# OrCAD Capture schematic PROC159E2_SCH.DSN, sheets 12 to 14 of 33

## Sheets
12 28. LED DRIVER AND IO EXPANDER: size C; title: LED DRIVER AND IO EXPANDER
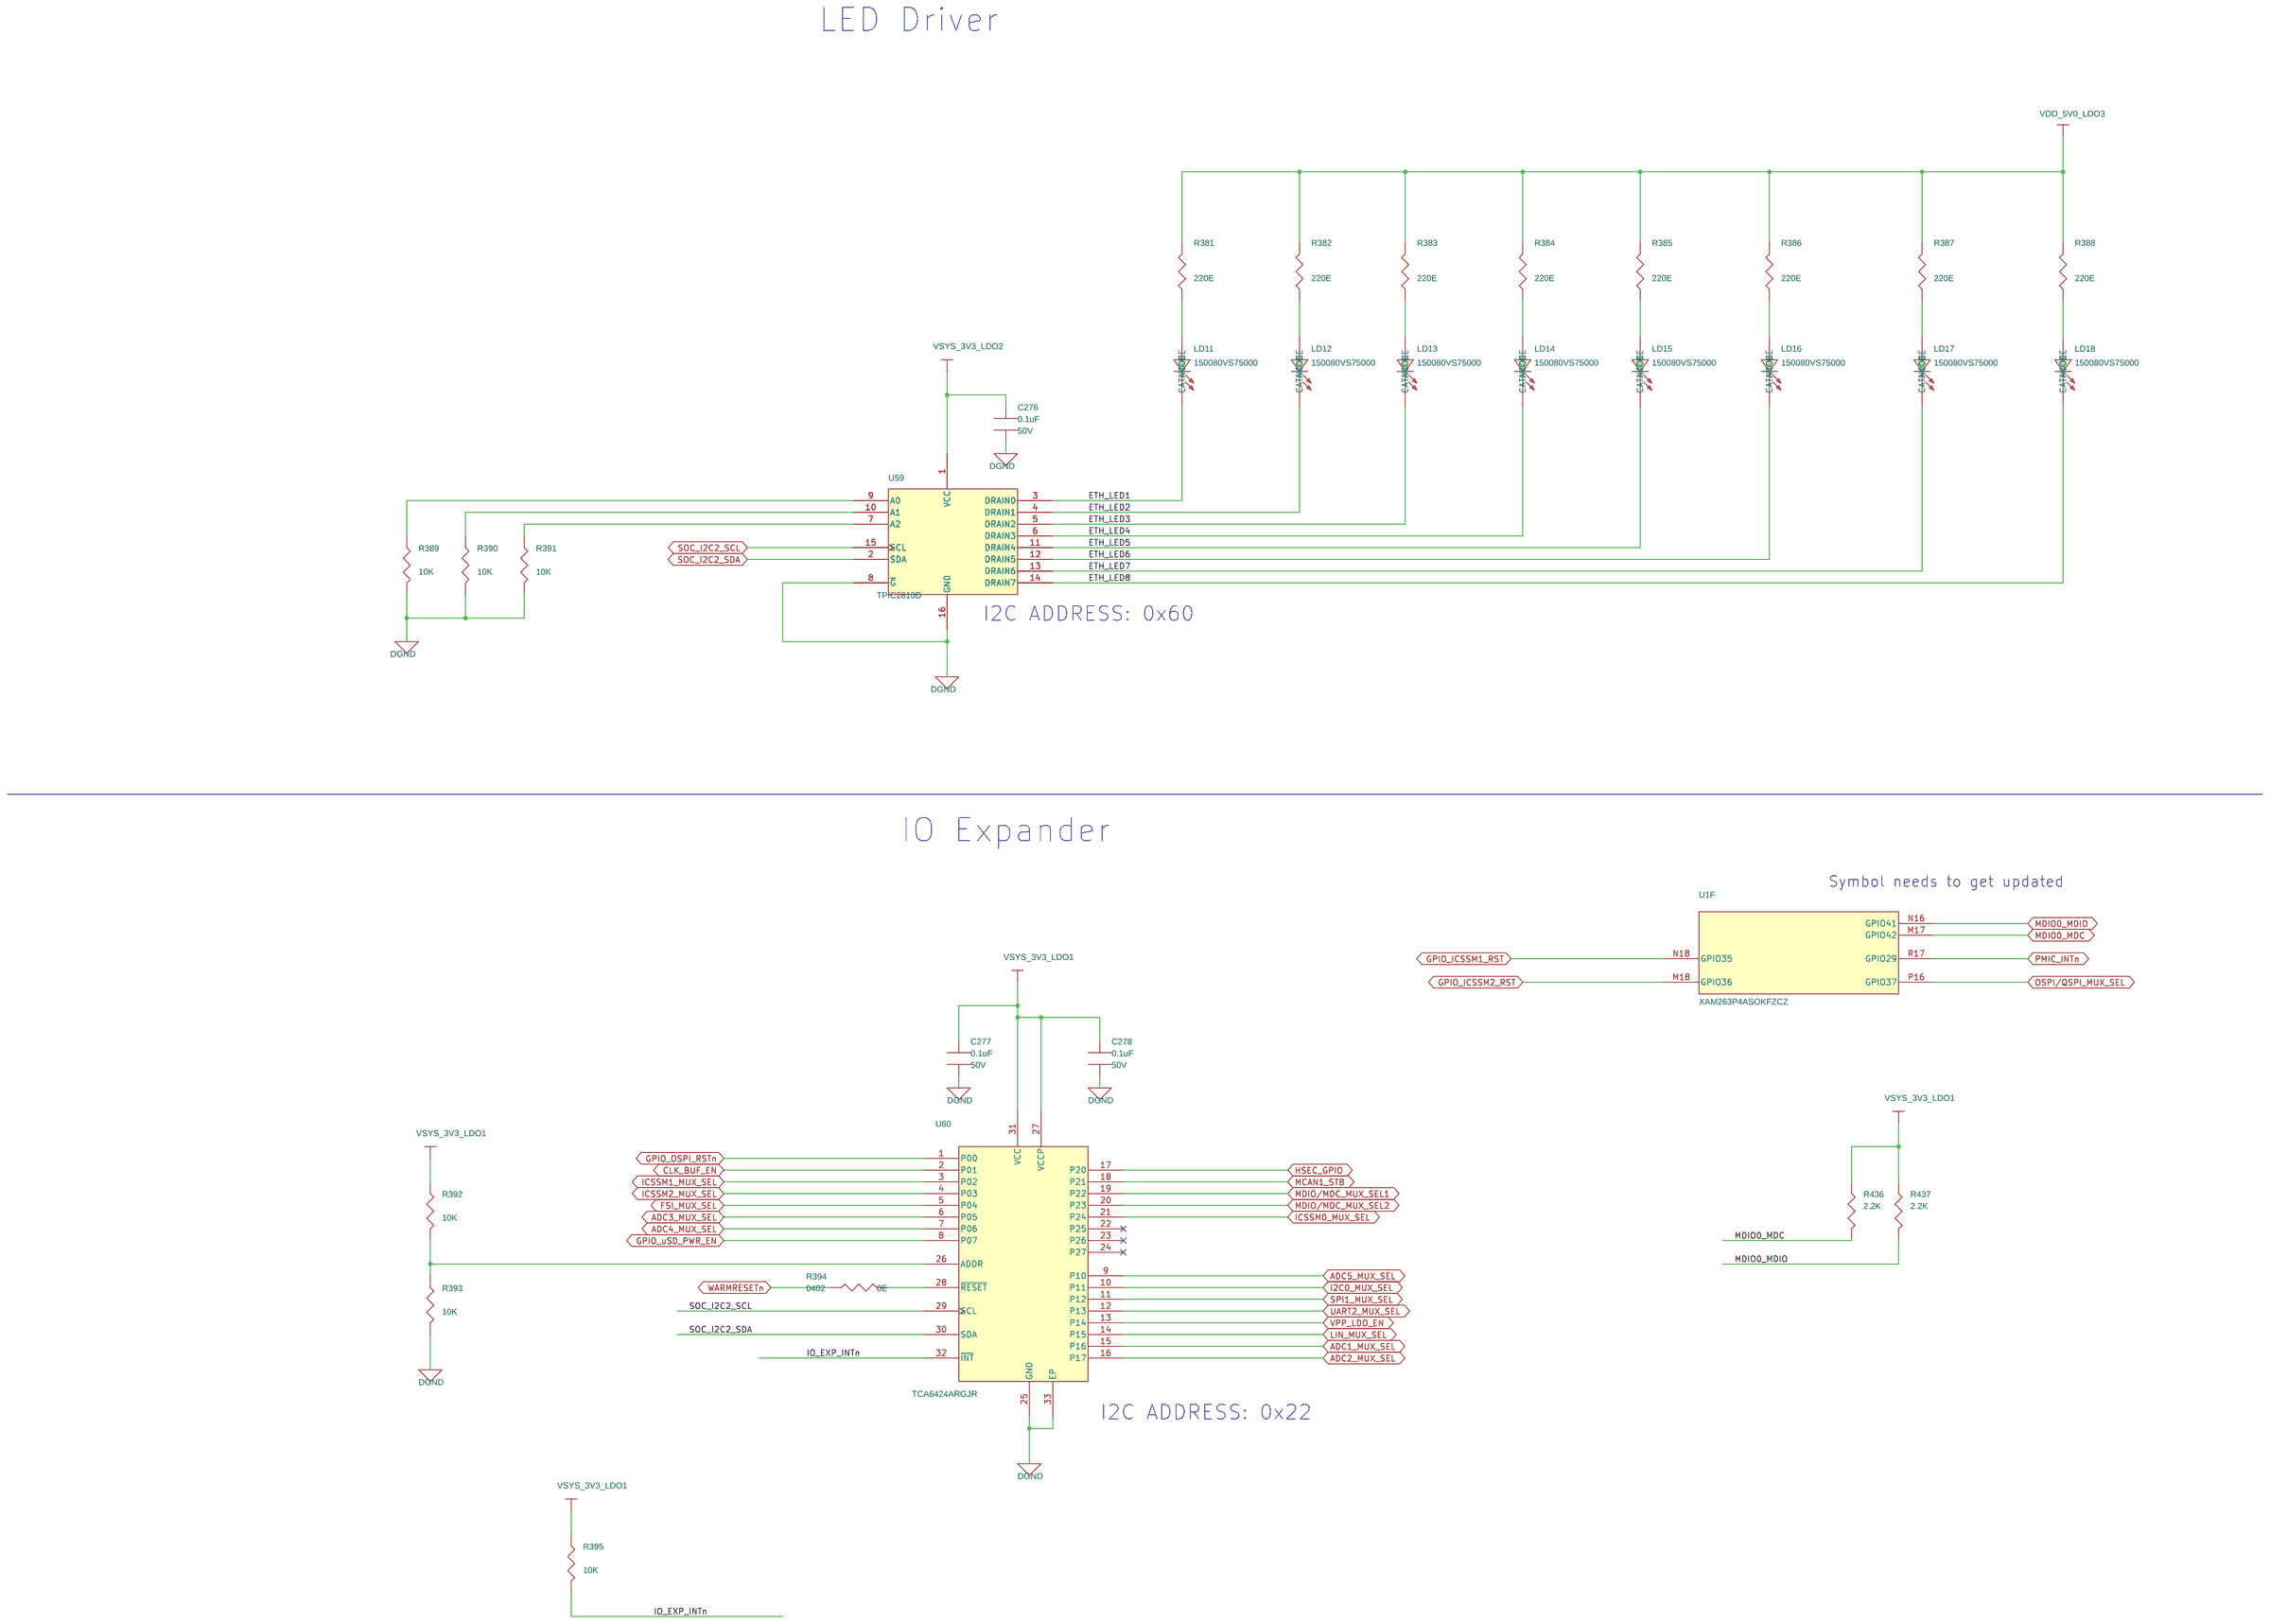
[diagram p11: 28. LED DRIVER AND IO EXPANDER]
13 18. MCAN AND FSI MUX: size C; title: MCAN AND FSI MUX
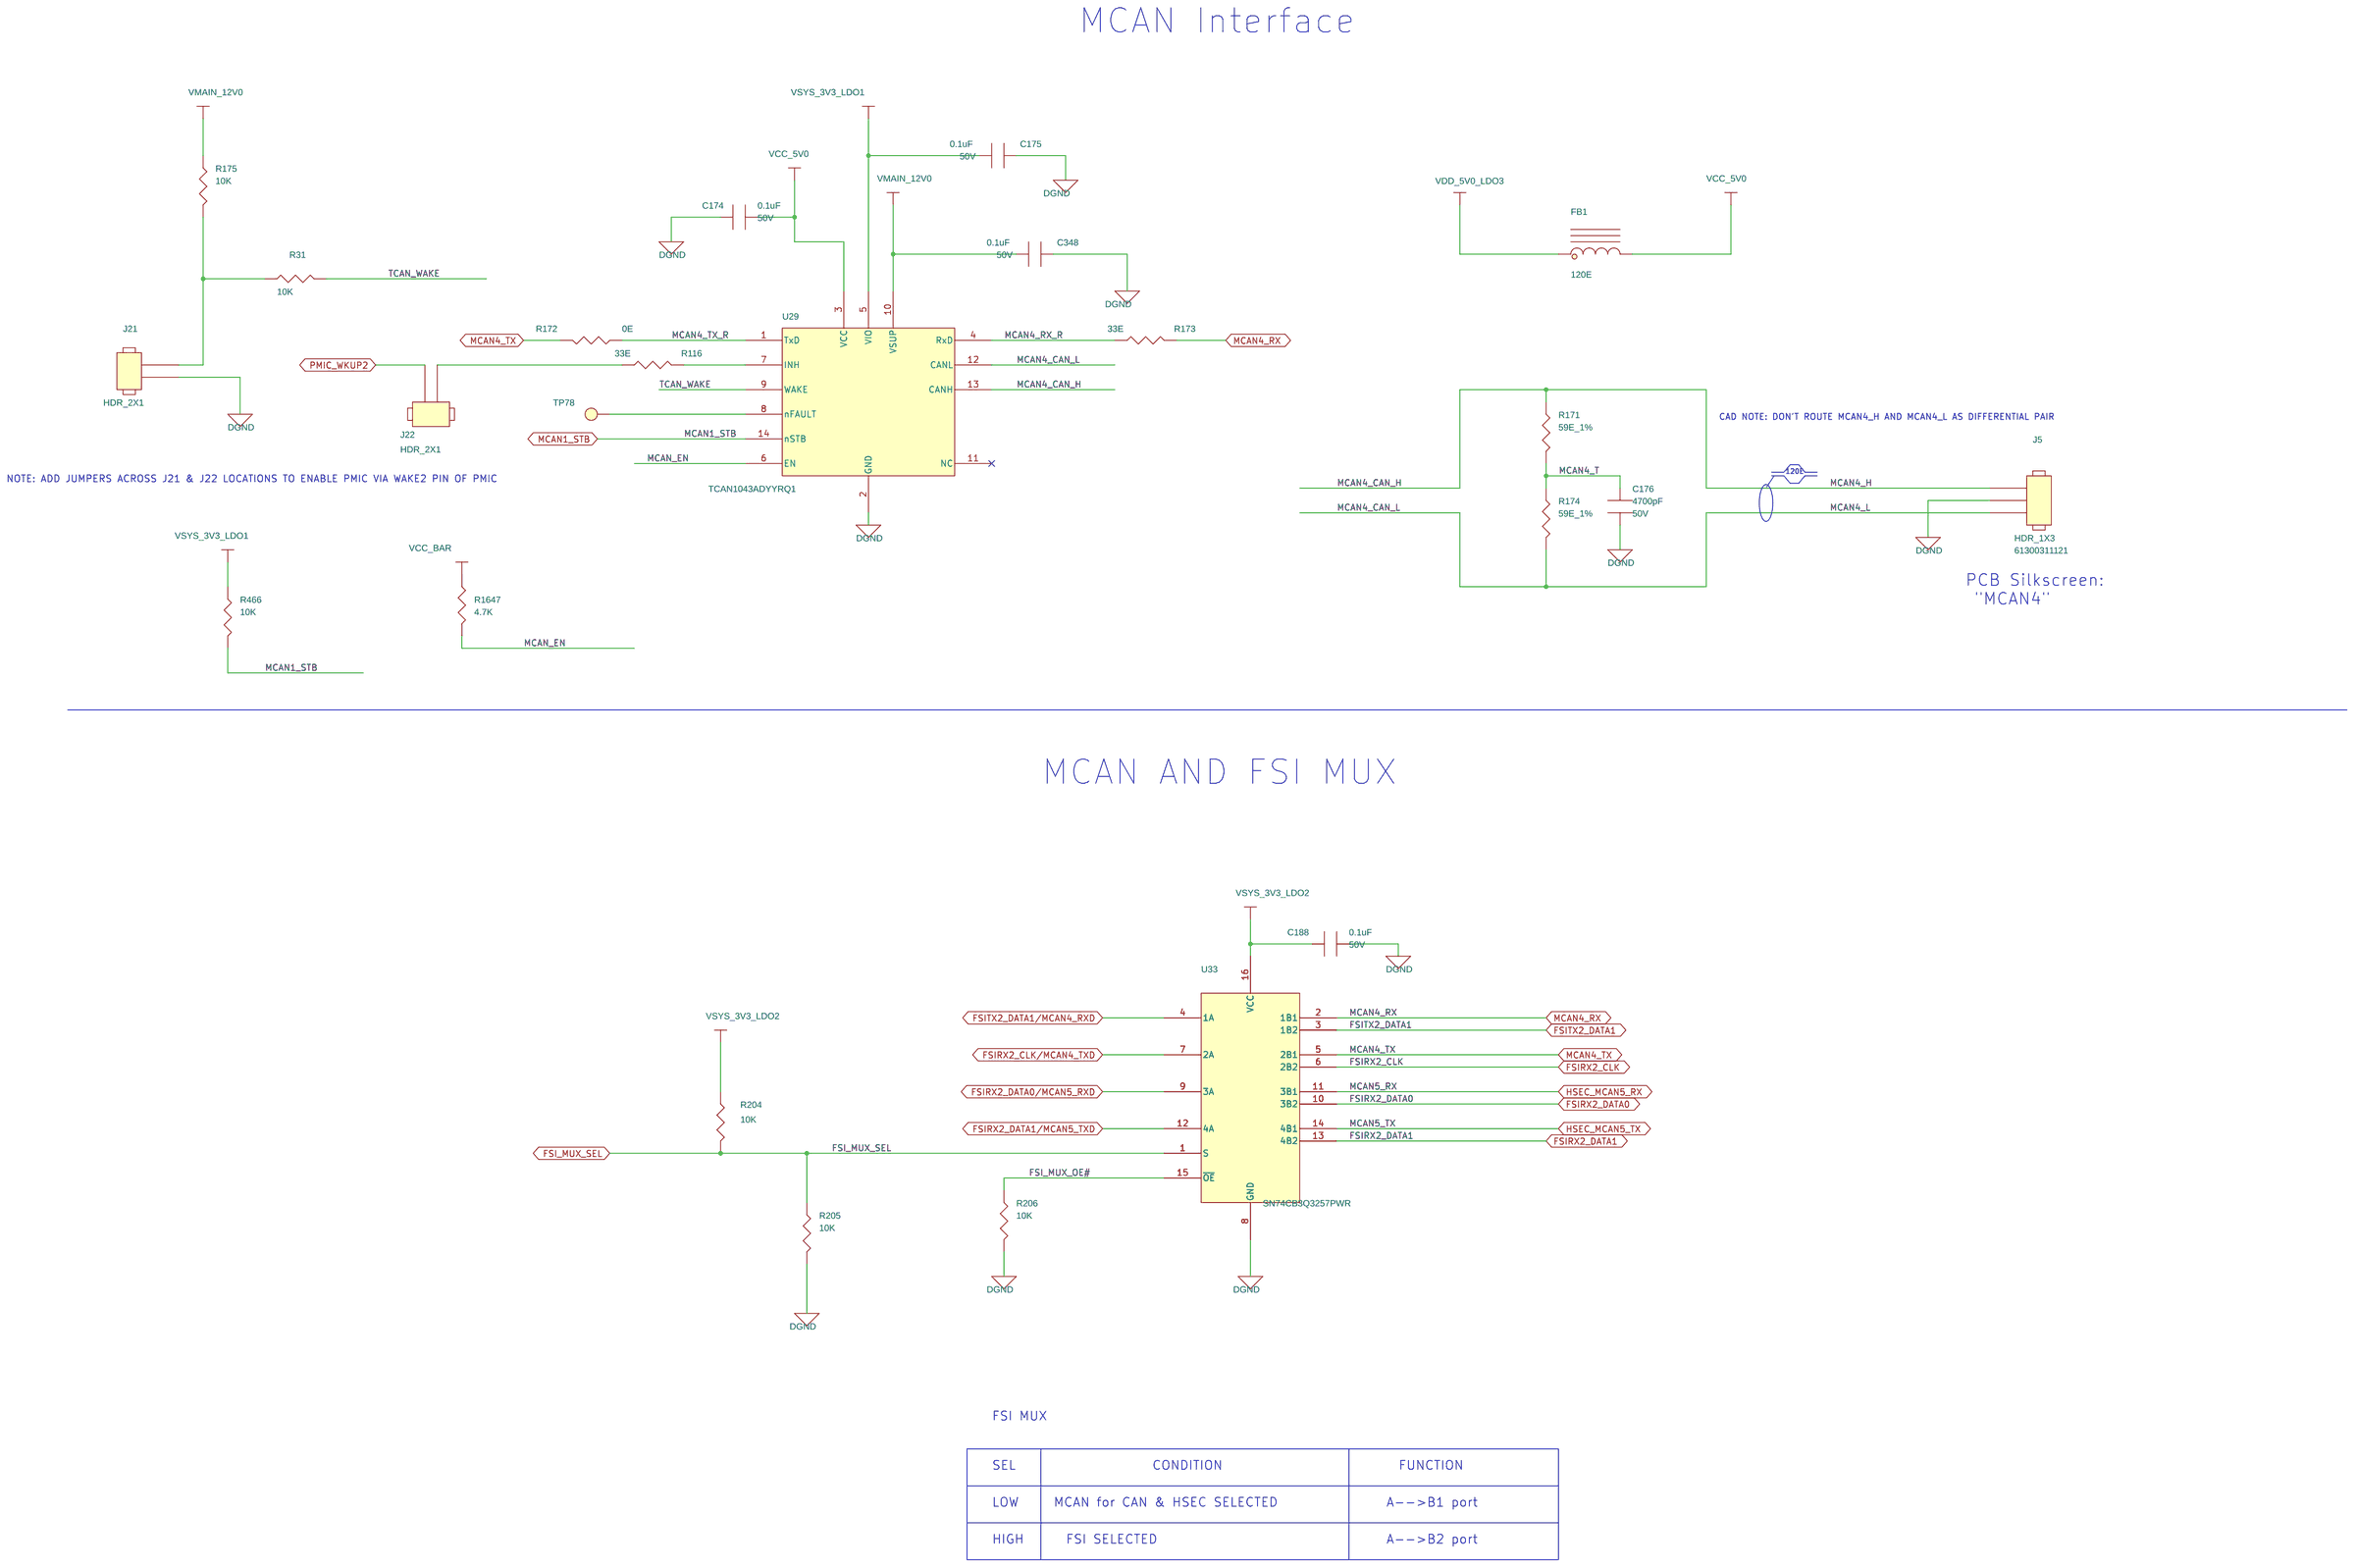
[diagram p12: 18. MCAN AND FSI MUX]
14 12. ETHERNET POWERS: size C; title: ETHERNET POWERS

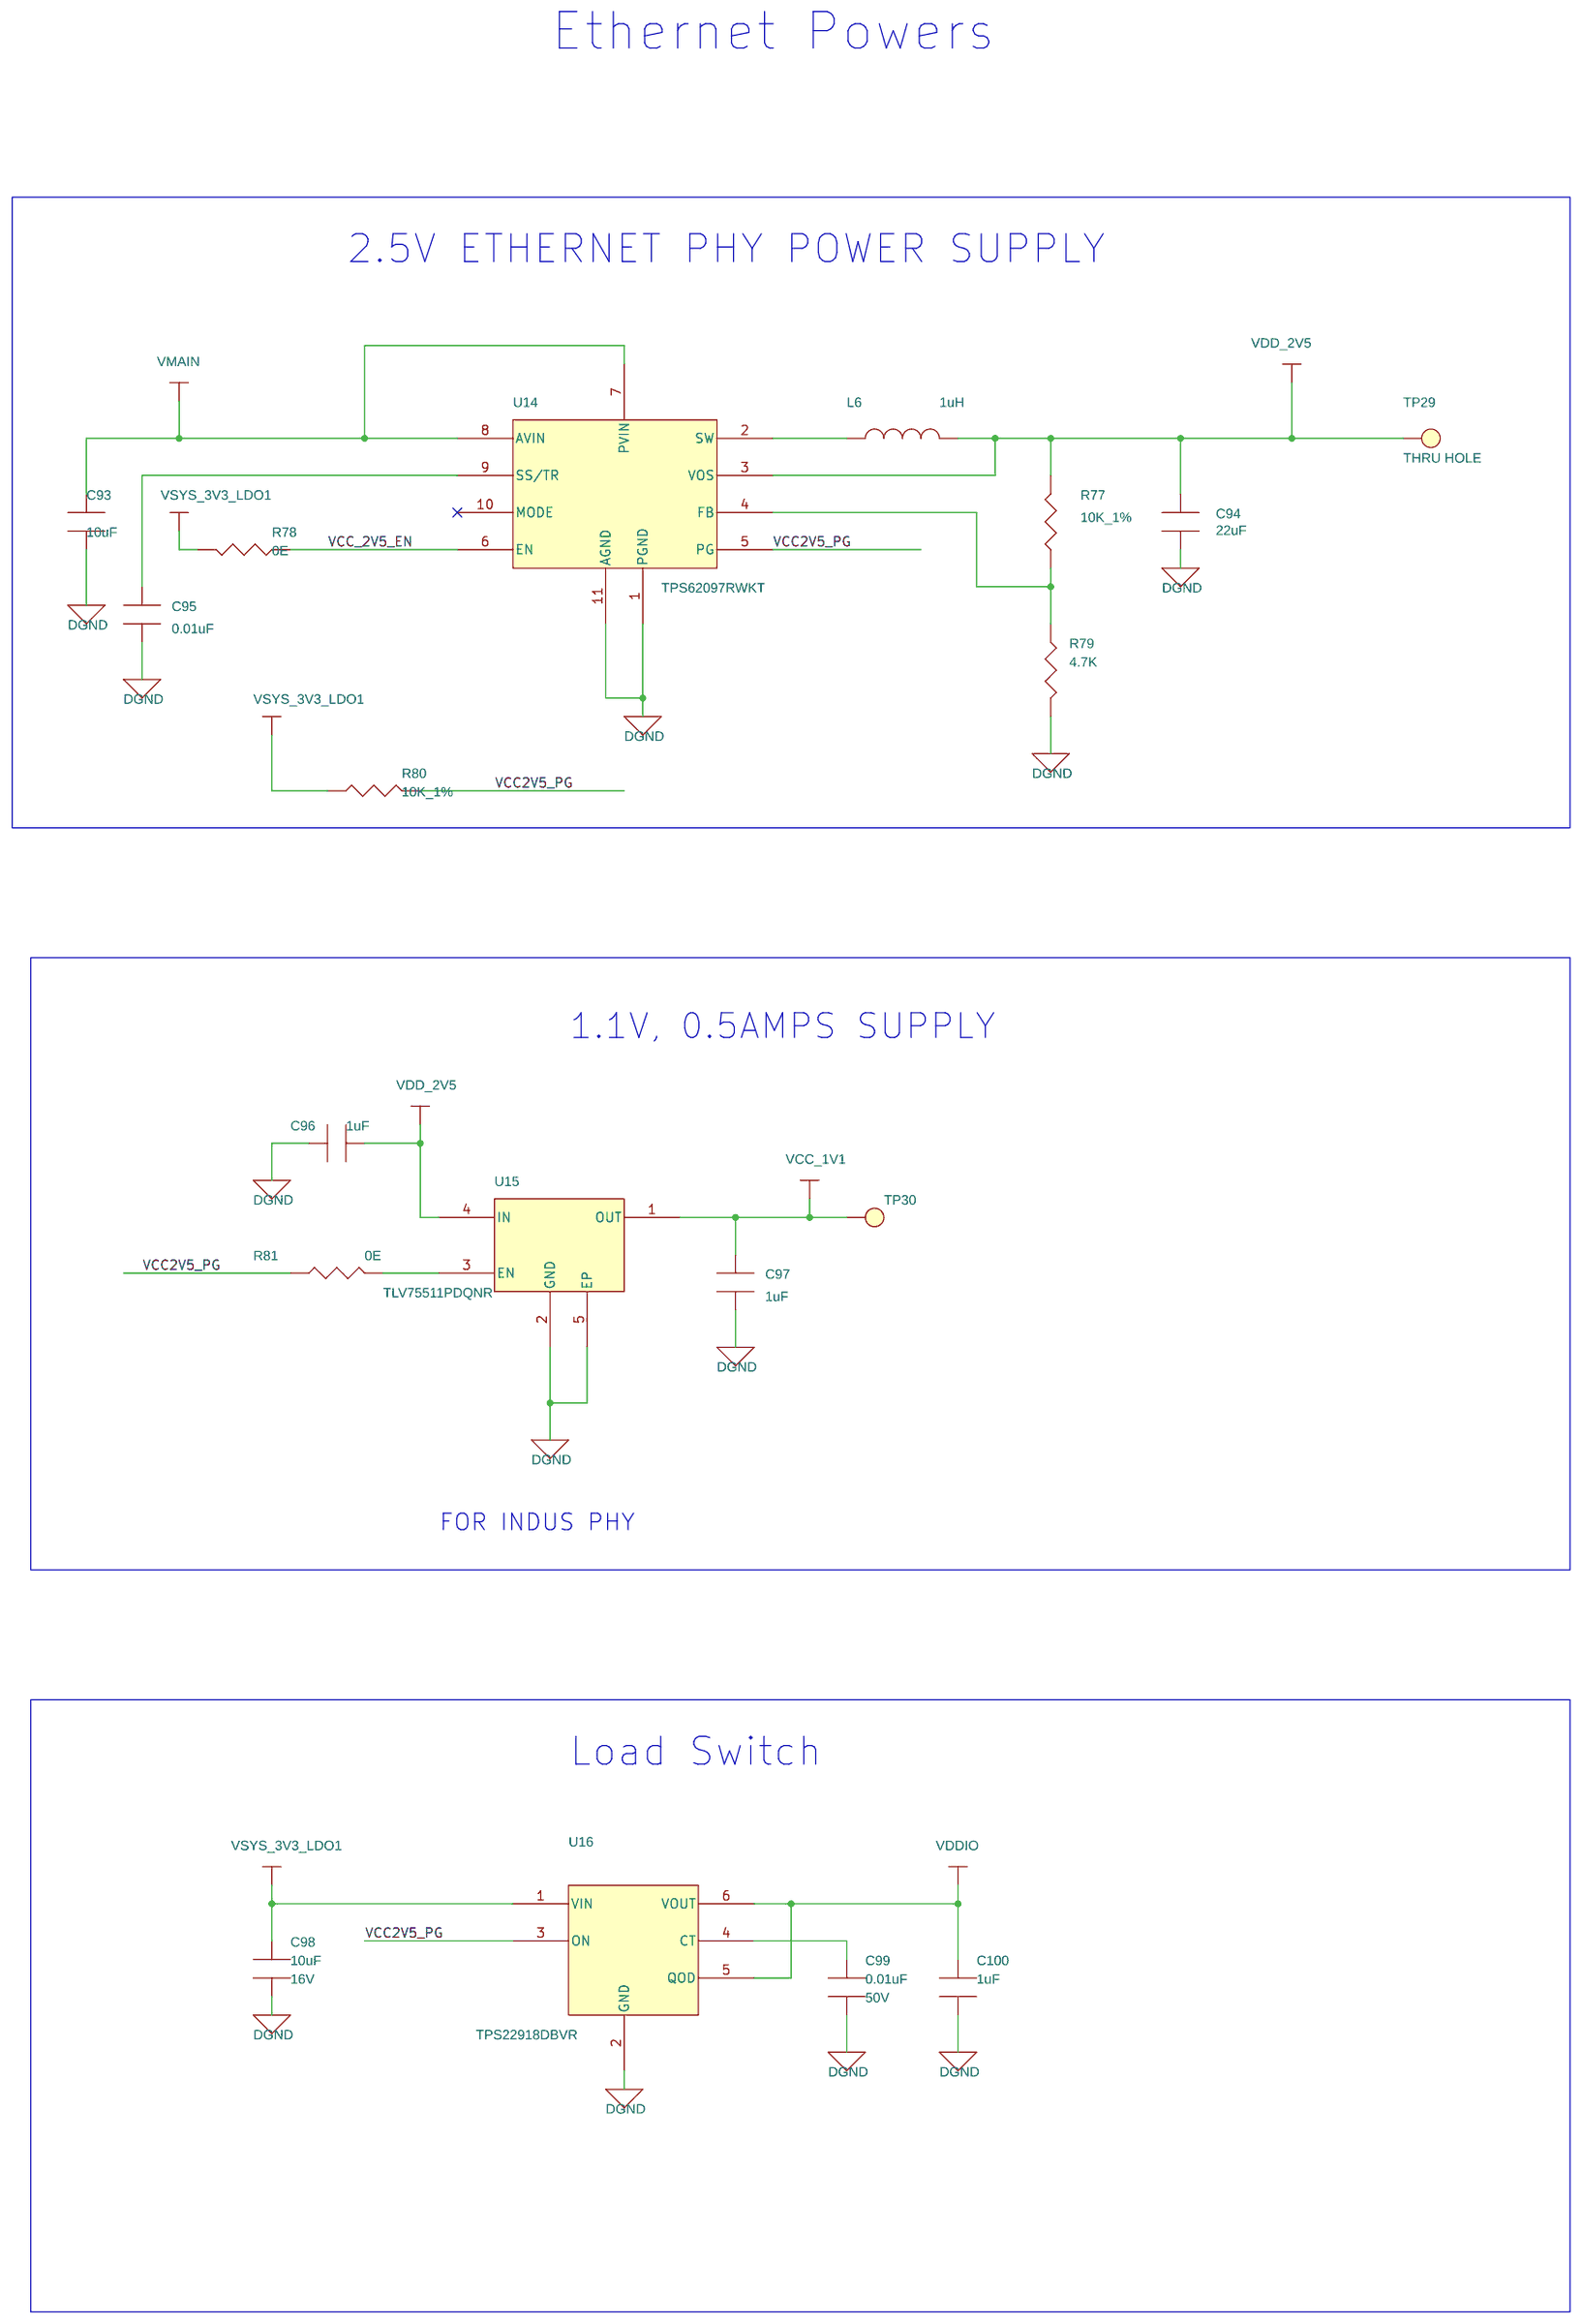
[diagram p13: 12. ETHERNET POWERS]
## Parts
sheet 12. ETHERNET POWERS
C93  10uF  [CAP0603_1]
C94  22uF  [CAP0603_1]
C95  0.01uF  [CAP0402_0-75]
C96  1uF  [CAP0201_0-5]
C97  1uF  [CAP0201_0-5]
C98  10uF  [CAP0603_1]
C99  0.01uF  [CAP0402_0-75]
C100  1uF  [CAP0402_0-75]
L6  1uH  [IND_IHLP2020B_230X215_SMD]
R77  10K_1%  [RES0402_0-5]
R78  0E  [RES0402_0-5]
R79  4.7K  [RES0402_0-5]
R80  10K_1%  [RES0402_0-5]
R81  0E  [RES0201_0-5]
TP29  THRU HOLE  [TP_40X65]
TP30  TP20_SMD  [TP20_SMD]
U14  TPS62097RWKT  [VQFNHR11_TPS62097_80X80_1]
U15  TLV75511PDQNR  [X2SON4_TLV71318P_40X40_0-4]
U16  TPS22918DBVR  [SOT23-6]
sheet 18. MCAN AND FSI MUX
C174  0.1uF  [CAP0402_0-75]
C175  0.1uF  [CAP0402_0-75]
C176  4700pF  [CAP0402_0-75]
C188  0.1uF  [CAP0402_0-75]
C348  0.1uF  [CAP0402_0-75]
FB1  120E  [EMIFIL_BLM18S_0603_0-7]
J5  HDR_1X3  [HDR_1X3_100_S_T]
J21  HDR_2X1  [HDR_2X1_100_S_T_10-8]
J22  HDR_2X1  [HDR_2X1_100_S_T_10-8]
R31  10K  [RES0402_0-5]
R116  33E  [RES0402_0-5]
R171  59E_1%  [RES0402_0-5]
R172  0E  [RES0402_0-5]
R173  33E  [RES0402_0-5]
R174  59E_1%  [RES0402_0-5]
R175  10K  [RES0402_0-5]
R204  10K  [RES0402_0-5]
R205  10K  [RES0402_0-5]
R206  10K  [RES0402_0-5]
R466  10K  [RES0402_0-5]
R1647  4.7K  [RES0402_0-5]
TP78  TP20_SMD  [TP20_SMD]
U29  TCAN1043ADYYRQ1  [SOT23-14_1-1]
U33  SN74CB3Q3257PWR  [TSSOP16_25-59_205X180]
sheet 28. LED DRIVER AND IO EXPANDER
C276  0.1uF  [CAP0402_0-75]
C277  0.1uF  [CAP0402_0-75]
C278  0.1uF  [CAP0402_0-75]
LD11  150080VS75000  [LED_150080VS75000_80X50_SMD_0-8]
LD12  150080VS75000  [LED_150080VS75000_80X50_SMD_0-8]
LD13  150080VS75000  [LED_150080VS75000_80X50_SMD_0-8]
LD14  150080VS75000  [LED_150080VS75000_80X50_SMD_0-8]
LD15  150080VS75000  [LED_150080VS75000_80X50_SMD_0-8]
LD16  150080VS75000  [LED_150080VS75000_80X50_SMD_0-8]
LD17  150080VS75000  [LED_150080VS75000_80X50_SMD_0-8]
LD18  150080VS75000  [LED_150080VS75000_80X50_SMD_0-8]
R381  220E  [RES0402_0-5]
R382  220E  [RES0402_0-5]
R383  220E  [RES0402_0-5]
R384  220E  [RES0402_0-5]
R385  220E  [RES0402_0-5]
R386  220E  [RES0402_0-5]
R387  220E  [RES0402_0-5]
R388  220E  [RES0402_0-5]
R389  10K  [RES0402_0-5]
R390  10K  [RES0402_0-5]
R391  10K  [RES0402_0-5]
R392  10K  [RES0402_0-5]
R393  10K  [RES0402_0-5]
R394  0E  [RES0402_0-5]
R395  10K  [RES0402_0-5]
R436  2.2K  [RES0402_0-5]
R437  2.2K  [RES0402_0-5]
U1  XAM263P4ASOKFZCZ  [BGA324_31-49_590X590_1-4]  (sections A,B,C,D,E,F,G,H,I,J,K,L,M)
U59  TPIC2810D  [SOIC16_1-8]
U60  TCA6424ARGJR  [QFN32_19-68_200X200]

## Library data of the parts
C93 C98 = CAP: CAP CERAMIC 10uF 16V 20% X6S 0603; Chkd/date: VASANTHA/170117; Crtd /date: VASANTHA/170117; Custom_Duty: 15%; Customs_HS_Code: 85322990; Distributor_name: DIGIKEY; Distributor_part_number: 490-7198-1-ND; Footprint Path: Y:\MIS_DATABASE\Library\ALTIUM_TOOL\PCB_FOOTPRINTS\Altium_Footprint_Lib.PcbLib; Height: 0.90MM; Library Path: Y:\MIS_DATABASE\Library\ALTIUM_TOOL\SCHEMATICS_PARTS\MS_DISCRETE_Library.schlib; Mfr_name: MURATA; Mfr_part_number: GRM188C81C106MA73D; Mistral Part No: 120017010004-R; Package: 0603; Part_type: CAPACITORS\CERAMIC; Project: TRMM_SMART-M_PS; RoHS: RoHS; Temperature: -55°C+105°C; Tolerance: 20%; Voltage: 16V; Wattage: NA; Weight: 6.3mg; Datasheet: Y:\MIS_DATABASE\DATASHEETS\CAPACITORS\MURATA-GXX-SER_NOV17.PDF
C94 = CAP: CAP CERAMIC 22uF 6.3V 20% X5R 0603; Chkd/date: JEBRAN/090915; Crtd /date: JEBRAN/090915; Custom_Duty: 15%; Customs_HS_Code: 85322990; Distributor_name: DIGIKEY; Distributor_part_number: 490-7611-2-ND; Footprint Path: Y:\MIS_DATABASE\Library\ALTIUM_TOOL\PCB_FOOTPRINTS\Altium_Footprint_Lib.PcbLib; Height: 1.00MM; Library Path: Y:\MIS_DATABASE\Library\ALTIUM_TOOL\SCHEMATICS_PARTS\MS_DISCRETE_Library.schlib; Mfr_name: MURATA; Mfr_part_number: GRM188R60J226MEA0; Mistral Part No: 120015090007-R; Package: 0603; Part_type: CAPACITORS\CERAMIC; Project: OCTBTS_3000; RoHS: RoHS; Temperature: -55°C+85°C; Tolerance: 20%; Voltage: 6.3V; Wattage: NA; Weight: 6.3mg; Datasheet: Y:\MIS_DATABASE\DATASHEETS\CAPACITORS\MURATA-GXX-SER_NOV17.PDF
C95 = CAP: CAP CERAMIC 0.01uF 50V 10% X7R 0402; Chkd/date: MANIRAJA/280319; Crtd /date: MANIRAJA/280319; Custom_Duty: 15%; Customs_HS_Code: 85322990; Distributor_name: DIGIKEY; Distributor_part_number: 490-4516-1-ND; Footprint Path: Y:\MIS_DATABASE\Library\ALTIUM_TOOL\PCB_FOOTPRINTS\Altium_Footprint_Lib.PcbLib; Height: 0.55MM; Library Path: Y:\MIS_DATABASE\Library\ALTIUM_TOOL\SCHEMATICS_PARTS\MS_DISCRETE_Library.schlib; Mfr_name: MURATA; Mfr_part_number: GRM155R71H103KA88D; Mistral Part No: 120009030025-R; Package: 0402; Part_type: CAPACITORS\CERAMIC; Project: G4_SVGA; RoHS: RoHS; Temperature: -55°C+125°C; Tolerance: 10%; Voltage: 50V; Wattage: NA; Weight: 0.65mg; Datasheet: Y:\MIS_DATABASE\DATASHEETS\CAPACITORS\GRM155R71H103KA88D.PDF
C96 C97 = CAP: CAP CERAMIC 1uF 16V 20% X5R 0201; Chkd/date: MANIRAJA/300520; Crtd /date: ALVY/260520; Custom_Duty: 15%; Customs_HS_Code: 85322990; Distributor_name: DIGIKEY; Distributor_part_number: 490-18654-1-ND; Footprint Path: Y:\MIS_DATABASE\Library\ALTIUM_TOOL\PCB_FOOTPRINTS\Altium_Footprint_Lib.PcbLib; Height: 0.39MM; Library Path: Y:\MIS_DATABASE\Library\ALTIUM_TOOL\SCHEMATICS_PARTS\MS_DISCRETE_Library.schlib; Mfr_name: MURATA; Mfr_part_number: GRM033R61C105ME15D; Mistral Part No: 120018090038-R; Package: 0201; Part_type: CAPACITORS\CERAMIC; Project: QCS610_NANOSOM; RoHS: RoHS; Temperature: -55°C+85°C; Tolerance: 20%; Voltage: 16V; Wattage: NA; Weight: 0.33mg; Datasheet: Y:\MIS_DATABASE\DATASHEETS\CAPACITORS\GRM033R61C105ME15.PDF
C99 = CAP: CAP CERAMIC 0.01uF 50V 10% X7R 0402; Assembly_Instruction: DNI; Chkd/date: MANIRAJA/280319; Crtd /date: MANIRAJA/280319; Custom_Duty: 15%; Customs_HS_Code: 85322990; Distributor_name: DIGIKEY; Distributor_part_number: 490-4516-1-ND; Footprint Path: Y:\MIS_DATABASE\Library\ALTIUM_TOOL\PCB_FOOTPRINTS\Altium_Footprint_Lib.PcbLib; Height: 0.55MM; Library Path: Y:\MIS_DATABASE\Library\ALTIUM_TOOL\SCHEMATICS_PARTS\MS_DISCRETE_Library.schlib; Mfr_name: MURATA; Mfr_part_number: GRM155R71H103KA88D; Mistral Part No: 120009030025-R; Package: 0402; Part_type: CAPACITORS\CERAMIC; Project: G4_SVGA; RoHS: RoHS; Temperature: -55°C+125°C; Tolerance: 10%; Voltage: 50V; Wattage: NA; Weight: 0.65mg; Datasheet: Y:\MIS_DATABASE\DATASHEETS\CAPACITORS\GRM155R71H103KA88D.PDF
C100 = CAP: CAP CERAMIC 1uF 25V 10% X6S 0402; Chkd/date: MANIRAJA/140518; Crtd /date: ALVY/140518; Custom_Duty: 15%; Customs_HS_Code: 85322990; Distributor_name: DIGIKEY; Distributor_part_number: 490-10014-1-ND; Footprint Path: Y:\MIS_DATABASE\Library\ALTIUM_TOOL\PCB_FOOTPRINTS\Altium_Footprint_Lib.PcbLib; Height: 0.60MM; Library Path: Y:\MIS_DATABASE\Library\ALTIUM_TOOL\SCHEMATICS_PARTS\MS_DISCRETE_Library.schlib; Mfr_name: MURATA; Mfr_part_number: GRM155C81E105KE11D; Mistral Part No: 120018050004-R; Package: 0402; Part_type: CAPACITORS\CERAMIC; Project: TI_SVB_MAXWELL_DUT; RoHS: RoHS; Temperature: -55°C+105°C; Tolerance: 10%; Voltage: 25V; Wattage: NA; Weight: 6mg; Datasheet: Y:\MIS_DATABASE\DATASHEETS\CAPACITORS\GRM155C81E105KE11X.PDF
L6 = INDUCTOR: IND POWER 1uH 7A 20% SMD; Chkd/date: BAVISH/260911; Crtd /date: CHAITHANYA/260911; Custom_Duty: 24%; Customs_HS_Code: 85437099; Distributor_name: DIGIKEY; Distributor_part_number: 541-1087-1-ND; Height: 2.00MM; Mfr_name: VISHAY; Mfr_part_number: IHLP2020BZER1R0M01; Mistral Part No: 130011090053-R; Package: SMD; Project: GEMYC; RoHS: RoHS; Temperature: -55°C+125°C; Tolerance: 20%; Voltage: NA; Wattage: NA; Weight: NA; Datasheet: Y:\MIS_DATABASE\DATASHEETS\DISCRETES\INDUCTORS\IHLP2020BZ-01.PDF
R77 R80 = RESISTOR: RES 10K 1/16W 1% 0402; Chkd/date: VASANTHA/201216; Crtd /date: GEETHA/290506; Custom_Duty: 15%; Customs_HS_Code: 85332119; Distributor_name: DIGIKEY; Distributor_part_number: 311-10.0KLRTR-ND; Footprint Path: Y:\MIS_DATABASE\Library\ALTIUM_TOOL\PCB_FOOTPRINTS\Altium_Footprint_Lib.PcbLib; Height: 0.40MM; Library Path: Y:\MIS_DATABASE\Library\ALTIUM_TOOL\SCHEMATICS_PARTS\MS_DISCRETE_Library.schlib; Mfr_name: YAGEO AMERICA; Mfr_part_number: RC0402FR-0710KL; Mistral Part No: 110015090015-R; Package: 0402; Part_type: RESISTORS\FIXED; Project: VOCERA; RoHS: RoHS; Temperature: -55°C+155°C; Tolerance: 1%; Voltage: NA; Wattage: 1/16W; Weight: 0.65mg; Datasheet: Y:\MIS_DATABASE\DATASHEETS\RESISTORS\RCXXXXL-SER_MAR18.PDF
R78 R172 R394 = RESISTOR: RES 0E 1/10W JUMPER 0402; Chkd/date: VASANTHA/061216; Crtd /date: NAVEED/201014; Custom_Duty: 15%; Customs_HS_Code: 85332119; Distributor_name: DIGIKEY; Distributor_part_number: P0.0JCT-ND; Footprint Path: Y:\MIS_DATABASE\Library\ALTIUM_TOOL\PCB_FOOTPRINTS\Altium_Footprint_Lib.PcbLib; Height: 0.40MM; IBISSP_MODLES: VALUE REPEATING 2 TIME; Library Path: Y:\MIS_DATABASE\Library\ALTIUM_TOOL\SCHEMATICS_PARTS\MS_DISCRETE_Library.schlib; Mfr_name: PANASONIC-ECG; Mfr_part_number: ERJ-2GE0R00X; Mistral Part No: 110018030052-R; Package: 0402; Part_type: RESISTORS\FIXED; Project: AEGIS POM; RoHS: RoHS; Temperature: -55°C+155°C; Tolerance: NA; Voltage: NA; Wattage: 1/10W; Weight: 0.8mg; Datasheet: Y:\MIS_DATABASE\DATASHEETS\RESISTORS\PAN-ERJSER_NOV17.PDF
R79 R1647 = RESISTOR: RES 4.7K 1/16W 5% 0402; Chkd/date: VASANTHA/281216; Crtd /date: BAVISH/010611; Custom_Duty: 15%; Customs_HS_Code: 85332119; Distributor_name: DIGIKEY; Distributor_part_number: 541-4.7KJCT-ND; Footprint Path: Y:\MIS_DATABASE\Library\ALTIUM_TOOL\PCB_FOOTPRINTS\Altium_Footprint_Lib.PcbLib; Height: 0.40MM; Library Path: Y:\MIS_DATABASE\Library\ALTIUM_TOOL\SCHEMATICS_PARTS\MS_DISCRETE_Library.schlib; Mfr_name: VISHAY; Mfr_part_number: CRCW04024K70JNED; Mistral Part No: 110011060001-R; Package: 0402; Part_type: RESISTORS\FIXED; Project: AM4515_EVM_LCD; RoHS: RoHS; Temperature: -55°C+155°C; Tolerance: 5%; Voltage: NA; Wattage: 1/16W; Weight: 0.65mg; Datasheet: Y:\MIS_DATABASE\DATASHEETS\RESISTORS\CRCW0603.PDF
R81 = RESISTOR: RES 0E 1/20W 5% 0201; Chkd/date: NAVEED/301214; Crtd /date: MUDDU/120710; Custom_Duty: 15%; Customs_HS_Code: 85332119; Distributor_name: DIGIKEY; Distributor_part_number: 311-0.0NCT-ND; Footprint Path: Y:\MIS_DATABASE\Library\ALTIUM_TOOL\PCB_FOOTPRINTS\Altium_Footprint_Lib.PcbLib; Height: 0.26MM; Library Path: Y:\MIS_DATABASE\Library\ALTIUM_TOOL\SCHEMATICS_PARTS\MS_DISCRETE_Library.schlib; Mfr_name: YAGEO AMERICA; Mfr_part_number: RC0201JR-070RL; Mistral Part No: 110010070067-R; Package: 0201; Part_type: RESISTORS\FIXED; Project: PB_BUGBASE; RoHS: RoHS; Temperature: -55°C+125°C; Tolerance: 5%; Voltage: NA; Wattage: 1/20W; Weight: 0.17mg; Datasheet: Y:\MIS_DATABASE\DATASHEETS\RESISTORS\RCXXXXL-SER_MAR18.PDF
TP29 = TESTPOINT: TESTPOINT 1.0MM DRILL PTH; Chkd/date: MAZHAR/271211; Crtd /date: SHREESHAIL/041005; Distributor_name: NA; Distributor_part_number: NA; Height: NA; Mfr_name: LOCAL; Mistral Part No: 130009030938; Package: THRU-HOLE; Project: HSE; Datasheet: NA
TP30 TP78 = TESTPOINT: TESTPOINT CIR 20 SMD; Chkd/date: SHREESHAIL/171006; Crtd /date: MAZHAR/171006; Custom_Duty: NA; Customs_HS_Code: NA; Distributor_name: NA; Distributor_part_number: NA; Footprint Path: Y:\MIS_DATABASE\Library\ALTIUM_TOOL\PCB_FOOTPRINTS\Altium_Footprint_Lib.PcbLib; Height: NA; Library Path: Y:\MIS_DATABASE\Library\ALTIUM_TOOL\SCHEMATICS_PARTS\MS_DISCRETE_Library.schlib; MECHANICAL 3D STEP FILE: NA; Mfr_name: LOCAL; Mistral Part No: NA; Package: SMD; Project: BT MODULE_CSRBC04; RoHS: NA; Temperature: NA; Tolerance: NA; Voltage: NA; Wattage: NA; Weight: NA; Datasheet: NA
U14 = TPS62097RWKT_VQFNHR11: IC 2A SYNCHRONOUS STEP DOWN CONVERTER WITH IDCS CONTROL VQFN-HR11; Chkd/date: MANIRAJA/270917; Crtd /date: MANIRAJA/270917; Custom_Duty: 15%; Customs_HS_Code: 85423100; Distributor_name: DIGIKEY; Distributor_part_number: 296-43330-1-ND; Height: 1.00MM; Mfr_name: TEXAS INSTRUMENTS; Mistral Part No: 142017090025-R; Package: VQFN-HR11; Part_type: ICS\POWER\CONVERTER; Project: TI_MAXIE_CPB; RoHS: RoHS; Temperature: -40°C+125°C; Tolerance: NA; Voltage: NA; Wattage: NA; Weight: NA; Datasheet: Y:\MIS_DATABASE\DATASHEETS\ICS\POWER\TPS62097.PDF
U15 = TLV71318PDQNR_X2SON4: IC 500mA 1.1V LOW IQ LDO REGULATOR X2SON-4; Chkd/date: MANIRAJA/011021; Crtd /date: ALVY/011021; Custom_Duty: 15%; Customs_HS_Code: 85423100; Distributor_name: DIGIKEY; Distributor_part_number: 296-51784-1-ND; Footprint Path: Y:\MIS_DATABASE\Library\ALTIUM_TOOL\PCB_FOOTPRINTS\Altium_Footprint_Lib.PcbLib; Height: 0.40MM; Library Path: Y:\MIS_DATABASE\Library\ALTIUM_TOOL\SCHEMATICS_PARTS\MS_MISCPOWER_Library.schlib; Mfr_name: TEXAS INSTRUMENTS; Mistral Part No: 142021100002-R; Package: X2SON-4; Part_type: ICS\POWER\VOLTAGE REGULATOR; Project: TI_AM62x SKEVM_BRD; RoHS: RoHS; Temperature: -40°C+125°C; Tolerance: NA; Voltage: NA; Wattage: NA; Weight: 1.1mg; Datasheet: Y:\MIS_DATABASE\DATASHEETS\ICS\POWER\TLV755P.PDF
U16 = TPS22918DBVR_SOT23-6: IC ON RESISTANCE LOAD SWITCH SOT23-6; Chkd/date: VASANTHA/130516; Crtd /date: VASANTHA/130516; Custom_Duty: 15%; Customs_HS_Code: 85423100; Distributor_name: DIGIKEY; Distributor_part_number: TPS22918DBVR-ND; Height: 1.45MM; Mfr_name: TEXAS INSTRUMENTS; Mistral Part No: 142016050007-R; Part_type: ICS\POWER; Project: TMDXCSK8127; RoHS: RoHS; Temperature: -40°C to 105°C; Tolerance: NA; Voltage: NA; Wattage: NA; Weight: NA; Datasheet: Y:\MIS_DATABASE\DATASHEETS\ICS\POWER\TPS22918DBV.PDF
C174 C175 C348 = CAP: CAP CERAMIC 0.1uF 50V 10% X7R 0402; Automotive Alternate_mfr_name: TDK; Automotive Alternate_mfr_part_number: CGA2B1X7R1C104K050BC; Chkd/date: MANIRAJA/261020; Crtd /date: ALVY/211020; Custom_Duty: 15%; Customs_HS_Code: 85322990; Direct Alternate_mfr_name: MURATA; Direct Alternate_mfr_part_number: GCM155R71C104JA55D; Distributor_name: DIGIKEY; Distributor_part_number: 490-10700-1-ND; Footprint Path: Y:\MIS_DATABASE\Library\ALTIUM_TOOL\PCB_FOOTPRINTS\Altium_Footprint_Lib.PcbLib; Height: 0.55MM; Library Path: Y:\MIS_DATABASE\Library\ALTIUM_TOOL\SCHEMATICS_PARTS\MS_DISCRETE_Library.schlib; Mfr_name: MURATA; Mfr_part_number: GRM155R71H104KE14D; Mistral Part No: 120011100014-R; Package: 0402; Part_type: CAPACITORS\CERAMIC; Project: J7_CP; RoHS: RoHS; Temperature: -55°C+125°C; Tolerance: 10%; Voltage: 50V; Wattage: NA; Weight: 3.1mg; Datasheet: Y:\MIS_DATABASE\DATASHEETS\CAPACITORS\GRM155R71H104KE14.PDF
C176 = CAP: CAP CERAMIC 4700pF 50V 10% X7R 0402; Automotive Alternate_mfr_name: TDK; Automotive Alternate_mfr_part_number: CGA2B2X7R1H472K050BA; Chkd/date: MANIRAJA/040419; Crtd /date: MANIRAJA/040419; Custom_Duty: 15%; Customs_HS_Code: 85322990; Direct Alternate_mfr_name: SAMSUNG; Direct Alternate_mfr_part_number: CL05B472KB5NNNC; Distributor_name: DIGIKEY; Distributor_part_number: 490-1308-1-ND; Footprint Path: Y:\MIS_DATABASE\Library\ALTIUM_TOOL\PCB_FOOTPRINTS\Altium_Footprint_Lib.PcbLib; Height: 0.55MM; Library Path: Y:\MIS_DATABASE\Library\ALTIUM_TOOL\SCHEMATICS_PARTS\MS_DISCRETE_Library.schlib; Mfr_name: MURATA; Mfr_part_number: GRM155R71H472KA01D; Mistral Part No: 120009030440-R; Package: 0402; Part_type: CAPACITORS\CERAMIC; Project: RED EYE; RoHS: RoHS; Temperature: -55°C+125°C; Tolerance: 10%; Voltage: 50V; Wattage: NA; Weight: 0.65mg; Datasheet: Y:\MIS_DATABASE\DATASHEETS\CAPACITORS\GRM155R71H472KA01.PDF
C188 C277 C278 = CAP: CAP CERAMIC 0.1uF 50V 10% X7R 0402; Automotive Alternate_mfr_name: TDK; Automotive Alternate_mfr_part_number: CGA2B3X7R1H104K050BB; Chkd/date: MANIRAJA/261020; Crtd /date: ALVY/211020; Custom_Duty: 15%; Customs_HS_Code: 85322990; Direct Alternate_mfr_name: TDK; Direct Alternate_mfr_part_number: C1005X7R1H104K050BE; Distributor_name: DIGIKEY; Distributor_part_number: 490-10700-1-ND; Footprint Path: Y:\MIS_DATABASE\Library\ALTIUM_TOOL\PCB_FOOTPRINTS\Altium_Footprint_Lib.PcbLib; Height: 0.55MM; Library Path: Y:\MIS_DATABASE\Library\ALTIUM_TOOL\SCHEMATICS_PARTS\MS_DISCRETE_Library.schlib; Mfr_name: MURATA; Mfr_part_number: GRM155R71H104KE14D; Mistral Part No: 120011100014-R; Package: 0402; Part_type: CAPACITORS\CERAMIC; Project: J7_CP; RoHS: RoHS; Temperature: -55°C+125°C; Tolerance: 10%; Voltage: 50V; Wattage: NA; Weight: 3.1mg; Datasheet: Y:\MIS_DATABASE\DATASHEETS\CAPACITORS\GRM155R71H104KE14.PDF
FB1 = INDUCTOR_FERRITE: PASSIVE FILTER CHIP 120E 3A 0603; Chkd/date: MANIRAJA/241017; Crtd /date: BAVISH/080811; Custom_Duty: 24%; Customs_HS_Code: 85437099; Distributor_name: DIGIKEY; Distributor_part_number: 490-3996-1-ND; Height: 0.65MM; Mfr_name: MURATA; Mfr_part_number: BLM18SG121TN1D; Mistral Part No: 130011080020-R; Package: 0603; Part_type: FILTER; Project: ACRO_DM3730; RoHS: RoHS; Temperature: -55°C+125°C; Tolerance: NA; Voltage: NA; Wattage: NA; Weight: NA; Datasheet: Y:\MIS_DATABASE\DATASHEETS\DISCRETES\INDUCTORS\BLM18S.PDF
J5 = HEADER_3X1: CON HDR 1X3 2.54MM PITCH ST TH; Chkd/date: VASANTHA/211015; Crtd /date: VASANTHA/211015; Custom_Duty: 24%; Customs_HS_Code: 85369090; Distributor_name: DIGIKEY; Distributor_part_number: 732-5316-ND; Height: 8.54MM; Mfr_name: WURTH ELECTRONICS INC; Mfr_part_number: 61300311121; Mistral Part No: 150015100037-R; Package: THRU-HOLE; Part_type: CONNECTOR\HEADERS; Project: CYPHY_ROADKILL; RoHS: RoHS; Temperature: NA; Tolerance: NA; Voltage: NA; Wattage: NA; Weight: NA; Datasheet: Y:\MIS_DATABASE\DATASHEETS\CONNECTORS\6130XXX.PDF
J21 J22 = HEADER_2X1: CON HDR 2X1 2.54MM PITCH ST TH; Chkd/date: VASANTHA/060117; Crtd /date: MAZHAR/280405; Custom_Duty: 24%; Customs_HS_Code: 85369090; Distributor_name: DIGIKEY; Distributor_part_number: WM4000-ND; Footprint Path: Y:\MIS_DATABASE\Library\ALTIUM_TOOL\PCB_FOOTPRINTS\Altium_Footprint_Lib.PcbLib; Height: 10.79MM; Library Path: Y:\MIS_DATABASE\Library\ALTIUM_TOOL\SCHEMATICS_PARTS\MS_CONNECTOR_Library.schlib; Mfr_name: MOLEX; Mfr_part_number: 22-03-2021; Mistral Part No: 150009030246-R; Package: THRU-HOLE; Part_type: CONNECTOR\HEADERS; Project: FPGA EXTENDER CARD; RoHS: RoHS; Temperature: -0°C+75°C; Tolerance: NA; Voltage: NA; Wattage: NA; Weight: 139gm; Datasheet: Y:\MIS_DATABASE\DATASHEETS\CONNECTORS\HEADER_X4030.PDF
R31 R175 R205 R206 R466 = RESISTOR: RES 10K 1/16W 5% 0402; Assembly_Instruction: DNI; Chkd/date: VASANTHA/061216; Crtd /date: MAZHAR/230805; Custom_Duty: 15%; Customs_HS_Code: 85332119; Distributor_name: DIGIKEY; Distributor_part_number: 311-10KJRCT-ND; Footprint Path: Y:\MIS_DATABASE\Library\ALTIUM_TOOL\PCB_FOOTPRINTS\Altium_Footprint_Lib.PcbLib; Height: 0.40MM; Library Path: Y:\MIS_DATABASE\Library\ALTIUM_TOOL\SCHEMATICS_PARTS\MS_DISCRETE_Library.schlib; Mfr_name: YAGEO AMERICA; Mfr_part_number: RC0402JR-0710KL; Mistral Part No: 110011060021-R; Package: 0402; Part_type: RESISTORS\FIXED; Project: HSE; RoHS: RoHS; Temperature: -55°C+155°C; Tolerance: 5%; Voltage: NA; Wattage: 1/16W; Weight: 0.65mg; Datasheet: Y:\MIS_DATABASE\DATASHEETS\RESISTORS\RCXXXXL-SER_MAR18.PDF
R116 R173 = RESISTOR: RES 33E 1/10W 5% 0402; Chkd/date: VASANTHA/201216; Crtd /date: GEETHA/190406; Custom_Duty: 15%; Customs_HS_Code: 85332119; Distributor_name: DIGIKEY; Distributor_part_number: P33JCT-ND; Footprint Path: Y:\MIS_DATABASE\Library\ALTIUM_TOOL\PCB_FOOTPRINTS\Altium_Footprint_Lib.PcbLib; Height: 0.40MM; Library Path: Y:\MIS_DATABASE\Library\ALTIUM_TOOL\SCHEMATICS_PARTS\MS_DISCRETE_Library.schlib; Mfr_name: PANASONIC-ECG; Mfr_part_number: ERJ-2GEJ330X; Mistral Part No: 110009030699-R; Package: 0402; Part_type: RESISTORS\FIXED; Project: RED EYE; RoHS: RoHS; Temperature: -55°C+155°C; Tolerance: 5%; Voltage: NA; Wattage: 1/10W; Weight: 0.8mg; Datasheet: Y:\MIS_DATABASE\DATASHEETS\RESISTORS\PAN-ERJSER_NOV17.PDF
R171 R174 = RESISTOR: RES 59E 1/10W 1% 0402; Chkd/date: MAZHAR/151208; Crtd /date: USMAN/031208; Custom_Duty: 15%; Customs_HS_Code: 85332119; Distributor_name: DIGIKEY; Distributor_part_number: P59.0LCT-ND; Footprint Path: Y:\MIS_DATABASE\Library\ALTIUM_TOOL\PCB_FOOTPRINTS\Altium_Footprint_Lib.PcbLib; Height: 0.40MM; Library Path: Y:\MIS_DATABASE\Library\ALTIUM_TOOL\SCHEMATICS_PARTS\MS_DISCRETE_Library.schlib; Mfr_name: PANASONIC-ECG; Mfr_part_number: ERJ-2RKF59R0X; Mistral Part No: 110009031010-R; Package: 0402; Part_type: RESISTORS\FIXED; Project: KHAN_HSST; RoHS: RoHS; Temperature: -55°C+155°C; Tolerance: 1%; Voltage: NA; Wattage: 1/10W; Weight: 0.8mg; Datasheet: Y:\MIS_DATABASE\DATASHEETS\RESISTORS\PAN-ERJSER_NOV17.PDF
R204 R389-R393 R395 = RESISTOR: RES 10K 1/16W 5% 0402; Chkd/date: VASANTHA/061216; Crtd /date: MAZHAR/230805; Custom_Duty: 15%; Customs_HS_Code: 85332119; Distributor_name: DIGIKEY; Distributor_part_number: 311-10KJRCT-ND; Footprint Path: Y:\MIS_DATABASE\Library\ALTIUM_TOOL\PCB_FOOTPRINTS\Altium_Footprint_Lib.PcbLib; Height: 0.40MM; Library Path: Y:\MIS_DATABASE\Library\ALTIUM_TOOL\SCHEMATICS_PARTS\MS_DISCRETE_Library.schlib; Mfr_name: YAGEO AMERICA; Mfr_part_number: RC0402JR-0710KL; Mistral Part No: 110011060021-R; Package: 0402; Part_type: RESISTORS\FIXED; Project: HSE; RoHS: RoHS; Temperature: -55°C+155°C; Tolerance: 5%; Voltage: NA; Wattage: 1/16W; Weight: 0.65mg; Datasheet: Y:\MIS_DATABASE\DATASHEETS\RESISTORS\RCXXXXL-SER_MAR18.PDF
U29 = TCAN1043DQ1_SOIC14: IC AUTOMOTIVE LOW-POWER FAULT PROTECTED CAN FD TRANSCEIVER WITH SLEEP MODE TSOT23-14; Chkd/date: ALVY/140422; Crtd /date: ALVY/140422; Custom_Duty: 15%; Customs_HS_Code: 85423100; Distributor_name: NA; Distributor_part_number: NA; Footprint Path: Y:\MIS_DATABASE\Library\ALTIUM_TOOL\PCB_FOOTPRINTS\Altium_Footprint_Lib.PcbLib; Height: 1.10MM; Library Path: Y:\MIS_DATABASE\Library\ALTIUM_TOOL\SCHEMATICS_PARTS\MS_TELECOM_Library.schlib; Mfr_name: TEXAS INSTRUMENTS; Mistral Part No: 143022040001-R; Package: TSOT23-14; Part_type: ICS\TELECOM\TRANSCEIVER; Project: TI_AM62A SVB_BRD; RoHS: NA; Temperature: -40°C+150°C; Tolerance: NA; Voltage: NA; Wattage: NA; Weight: NA; Datasheet: Y:\MIS_DATABASE\DATASHEETS\ICS\TELECOM\TCAN1043-Q1.PDF
U33 = SN74CB3Q3257PWR_TSSOP16: IC 4BIT 1-OF-2 FET MULTIPLEXER/DEMULTIPLEXER TSSOP16; Chkd/date: SUHAS/251010; Crtd /date: USMAN/060109; Custom_Duty: 15%; Customs_HS_Code: 85423100; Distributor_name: DIGIKEY; Distributor_part_number: 296-19138-1-ND; Height: 1.20MM; Mfr_name: TEXAS INSTRUMENTS; Mistral Part No: 141009030117-R; Package: TSSOP16; Part_type: ICS\DIGITAL\COMBINATIONAL; Project: OMAP_EVM; RoHS: Sb/ Br FREE; Temperature: -40°C+85°C; Datasheet: Y:\MIS_DATABASE\DATASHEETS\ICS\DIGITAL\COMBINATIONAL\SN74CB3Q3257.PDF
C276 = CAP: CAP CERAMIC 0.1uF 50V 10% X7R 0402; Chkd/date: MANIRAJA/261020; Crtd /date: ALVY/211020; Custom_Duty: 15%; Customs_HS_Code: 85322990; Distributor_name: DIGIKEY; Distributor_part_number: 490-10700-1-ND; Footprint Path: Y:\MIS_DATABASE\Library\ALTIUM_TOOL\PCB_FOOTPRINTS\Altium_Footprint_Lib.PcbLib; Height: 0.55MM; Library Path: Y:\MIS_DATABASE\Library\ALTIUM_TOOL\SCHEMATICS_PARTS\MS_DISCRETE_Library.schlib; Mfr_name: MURATA; Mfr_part_number: GRM155R71H104KE14D; Mistral Part No: 120011100014-R; Package: 0402; Part_type: CAPACITORS\CERAMIC; Project: J7_CP; RoHS: RoHS; Temperature: -55°C+125°C; Tolerance: 10%; Voltage: 50V; Wattage: NA; Weight: 3.1mg; Datasheet: Y:\MIS_DATABASE\DATASHEETS\CAPACITORS\GRM155R71H104KE14.PDF
LD11-LD18 = DIODE_LED: DIODE LED BRIGHT GREEN SMD; Chkd/date: MANIRAJA/180820; Crtd /date: ALVY/180820; Custom_Duty: 24%; Customs_HS_Code: 85439000; Distributor_name: DIGIKEY; Distributor_part_number: 732-4986-1-ND; Footprint Path: Y:\MIS_DATABASE\Library\ALTIUM_TOOL\PCB_FOOTPRINTS\Altium_Footprint_Lib.PcbLib; Height: 0.80MM; Library Path: Y:\MIS_DATABASE\Library\ALTIUM_TOOL\SCHEMATICS_PARTS\MS_OPTO_Library.schlib; Mfr_name: WURTH ELECTRONICS; Mistral Part No: 130020080012-R; Package: SMD; Part_type: OPTO\LED; Project: AM64x_EVM_BRD; RoHS: RoHS; Temperature: -40°C+85°C; Tolerance: NA; Voltage: NA; Wattage: NA; Weight: 10mg; Datasheet: Y:\MIS_DATABASE\DATASHEETS\DISCRETES\LEDS\150080VS75000.PDF
R381-R388 = RESISTOR: RES 220E 1/10W 5% 0402; Chkd/date: VASANTHA/291216; Crtd /date: GEETHA/260406; Custom_Duty: 15%; Customs_HS_Code: 85332119; Distributor_name: DIGIKEY; Distributor_part_number: P220JCT-ND; Footprint Path: Y:\MIS_DATABASE\Library\ALTIUM_TOOL\PCB_FOOTPRINTS\Altium_Footprint_Lib.PcbLib; Height: 0.40MM; Library Path: Y:\MIS_DATABASE\Library\ALTIUM_TOOL\SCHEMATICS_PARTS\MS_DISCRETE_Library.schlib; Mfr_name: PANASONIC-ECG; Mfr_part_number: ERJ-2GEJ221X; Mistral Part No: 110009030506-R; Package: 0402; Part_type: RESISTORS\FIXED; Project: RED EYE; RoHS: RoHS; Temperature: -55°C+155°C; Tolerance: 5%; Voltage: NA; Wattage: 1/10W; Weight: 0.8mg; Datasheet: Y:\MIS_DATABASE\DATASHEETS\RESISTORS\PAN-ERJSER_NOV17.PDF
R436 R437 = RESISTOR: RES 2.2K 1/10W 5% 0402; Chkd/date: SHREESHAIL/210406; Crtd /date: GEETHA/200406; Custom_Duty: 15%; Customs_HS_Code: 85332119; Distributor_name: DIGIKEY; Distributor_part_number: P2.2KJCT-ND; Footprint Path: Y:\MIS_DATABASE\Library\ALTIUM_TOOL\PCB_FOOTPRINTS\Altium_Footprint_Lib.PcbLib; Height: 0.40MM; Library Path: Y:\MIS_DATABASE\Library\ALTIUM_TOOL\SCHEMATICS_PARTS\MS_DISCRETE_Library.schlib; Mfr_name: PANASONIC-ECG; Mfr_part_number: ERJ-2GEJ222X; Mistral Part No: 110009030429-R; Package: 0402; Part_type: RESISTORS\FIXED; Project: RED EYE; RoHS: RoHS; Temperature: -55°C+155°C; Tolerance: 5%; Voltage: NA; Wattage: 1/10W; Weight: 0.8mg; Datasheet: Y:\MIS_DATABASE\DATASHEETS\RESISTORS\PAN-ERJSER_NOV17.PDF
U1 = XAM263P4ASOKFZCZ_BGA324: IC AM263P SoC BGA324; Chkd/date: PRAVEEN/050423; Crtd /date: PRAVEEN/050423; Custom_Duty: 15%; Customs_HS_Code: 85423100; Distributor_name: NA; Distributor_part_number: NA; Footprint Path: Y:\MIS_DATABASE\Library\ALTIUM_TOOL\PCB_FOOTPRINTS\Altium_Footprint_Lib.PcbLib; Height: 1.40MM; MECHANICAL 3D STEP FILE: NA; Mfr_name: NA; Mistral Part No: 141323040001; Package: BGA324; Part_type: ICS\DIGITAL\FPGA; Project: AM263P_CC; RoHS: RoHS; Temperature: NA; Tolerance: NA; Voltage: NA; Wattage: NA; Weight: NA; Datasheet: Y:\MIS_DATABASE\DATASHEETS\ICS\INTERFACE\ZCZ0324A.PDF
U59 = TPIC2810D_SOIC16: IC 8-BIT LED DRIVER WITH I2C INTERFACE SOIC16; Chkd/date: MANIRAJA/230817; Crtd /date: MANIRAJA/220817; Custom_Duty: 15%; Customs_HS_Code: 85423100; Distributor_name: DIGIKEY; Distributor_part_number: 296-13746-5-ND; Height: 1.75MM; Mfr_name: TEXAS INSTRUMENTS; Mistral Part No: 141017080026-R; Package: SOIC16; Part_type: ICS\INTERFACE; Project: TI_MAXIE_CPB; RoHS: RoHS; Temperature: -40°C+125°C; Tolerance: NA; Voltage: NA; Wattage: NA; Weight: NA; Datasheet: Y:\MIS_DATABASE\DATASHEETS\ICS\INTERFACE\TPIC2810D.PDF
U60 = TCA6424ARGJR_QFN32: IC I2C I/O EXPANDER 24B UQFN32; Chkd/date: NAVEED/100715; Crtd /date: NAVEED/100914; Custom_Duty: 15%; Customs_HS_Code: 85423100; Distributor_name: DIGIKEY; Distributor_part_number: 296-27844-1-ND; Height: 0.60MM; Mfr_name: TEXAS INSTRUMENTS; Mistral Part No: 141014090009-R; Package: UQFN32; Part_type: ICS\DIGITAL\BUSTRANSCEIVER; Project: ZK_BIOMETRIC; RoHS: RoHS; Temperature: -40°C+85°C; Weight: NA; Datasheet: Y:\MIS_DATABASE\DATASHEETS\ICS\DIGITAL\BUSTRANSCEIVER\TCA6424AR.PDF

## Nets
DGND: C93.2 C94.2 C95.2 C96.2 C97.2 C98.2 C99.2 C100.2 C174.1 C175.1 C176.2 C188.2 C276.2 C277.2 C278.2 C348.1 J5.2 J21.2 R79.2 R205.2 R206.2 R389.1 R390.1 R391.1 R393.1 U14.1(PGND) U14.11(AGND) U15.2(GND) U15.5(EP) U16.2(GND) U29.2(GND) U33.8(GND) U59.8(~{G}) U59.16(GND) U60.25(GND) U60.33(EP) ; also on sheet 1 2 3 4 6 7 8 9 10 11 15 16 17 24 25 26 27 28 29 30 32 33
VCC2V5_PG: R80.2 R81.1 U14.5(PG) U16.3(ON)
VCC_1V1: C97.1 TP30.1(TP) U15.1(OUT) ; also on sheet 15
VCC_2V5_EN: R78.1 U14.6(EN)
VCC_5V0: C174.2 FB1.2 U29.3(VCC) ; also on sheet 6
VDD_2V5: C94.1 C96.1 L6.2 R77.2 TP29.1(TP) U14.3(VOS) U15.4(IN) ; also on sheet 7 15
VDD_5V0_LDO3: FB1.1 R381.2 R382.2 R383.2 R384.2 R385.2 R386.2 R387.2 R388.2 ; also on sheet 9 30
VDDIO: C100.1 U16.5(QOD) U16.6(VOUT) ; also on sheet 7 15
ADC1_MUX_SEL: U60.15(P16) ; also on sheet 6
ADC2_MUX_SEL: U60.16(P17) ; also on sheet 6
ADC3_MUX_SEL: U60.6(P05) ; also on sheet 2
ADC4_MUX_SEL: U60.7(P06) ; also on sheet 2
ADC5_MUX_SEL: U60.9(P10) ; also on sheet 2
CLK_BUF_EN: U60.2(P01) ; also on sheet 9
ETH_LED1: LD11.1(CATHODE) U59.3(DRAIN0)
ETH_LED2: LD12.1(CATHODE) U59.4(DRAIN1)
ETH_LED3: LD13.1(CATHODE) U59.5(DRAIN2)
ETH_LED4: LD14.1(CATHODE) U59.6(DRAIN3)
ETH_LED5: LD15.1(CATHODE) U59.11(DRAIN4)
ETH_LED6: LD16.1(CATHODE) U59.12(DRAIN5)
ETH_LED7: LD17.1(CATHODE) U59.13(DRAIN6)
ETH_LED8: LD18.1(CATHODE) U59.14(DRAIN7)
FSI_MUX_OE#: R206.1 U33.15(~{OE})
FSI_MUX_SEL: R204.2 R205.1 U33.1(S) U60.5(P04)
FSIRX2_CLK: U33.6(2B2) ; also on sheet 27
FSIRX2_CLK/MCAN4_TXD: U33.7(2A) ; also on sheet 27
FSIRX2_DATA0: U33.10(3B2) ; also on sheet 27
FSIRX2_DATA0/MCAN5_RXD: U33.9(3A) ; also on sheet 27
FSIRX2_DATA1: U33.13(4B2) ; also on sheet 27
FSIRX2_DATA1/MCAN5_TXD: U33.12(4A) ; also on sheet 27
FSITX2_DATA1: U33.3(1B2) ; also on sheet 27
FSITX2_DATA1/MCAN4_RXD: U33.4(1A) ; also on sheet 27
GPIO_ICSSM1_RST: U1.N18(GPIO35) ; also on sheet 15
GPIO_ICSSM2_RST: U1.M18(GPIO36) ; also on sheet 7
GPIO_OSPI_RSTn: U60.1(P00) ; also on sheet 24
GPIO_uSD_PWR_EN: U60.8(P07) ; also on sheet 25
HSEC_GPIO: U60.17(P20) ; also on sheet 6
HSEC_MCAN5_RX: U33.11(3B1) ; also on sheet 6
HSEC_MCAN5_TX: U33.14(4B1) ; also on sheet 6
I2C0_MUX_SEL: U60.10(P11) ; also on sheet 26
ICSSM0_MUX_SEL: U60.21(P24) ; also on sheet 32
ICSSM1_MUX_SEL: U60.3(P02) ; also on sheet 32
ICSSM2_MUX_SEL: U60.4(P03) ; also on sheet 33
IO_EXP_INTn: R395.1 U60.32(~{INT})
LIN_MUX_SEL: U60.14(P15) ; also on sheet 9
MCAN1_STB: R466.2 U29.14(nSTB) U60.18(P21)
MCAN4_CAN_H: J5.1 R171.1 U29.13(CANH)
MCAN4_CAN_L: J5.3 R174.2 U29.12(CANL)
MCAN4_RX: R173.1 U33.2(1B1)
MCAN4_RX_R: R173.2 U29.4(RxD)
MCAN4_T: C176.1 R171.2 R174.1
MCAN4_TX: R172.2 U33.5(2B1)
MCAN4_TX_R: R172.1 U29.1(TxD)
MCAN_EN: R1647.2 U29.6(EN)
MDIO0_MDC: R436.2 U1.M17(GPIO42) ; also on sheet 7 15
MDIO0_MDIO: R437.2 U1.N16(GPIO41) ; also on sheet 7 15
MDIO/MDC_MUX_SEL1: U60.19(P22) ; also on sheet 15
MDIO/MDC_MUX_SEL2: U60.20(P23) ; also on sheet 7
OSPI/QSPI_MUX_SEL: U1.P16(GPIO37) ; also on sheet 24
PMIC_INTn: U1.R17(GPIO29) ; also on sheet 30
PMIC_WKUP2: J22.1 ; also on sheet 6 30
SOC_I2C2_SCL: U59.15(SCL) U60.29(SCL) ; also on sheet 1 26 28
SOC_I2C2_SDA: U59.2(SDA) U60.30(SDA) ; also on sheet 1 26 28
SPI1_MUX_SEL: U60.11(P12) ; also on sheet 30
TCAN_WAKE: R31.2 U29.9(WAKE)
UART2_MUX_SEL: U60.12(P13) ; also on sheet 26
VMAIN: C93.1 U14.7(PVIN) U14.8(AVIN) ; also on sheet 1 4 10 26 27 29
VMAIN_12V0: C348.2 R175.1 U29.10(VSUP) ; also on sheet 4 30
VPP_LDO_EN: U60.13(P14) ; also on sheet 29
VSYS_3V3_LDO1: C98.1 C175.2 C277.1 C278.1 R78.2 R80.1 R392.2 R395.2 R436.1 R437.1 R466.1 R1647.1 U16.1(VIN) U29.5(VIO) U60.27(VCCP) U60.31(VCC) ; also on sheet 1 6 7 9 10 11 15 16 17 24 26 27 28 29 30 32 33
VSYS_3V3_LDO2: C188.1 C276.1 R204.1 U33.16(VCC) U59.1(VCC) ; also on sheet 1 9 25 26 30
WARMRESETn: R394.1 ; also on sheet 25 27
N32801024: LD11.2(ANODE) R381.1
N32801040: LD12.2(ANODE) R382.1
N32801094: LD13.2(ANODE) R383.1
N32801104: LD14.2(ANODE) R384.1
N32801160: LD15.2(ANODE) R385.1
N32801170: LD16.2(ANODE) R386.1
N32801226: LD17.2(ANODE) R387.1
N32801236: LD18.2(ANODE) R388.1
N32801519: R389.2 U59.9(A0)
N32801526: R390.2 U59.10(A1)
N32801533: R391.2 U59.7(A2)
N32817219: R392.1 R393.2 U60.26(ADDR)
N32817226: R394.2 U60.28(~{RESET})
N32995593: R77.1 R79.1 U14.4(FB)
N32995608: L6.1 U14.2(SW)
N32995634: C95.1 U14.9(SS/TR)
N34781978: R81.2 U15.3(EN)
N34798910: C99.1 U16.4(CT)
N35271296: TP78.1(TP) U29.8(nFAULT)
N35376496: J21.1 R31.1 R175.2
N35387120: R116.1 U29.7(INH)
N35712813: J22.2 R116.2

Not connected (* = marked no-connect by the designer): U14 10(MODE)*; U29 11(NC)*; U60 22(P25)* 23(P26)* 24(P27)*

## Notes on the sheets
sheet 12
- LED Driver
- I2C ADDRESS: 0x60
- IO Expander
- Symbol needs to get updated
- I2C ADDRESS: 0x22
sheet 13
- MCAN Interface
- CAD NOTE: DON'T ROUTE MCAN4_H AND MCAN4_L AS DIFFERENTIAL PAIR
- NOTE: ADD JUMPERS ACROSS J21 & J22 LOCATIONS TO ENABLE PMIC VIA WAKE2 PIN OF PMIC
- 120E
- PCB Silkscreen:
   "MCAN4"
- MCAN AND FSI MUX
- FSI MUX
- SEL
- CONDITION
- FUNCTION
- LOW
- MCAN for CAN & HSEC SELECTED
- A-->B1 port
- HIGH
- FSI SELECTED
- A-->B2 port
sheet 14
- Ethernet Powers
- 2.5V ETHERNET PHY POWER SUPPLY
- 1.1V, 0.5AMPS SUPPLY
- FOR INDUS PHY
- Load Switch
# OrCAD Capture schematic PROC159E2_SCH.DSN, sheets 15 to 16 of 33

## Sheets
15 19. SOC-ICSS DP8386(Indust): size C; title: SOC-ICSS DP8386(Indus)
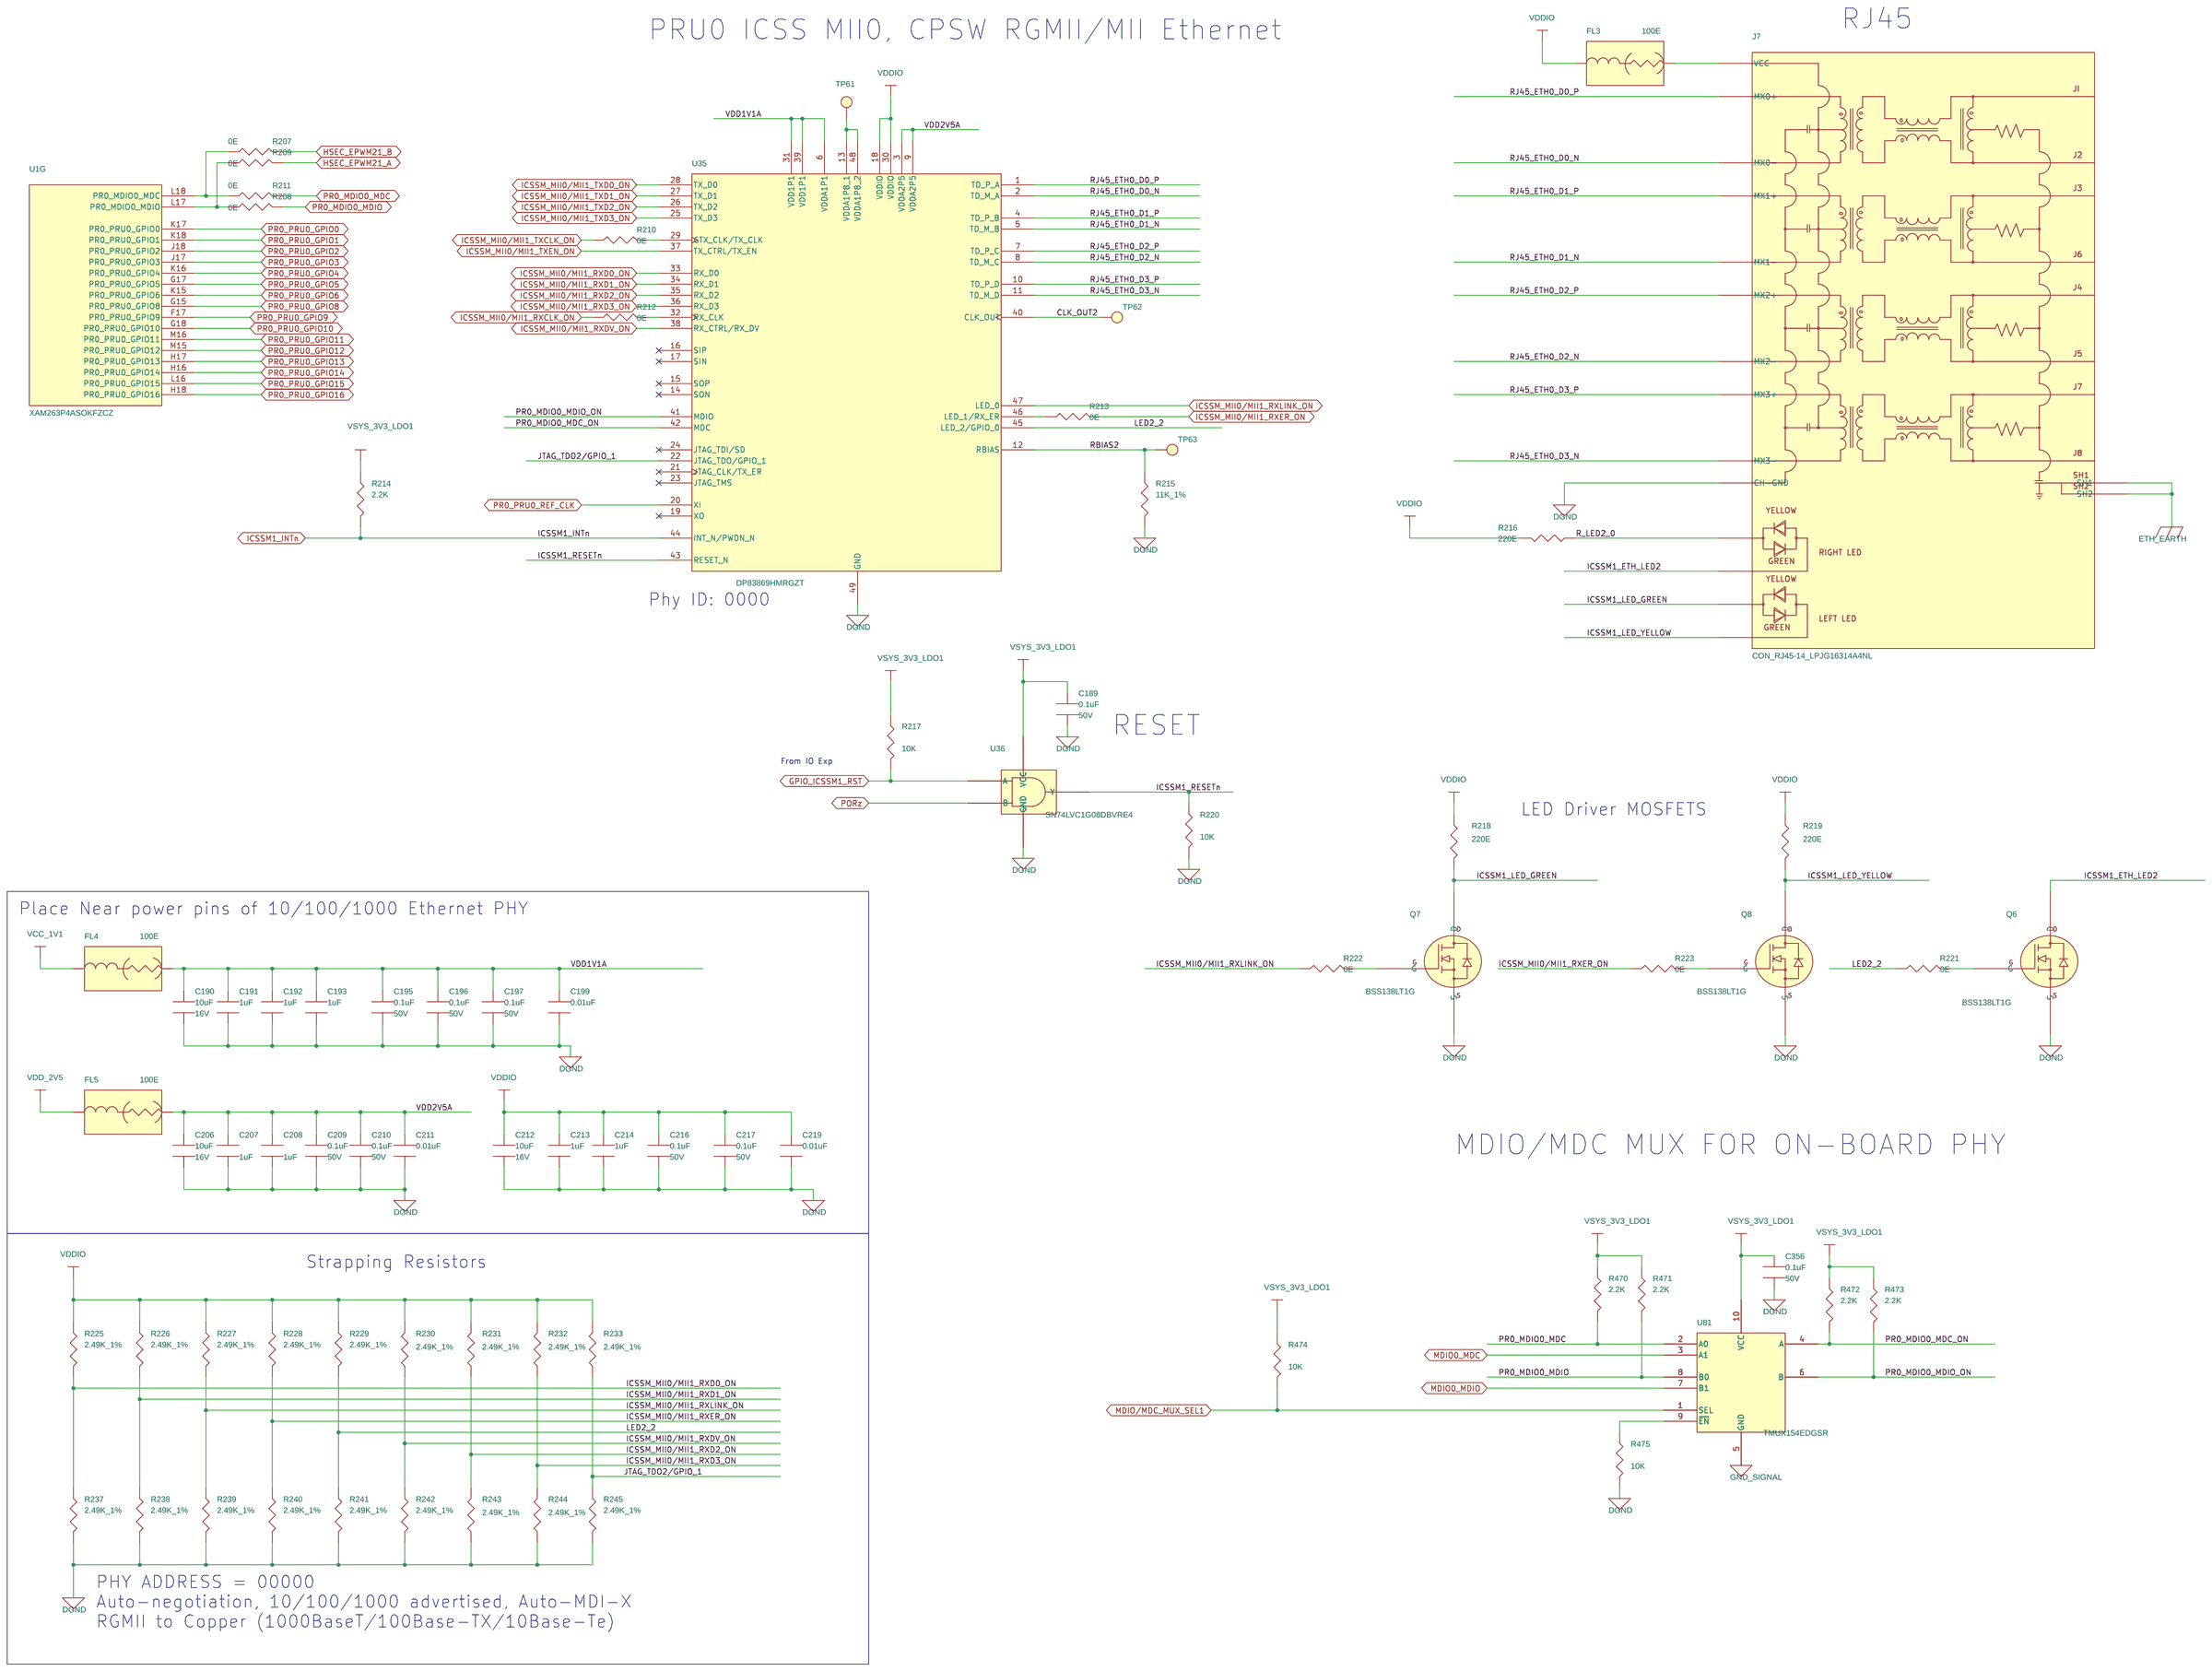
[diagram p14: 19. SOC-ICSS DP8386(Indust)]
16 29. SOC-ADC & DAC INTERFACE: size C; title: SOC-ADC INTERFACE

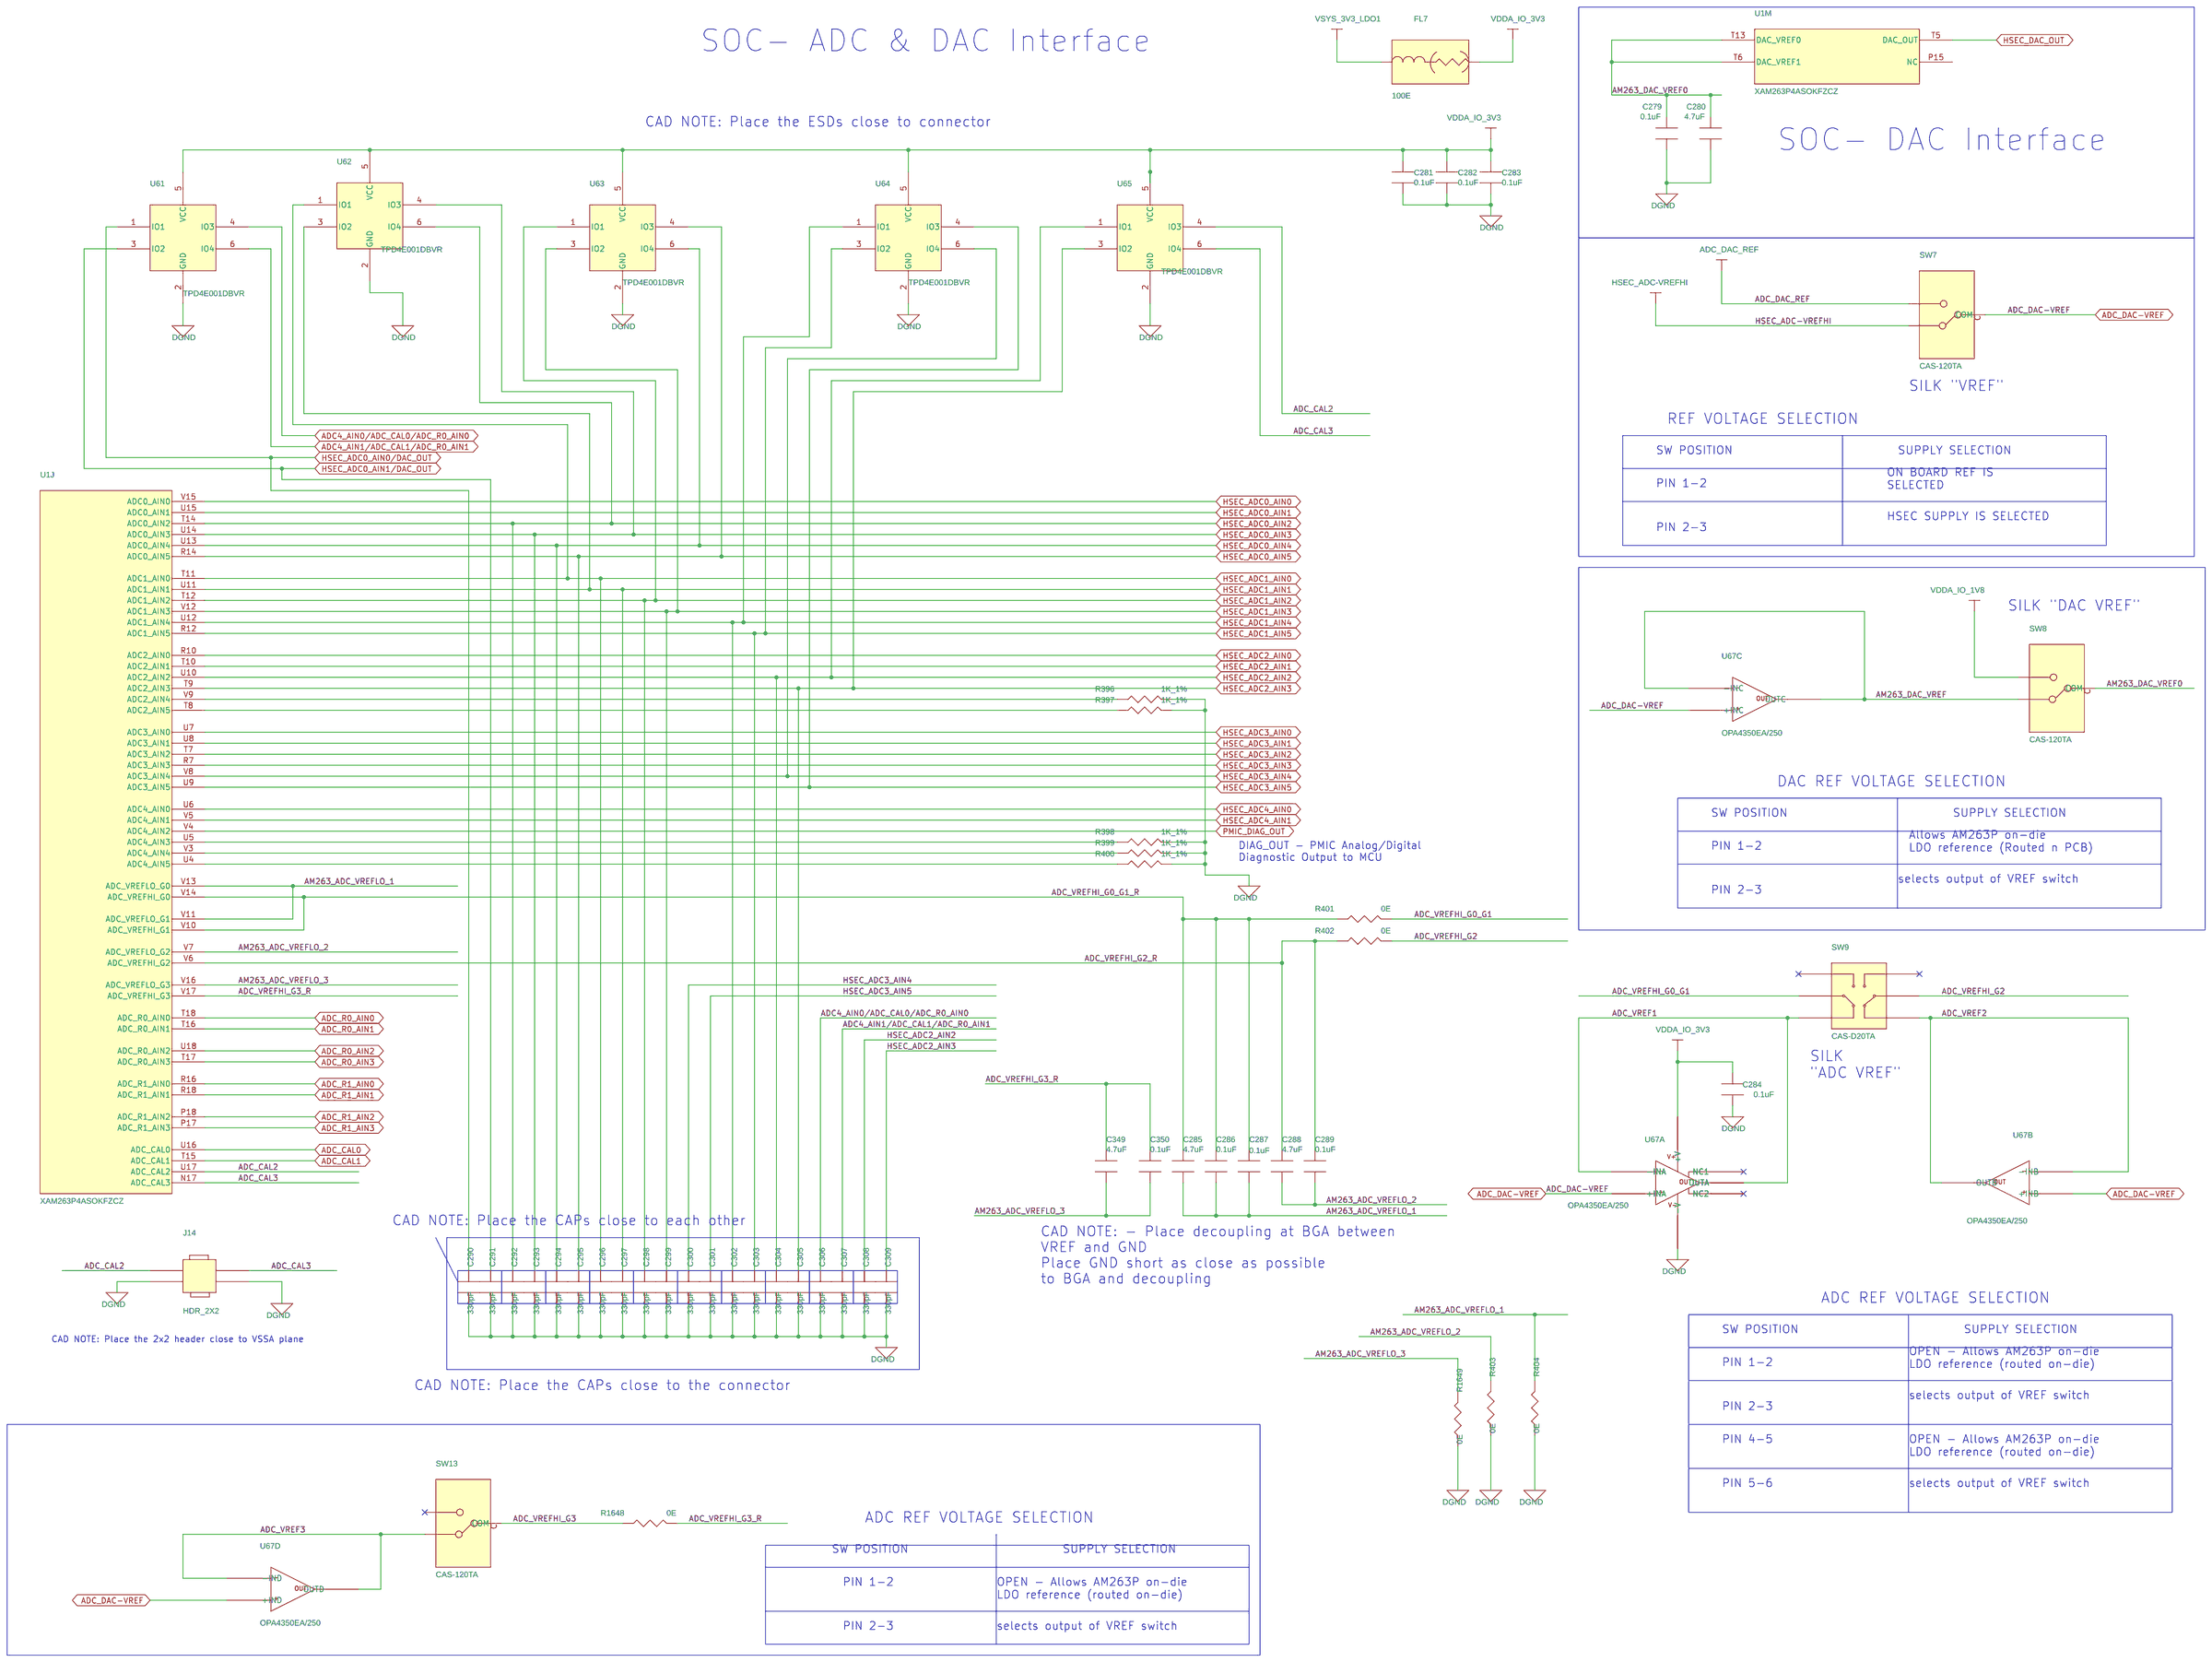
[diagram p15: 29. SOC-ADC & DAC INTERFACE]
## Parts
sheet 19. SOC-ICSS DP8386(Indust)
C189  0.1uF  [CAP0402_0-75]
C190  10uF  [CAP0603_1]
C191  1uF  [CAP0402_0-75]
C192  1uF  [CAP0402_0-75]
C193  1uF  [CAP0402_0-75]
C195  0.1uF  [CAP0402_0-75]
C196  0.1uF  [CAP0402_0-75]
C197  0.1uF  [CAP0402_0-75]
C199  0.01uF  [CAP0402_0-75]
C206  10uF  [CAP0603_1]
C207  1uF  [CAP0402_0-75]
C208  1uF  [CAP0402_0-75]
C209  0.1uF  [CAP0402_0-75]
C210  0.1uF  [CAP0402_0-75]
C211  0.01uF  [CAP0402_0-75]
C212  10uF  [CAP0603_1]
C213  1uF  [CAP0402_0-75]
C214  1uF  [CAP0402_0-75]
C216  0.1uF  [CAP0402_0-75]
C217  0.1uF  [CAP0402_0-75]
C219  0.01uF  [CAP0402_0-75]
C356  0.1uF  [CAP0402_0-75]
FL3  100E  [EMIFIL_BLM18R_0603]
FL4  100E  [EMIFIL_BLM18R_0603]
FL5  100E  [EMIFIL_BLM18R_0603]
J7  CON_RJ45-14_LPJG16314A4NL  [CON_RJ45-14_LPJG16314A4NL_S_R_T_13-6]
Q6  BSS138LT1G  [SOT23-123_1-2]
Q7  BSS138LT1G  [SOT23-123_1-2]
Q8  BSS138LT1G  [SOT23-123_1-2]
R207  0E  [RES0402_0-5]
R208  0E  [RES0402_0-5]
R209  0E  [RES0402_0-5]
R210  0E  [RES0402_0-5]
R211  0E  [RES0402_0-5]
R212  0E  [RES0402_0-5]
R213  0E  [RES0402_0-5]
R214  2.2K  [RES0402_0-5]
R215  11K_1%  [RES0402_0-5]
R216  220E  [RES0402_0-5]
R217  10K  [RES0402_0-5]
R218  220E  [RES0402_0-5]
R219  220E  [RES0402_0-5]
R220  10K  [RES0402_0-5]
R221  0E  [RES0402_0-5]
R222  0E  [RES0402_0-5]
R223  0E  [RES0402_0-5]
R225  2.49K_1%  [RES0402_0-5]
R226  2.49K_1%  [RES0402_0-5]
R227  2.49K_1%  [RES0402_0-5]
R228  2.49K_1%  [RES0402_0-5]
R229  2.49K_1%  [RES0402_0-5]
R230  2.49K_1%  [RES0402_0-5]
R231  2.49K_1%  [RES0402_0-5]
R232  2.49K_1%  [RES0402_0-5]
R233  2.49K_1%  [RES0402_0-5]
R237  2.49K_1%  [RES0402_0-5]
R238  2.49K_1%  [RES0402_0-5]
R239  2.49K_1%  [RES0402_0-5]
R240  2.49K_1%  [RES0402_0-5]
R241  2.49K_1%  [RES0402_0-5]
R242  2.49K_1%  [RES0402_0-5]
R243  2.49K_1%  [RES0402_0-5]
R244  2.49K_1%  [RES0402_0-5]
R245  2.49K_1%  [RES0402_0-5]
R470  2.2K  [RES0402_0-5]
R471  2.2K  [RES0402_0-5]
R472  2.2K  [RES0402_0-5]
R473  2.2K  [RES0402_0-5]
R474  10K  [RES0402_0-5]
R475  10K  [RES0402_0-5]
TP61  TP40_SMD  [TP40_SMD]
TP62  TP40_SMD  [TP40_SMD]
TP63  TP40_SMD  [TP40_SMD]
U35  DP83869HMRGZT  [QFN48_19-68_280X280_1_EP4-2]
U36  SN74LVC1G08DBVRE4  [SOT23-5]
U81  TMUX154EDGSR  [MSOP10_19-68_120X120_1-1]
sheet 28. LED DRIVER AND IO EXPANDER
U1  XAM263P4ASOKFZCZ  [BGA324_31-49_590X590_1-4]  (sections A,B,C,D,E,F,G,H,I,J,K,L,M)
sheet 29. SOC-ADC & DAC INTERFACE
C279  0.1uF  [CAP0402_0-75]
C280  4.7uF  [CAP0402_0-75]
C281  0.1uF  [CAP0402_0-75]
C282  0.1uF  [CAP0402_0-75]
C283  0.1uF  [CAP0402_0-75]
C284  0.1uF  [CAP0402_0-75]
C285  4.7uF  [CAP0402_0-75]
C286  0.1uF  [CAP0201_0-5]
C287  0.1uF  [CAP0201_0-5]
C288  4.7uF  [CAP0402_0-75]
C289  0.1uF  [CAP0201_0-5]
C290  330pF  [CAP0402_0-75]
C291  330pF  [CAP0402_0-75]
C292  330pF  [CAP0402_0-75]
C293  330pF  [CAP0402_0-75]
C294  330pF  [CAP0402_0-75]
C295  330pF  [CAP0402_0-75]
C296  330pF  [CAP0402_0-75]
C297  330pF  [CAP0402_0-75]
C298  330pF  [CAP0402_0-75]
C299  330pF  [CAP0402_0-75]
C300  330pF  [CAP0402_0-75]
C301  330pF  [CAP0402_0-75]
C302  330pF  [CAP0402_0-75]
C303  330pF  [CAP0402_0-75]
C304  330pF  [CAP0402_0-75]
C305  330pF  [CAP0402_0-75]
C306  330pF  [CAP0402_0-75]
C307  330pF  [CAP0402_0-75]
C308  330pF  [CAP0402_0-75]
C309  330pF  [CAP0402_0-75]
C349  4.7uF  [CAP0402_0-75]
C350  0.1uF  [CAP0201_0-5]
FL7  100E  [EMIFIL_BLM18R_0603]
J14  HDR_2X2  [HDR_2X2_5-146256-2_S_T_8-3]
R396  1K_1%  [RES0402_0-5]
R397  1K_1%  [RES0402_0-5]
R398  1K_1%  [RES0402_0-5]
R399  1K_1%  [RES0402_0-5]
R400  1K_1%  [RES0402_0-5]
R401  0E  [RES0402_0-5]
R402  0E  [RES0402_0-5]
R403  0E  [RES0402_0-5]
R404  0E  [RES0402_0-5]
R1648  0E  [RES0402_0-5]
R1649  0E  [RES0402_0-5]
SW7  CAS-120TA  [SW3_CAS-120TA_215X100_SMD]
SW8  CAS-120TA  [SW3_CAS-120TA_215X100_SMD]
SW9  CAS-D20TA  [SW6_CAS-D20A_210X150_SMD]
SW13  CAS-120TA  [SW3_CAS-120TA_215X100_SMD]
U61  TPD4E001DBVR  [SOT23-6]
U62  TPD4E001DBVR  [SOT23-6]
U63  TPD4E001DBVR  [SOT23-6]
U64  TPD4E001DBVR  [SOT23-6]
U65  TPD4E001DBVR  [SOT23-6]
U67  OPA4350EA/250  [QSOP16_25_200X160_1-8]  (sections A,B,C,D)

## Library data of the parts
C189 C356 = CAP: CAP CERAMIC 0.1uF 50V 10% X7R 0402; Automotive Alternate_mfr_name: TDK; Automotive Alternate_mfr_part_number: CGA2B3X7R1H104K050BB; Chkd/date: MANIRAJA/261020; Crtd /date: ALVY/211020; Custom_Duty: 15%; Customs_HS_Code: 85322990; Direct Alternate_mfr_name: TDK; Direct Alternate_mfr_part_number: C1005X7R1H104K050BE; Distributor_name: DIGIKEY; Distributor_part_number: 490-10700-1-ND; Footprint Path: Y:\MIS_DATABASE\Library\ALTIUM_TOOL\PCB_FOOTPRINTS\Altium_Footprint_Lib.PcbLib; Height: 0.55MM; Library Path: Y:\MIS_DATABASE\Library\ALTIUM_TOOL\SCHEMATICS_PARTS\MS_DISCRETE_Library.schlib; Mfr_name: MURATA; Mfr_part_number: GRM155R71H104KE14D; Mistral Part No: 120011100014-R; Package: 0402; Part_type: CAPACITORS\CERAMIC; Project: J7_CP; RoHS: RoHS; Temperature: -55°C+125°C; Tolerance: 10%; Voltage: 50V; Wattage: NA; Weight: 3.1mg; Datasheet: Y:\MIS_DATABASE\DATASHEETS\CAPACITORS\GRM155R71H104KE14.PDF
C190 C206 C212 = CAP: CAP CERAMIC 10uF 16V 20% X6S 0603; Chkd/date: VASANTHA/170117; Crtd /date: VASANTHA/170117; Custom_Duty: 15%; Customs_HS_Code: 85322990; Distributor_name: DIGIKEY; Distributor_part_number: 490-7198-1-ND; Footprint Path: Y:\MIS_DATABASE\Library\ALTIUM_TOOL\PCB_FOOTPRINTS\Altium_Footprint_Lib.PcbLib; Height: 0.90MM; Library Path: Y:\MIS_DATABASE\Library\ALTIUM_TOOL\SCHEMATICS_PARTS\MS_DISCRETE_Library.schlib; Mfr_name: MURATA; Mfr_part_number: GRM188C81C106MA73D; Mistral Part No: 120017010004-R; Package: 0603; Part_type: CAPACITORS\CERAMIC; Project: TRMM_SMART-M_PS; RoHS: RoHS; Temperature: -55°C+105°C; Tolerance: 20%; Voltage: 16V; Wattage: NA; Weight: 6.3mg; Datasheet: Y:\MIS_DATABASE\DATASHEETS\CAPACITORS\MURATA-GXX-SER_NOV17.PDF
C191-C193 C207 C208 C213 C214 = CAP: CAP CERAMIC 1uF 25V 10% X6S 0402; Chkd/date: MANIRAJA/140518; Crtd /date: ALVY/140518; Custom_Duty: 15%; Customs_HS_Code: 85322990; Distributor_name: DIGIKEY; Distributor_part_number: 490-10014-1-ND; Footprint Path: Y:\MIS_DATABASE\Library\ALTIUM_TOOL\PCB_FOOTPRINTS\Altium_Footprint_Lib.PcbLib; Height: 0.60MM; Library Path: Y:\MIS_DATABASE\Library\ALTIUM_TOOL\SCHEMATICS_PARTS\MS_DISCRETE_Library.schlib; Mfr_name: MURATA; Mfr_part_number: GRM155C81E105KE11D; Mistral Part No: 120018050004-R; Package: 0402; Part_type: CAPACITORS\CERAMIC; Project: TI_SVB_MAXWELL_DUT; RoHS: RoHS; Temperature: -55°C+105°C; Tolerance: 10%; Voltage: 25V; Wattage: NA; Weight: 6mg; Datasheet: Y:\MIS_DATABASE\DATASHEETS\CAPACITORS\GRM155C81E105KE11X.PDF
C195-C197 C209 C210 C216 C217 C279 C281-C284 = CAP: CAP CERAMIC 0.1uF 50V 10% X7R 0402; Chkd/date: MANIRAJA/261020; Crtd /date: ALVY/211020; Custom_Duty: 15%; Customs_HS_Code: 85322990; Distributor_name: DIGIKEY; Distributor_part_number: 490-10700-1-ND; Footprint Path: Y:\MIS_DATABASE\Library\ALTIUM_TOOL\PCB_FOOTPRINTS\Altium_Footprint_Lib.PcbLib; Height: 0.55MM; Library Path: Y:\MIS_DATABASE\Library\ALTIUM_TOOL\SCHEMATICS_PARTS\MS_DISCRETE_Library.schlib; Mfr_name: MURATA; Mfr_part_number: GRM155R71H104KE14D; Mistral Part No: 120011100014-R; Package: 0402; Part_type: CAPACITORS\CERAMIC; Project: J7_CP; RoHS: RoHS; Temperature: -55°C+125°C; Tolerance: 10%; Voltage: 50V; Wattage: NA; Weight: 3.1mg; Datasheet: Y:\MIS_DATABASE\DATASHEETS\CAPACITORS\GRM155R71H104KE14.PDF
C199 C211 C219 = CAP: CAP CERAMIC 0.01uF 50V 10% X7R 0402; Chkd/date: MANIRAJA/280319; Crtd /date: MANIRAJA/280319; Custom_Duty: 15%; Customs_HS_Code: 85322990; Distributor_name: DIGIKEY; Distributor_part_number: 490-4516-1-ND; Footprint Path: Y:\MIS_DATABASE\Library\ALTIUM_TOOL\PCB_FOOTPRINTS\Altium_Footprint_Lib.PcbLib; Height: 0.55MM; Library Path: Y:\MIS_DATABASE\Library\ALTIUM_TOOL\SCHEMATICS_PARTS\MS_DISCRETE_Library.schlib; Mfr_name: MURATA; Mfr_part_number: GRM155R71H103KA88D; Mistral Part No: 120009030025-R; Package: 0402; Part_type: CAPACITORS\CERAMIC; Project: G4_SVGA; RoHS: RoHS; Temperature: -55°C+125°C; Tolerance: 10%; Voltage: 50V; Wattage: NA; Weight: 0.65mg; Datasheet: Y:\MIS_DATABASE\DATASHEETS\CAPACITORS\GRM155R71H103KA88D.PDF
FL3-FL5 FL7 = EMIFILTER_IND: PASSIVE FILTER EMI 100E 2A 0603; Chkd/date: BAVISH/170811; Crtd /date: CHAITHANYA/170811; Custom_Duty: 24%; Customs_HS_Code: 85437099; Distributor_name: DIGIKEY; Distributor_part_number: BLM18EG101TN1D-ND; Footprint Path: Y:\MIS_DATABASE\Library\ALTIUM_TOOL\PCB_FOOTPRINTS\Altium_Footprint_Lib.PcbLib; Height: 0.65MM; Library Path: Y:\MIS_DATABASE\Library\ALTIUM_TOOL\SCHEMATICS_PARTS\MS_FILTER_Library.schlib; Mfr_name: MURATA; Mfr_part_number: BLM18EG101TN1D; Mistral Part No: 130011080028-R; Package: 0603; Part_type: FILTER; Project: CPCI3GADC_CARD; RoHS: RoHS; Temperature: -55°C+125°C; Tolerance: NA; Voltage: NA; Wattage: NA; Weight: NA; Datasheet: Y:\MIS_DATABASE\DATASHEETS\DISCRETES\INDUCTORS\BLM18E.PDF
J7 = CON_RJ45-14_LPJG16314A4NL: CON RJ-45 FEMALE 14POS RT TH; Chkd/date: VASANTHA/150714; Crtd /date: BALACHANDAR/120614; Custom_Duty: 24%; Customs_HS_Code: 85369090; Distributor_name: NA; Distributor_part_number: NA; Footprint Path: Y:\MIS_DATABASE\Library\ALTIUM_TOOL\PCB_FOOTPRINTS\Altium_Footprint_Lib.PcbLib; Height: 13.60MM; Library Path: Y:\MIS_DATABASE\Library\ALTIUM_TOOL\SCHEMATICS_PARTS\MS_CONNECTOR_Library.schlib; Mfr_name: LINK-PP; Mfr_part_number: LPJG16314A4NL; Mistral Part No: 150014060029-R; Package: THRU-HOLE; Part_type: CONNECTOR\JACK; Project: AEGIS; RoHS: RoHS; Temperature: -0°C+70°C; Tolerance: NA; Voltage: NA; Wattage: NA; Weight: NA; Datasheet: Y:\MIS_DATABASE\DATASHEETS\CONNECTORS\LPJG16314A4NL.PDF
Q6-Q8 = MOSFET_BSS138W: IC MOSFET N-CHANNEL 50V 200mA SOT23-3; Chkd/date: MANIRAJA/250219; Crtd /date: JEBRAN/060416; Custom_Duty: 15%; Customs_HS_Code: 85423100; Distributor_name: DIGIKEY; Distributor_part_number: BSS138LT1GOSCT-ND; Footprint Path: Y:\MIS_DATABASE\Library\ALTIUM_TOOL\PCB_FOOTPRINTS\Altium_Footprint_Lib.PcbLib; Height: 1.11MM; Library Path: Y:\MIS_DATABASE\Library\ALTIUM_TOOL\SCHEMATICS_PARTS\MS_MOSFET_Library.schlib; Mfr_name: ON SEMICONDUCTOR; Mistral Part No: 142016040001-R; Package: SOT23-3; Part_type: ICS\POWER\MOSFET; Project: LRDE_ABCM; RoHS: RoHS; Temperature: -55°C+150°C; Tolerance: NA; Voltage: NA; Wattage: NA; Weight: 8mg; Datasheet: Y:\MIS_DATABASE\DATASHEETS\DISCRETES\TRANSISTORS_FETS\BSS138LT1G.PDF
R207-R213 R221-R223 R401-R404 R1648 R1649 = RESISTOR: RES 0E 1/10W JUMPER 0402; Chkd/date: VASANTHA/061216; Crtd /date: NAVEED/201014; Custom_Duty: 15%; Customs_HS_Code: 85332119; Distributor_name: DIGIKEY; Distributor_part_number: P0.0JCT-ND; Footprint Path: Y:\MIS_DATABASE\Library\ALTIUM_TOOL\PCB_FOOTPRINTS\Altium_Footprint_Lib.PcbLib; Height: 0.40MM; IBISSP_MODLES: VALUE REPEATING 2 TIME; Library Path: Y:\MIS_DATABASE\Library\ALTIUM_TOOL\SCHEMATICS_PARTS\MS_DISCRETE_Library.schlib; Mfr_name: PANASONIC-ECG; Mfr_part_number: ERJ-2GE0R00X; Mistral Part No: 110018030052-R; Package: 0402; Part_type: RESISTORS\FIXED; Project: AEGIS POM; RoHS: RoHS; Temperature: -55°C+155°C; Tolerance: NA; Voltage: NA; Wattage: 1/10W; Weight: 0.8mg; Datasheet: Y:\MIS_DATABASE\DATASHEETS\RESISTORS\PAN-ERJSER_NOV17.PDF
R214 R470-R473 = RESISTOR: RES 2.2K 1/10W 5% 0402; Chkd/date: SHREESHAIL/210406; Crtd /date: GEETHA/200406; Custom_Duty: 15%; Customs_HS_Code: 85332119; Distributor_name: DIGIKEY; Distributor_part_number: P2.2KJCT-ND; Footprint Path: Y:\MIS_DATABASE\Library\ALTIUM_TOOL\PCB_FOOTPRINTS\Altium_Footprint_Lib.PcbLib; Height: 0.40MM; Library Path: Y:\MIS_DATABASE\Library\ALTIUM_TOOL\SCHEMATICS_PARTS\MS_DISCRETE_Library.schlib; Mfr_name: PANASONIC-ECG; Mfr_part_number: ERJ-2GEJ222X; Mistral Part No: 110009030429-R; Package: 0402; Part_type: RESISTORS\FIXED; Project: RED EYE; RoHS: RoHS; Temperature: -55°C+155°C; Tolerance: 5%; Voltage: NA; Wattage: 1/10W; Weight: 0.8mg; Datasheet: Y:\MIS_DATABASE\DATASHEETS\RESISTORS\PAN-ERJSER_NOV17.PDF
R215 = RESISTOR: RES 11K 1/16W 1% 0402; Chkd/date: VASANTHA/251115; Crtd /date: VASANTHA/251115; Custom_Duty: 15%; Customs_HS_Code: 85332119; Distributor_name: DIGIKEY; Distributor_part_number: 311-11.0KLRCT-ND; Footprint Path: Y:\MIS_DATABASE\Library\ALTIUM_TOOL\PCB_FOOTPRINTS\Altium_Footprint_Lib.PcbLib; Height: 0.40MM; Library Path: Y:\MIS_DATABASE\Library\ALTIUM_TOOL\SCHEMATICS_PARTS\MS_DISCRETE_Library.schlib; Mfr_name: YAGEO AMERICA; Mfr_part_number: RC0402FR-0711KL; Mistral Part No: 110015110012-R; Package: 0402; Part_type: RESISTORS\FIXED; Project: TI_VLAN_SWITCH; RoHS: RoHS; Temperature: -55°C+155°C; Tolerance: 1%; Voltage: NA; Wattage: 1/16W; Weight: 0.65mg; Datasheet: Y:\MIS_DATABASE\DATASHEETS\RESISTORS\RCXXXXL-SER_MAR18.PDF
R216 R218 R219 = RESISTOR: RES 220E 1/10W 5% 0402; Chkd/date: VASANTHA/291216; Crtd /date: GEETHA/260406; Custom_Duty: 15%; Customs_HS_Code: 85332119; Distributor_name: DIGIKEY; Distributor_part_number: P220JCT-ND; Footprint Path: Y:\MIS_DATABASE\Library\ALTIUM_TOOL\PCB_FOOTPRINTS\Altium_Footprint_Lib.PcbLib; Height: 0.40MM; Library Path: Y:\MIS_DATABASE\Library\ALTIUM_TOOL\SCHEMATICS_PARTS\MS_DISCRETE_Library.schlib; Mfr_name: PANASONIC-ECG; Mfr_part_number: ERJ-2GEJ221X; Mistral Part No: 110009030506-R; Package: 0402; Part_type: RESISTORS\FIXED; Project: RED EYE; RoHS: RoHS; Temperature: -55°C+155°C; Tolerance: 5%; Voltage: NA; Wattage: 1/10W; Weight: 0.8mg; Datasheet: Y:\MIS_DATABASE\DATASHEETS\RESISTORS\PAN-ERJSER_NOV17.PDF
R217 R220 R474 R475 = RESISTOR: RES 10K 1/16W 5% 0402; Chkd/date: VASANTHA/061216; Crtd /date: MAZHAR/230805; Custom_Duty: 15%; Customs_HS_Code: 85332119; Distributor_name: DIGIKEY; Distributor_part_number: 311-10KJRCT-ND; Footprint Path: Y:\MIS_DATABASE\Library\ALTIUM_TOOL\PCB_FOOTPRINTS\Altium_Footprint_Lib.PcbLib; Height: 0.40MM; Library Path: Y:\MIS_DATABASE\Library\ALTIUM_TOOL\SCHEMATICS_PARTS\MS_DISCRETE_Library.schlib; Mfr_name: YAGEO AMERICA; Mfr_part_number: RC0402JR-0710KL; Mistral Part No: 110011060021-R; Package: 0402; Part_type: RESISTORS\FIXED; Project: HSE; RoHS: RoHS; Temperature: -55°C+155°C; Tolerance: 5%; Voltage: NA; Wattage: 1/16W; Weight: 0.65mg; Datasheet: Y:\MIS_DATABASE\DATASHEETS\RESISTORS\RCXXXXL-SER_MAR18.PDF
R225-R230 R233 R243 R244 = RESISTOR: RES 2.49K 1/10W 1% 0402; Assembly_Instruction: DNI; Chkd/date: MANIRAJA/270718; Crtd /date: ALVY/270718; Custom_Duty: 15%; Customs_HS_Code: 85332119; Distributor_name: DIGIKEY; Distributor_part_number: P2.49KLCT-ND; Footprint Path: Y:\MIS_DATABASE\Library\ALTIUM_TOOL\PCB_FOOTPRINTS\Altium_Footprint_Lib.PcbLib; Height: 0.40MM; Library Path: Y:\MIS_DATABASE\Library\ALTIUM_TOOL\SCHEMATICS_PARTS\MS_DISCRETE_Library.schlib; Mfr_name: PANASONIC-ECG; Mfr_part_number: ERJ-2RKF2491X; Mistral Part No: 110018070020-R; Package: 0402; Part_type: RESISTORS\FIXED; Project: TI_J7SVB_ETHERNET_AOC; RoHS: RoHS; Temperature: -55°C+155°C; Tolerance: 1%; Voltage: NA; Wattage: 1/10W; Weight: 0.8mg; Datasheet: Y:\MIS_DATABASE\DATASHEETS\RESISTORS\PAN-ERJSER_NOV17.PDF
R231 R232 R237-R242 R245 = RESISTOR: RES 2.49K 1/10W 1% 0402; Chkd/date: MANIRAJA/270718; Crtd /date: ALVY/270718; Custom_Duty: 15%; Customs_HS_Code: 85332119; Distributor_name: DIGIKEY; Distributor_part_number: P2.49KLCT-ND; Footprint Path: Y:\MIS_DATABASE\Library\ALTIUM_TOOL\PCB_FOOTPRINTS\Altium_Footprint_Lib.PcbLib; Height: 0.40MM; Library Path: Y:\MIS_DATABASE\Library\ALTIUM_TOOL\SCHEMATICS_PARTS\MS_DISCRETE_Library.schlib; Mfr_name: PANASONIC-ECG; Mfr_part_number: ERJ-2RKF2491X; Mistral Part No: 110018070020-R; Package: 0402; Part_type: RESISTORS\FIXED; Project: TI_J7SVB_ETHERNET_AOC; RoHS: RoHS; Temperature: -55°C+155°C; Tolerance: 1%; Voltage: NA; Wattage: 1/10W; Weight: 0.8mg; Datasheet: Y:\MIS_DATABASE\DATASHEETS\RESISTORS\PAN-ERJSER_NOV17.PDF
TP61-TP63 = TESTPOINT: TESTPOINT CIR 40 SMD; Chkd/date: MAZHAR/190505; Crtd /date: MAZHAR/190505; Distributor_name: NA; Distributor_part_number: NA; Footprint Path: Y:\MIS_DATABASE\Library\ALTIUM_TOOL\PCB_FOOTPRINTS\Altium_Footprint_Lib.PcbLib; Height: NA; Library Path: Y:\MIS_DATABASE\Library\ALTIUM_TOOL\SCHEMATICS_PARTS\MS_DISCRETE_Library.schlib; MECHANICAL 3D STEP FILE: NA; Mfr_name: LOCAL; Mistral Part No: 130009030933; Package: SMD; Project: RAINIER-3; RoHS: NA; Temperature: NA; Tolerance: NA; Voltage: NA; Wattage: NA; Weight: NA; Datasheet: NA
U35 = DP83869HM_VQFN48: IC ETHERNET TRANSCEIVER 10/100/1000 WITH COPPER AND FIBRE INTERFACE VQFN48; Chkd/date: MANIRAJA/060519; Crtd /date: ALVY/060519; Custom_Duty: 15%; Customs_HS_Code: 85423100; Distributor_name: DIGIKEY; Distributor_part_number: 296-53377-1-ND; Footprint Path: Y:\MIS_DATABASE\Library\ALTIUM_TOOL\PCB_FOOTPRINTS\Altium_Footprint_Lib.PcbLib; Height: 1.00MM; Library Path: Y:\MIS_DATABASE\Library\ALTIUM_TOOL\SCHEMATICS_PARTS\MS_TELECOM_Library.schlib; Mfr_name: TEXAS INSTRUMENTS; Mistral Part No: 143019050002-R; Package: VQFN48; Part_type: ICS\TELECOM\TRANSCEIVER; Project: J7ES_ENET_DP83869HM_EXP; RoHS: RoHS; Temperature: -40°C+125°C; Tolerance: NA; Voltage: NA; Wattage: NA; Weight: NA; Datasheet: Y:\MIS_DATABASE\DATASHEETS\ICS\TELECOM\DP83869HM.PDF
U36 = SN74LVC1G08DBVRE4_SOT23-5: IC SINGLE 2-INPUT POSITIVE AND GATE SOT23-5; Automotive Alternate_mfr_name: TEXAS INSTRUMENTS; Automotive Alternate_mfr_part_number: SN74LVC1G08QDBVRQ1; Chkd/date: SUHAS/221010; Crtd /date: USMAN/151008; Custom_Duty: 15%; Customs_HS_Code: 85423100; Distributor_name: DIGIKEY; Distributor_part_number: SN74LVC1G08DBVRE4-ND; Height: 1.45MM; Mfr_name: TEXAS INSTRUMENTS; Mistral Part No: 141009060026-R; Part_type: ICS\DIGITAL\GATES; Project: KHAN_MAIN; RoHS: Sb/ Br FREE; Temperature: -40°C+85°C; Datasheet: Y:\MIS_DATABASE\DATASHEETS\ICS\DIGITAL\GATES\SN74LVC1G08.PDF
U81 = TMUX154EDGSR_VSSOP10: IC ESD PROTECTED 2-CH 2:1 SWITCH WITH POWERED-OFF PROTECTION VSSOP10; Chkd/date: MANIRAJA/040918; Crtd /date: MANIRAJA/040918; Custom_Duty: 15%; Customs_HS_Code: 85423100; Distributor_name: DIGIKEY; Distributor_part_number: 296-48347-1-ND; Footprint Path: Y:\MIS_DATABASE\Library\ALTIUM_TOOL\PCB_FOOTPRINTS\Altium_Footprint_Lib.PcbLib; Height: 1.10MM; Library Path: Y:\MIS_DATABASE\Library\ALTIUM_TOOL\SCHEMATICS_PARTS\MS_ANALOG-APPLICATION_Library.schlib; Mfr_name: TEXAS INSTRUMENTS; Mistral Part No: 140118090001-R; Package: VSSOP10; Part_type: ICS\ANALOG\SWITCH; Project: DLRL_DFP_ATRUC CARD; RoHS: RoHS; Temperature: -40°C+85°C; Tolerance: NA; Voltage: NA; Wattage: NA; Weight: NA; Datasheet: Y:\MIS_DATABASE\DATASHEETS\ICS\ANALOG\TMUX154EXXX.PDF
U1 = XAM263P4ASOKFZCZ_BGA324: IC AM263P SoC BGA324; Chkd/date: PRAVEEN/050423; Crtd /date: PRAVEEN/050423; Custom_Duty: 15%; Customs_HS_Code: 85423100; Distributor_name: NA; Distributor_part_number: NA; Footprint Path: Y:\MIS_DATABASE\Library\ALTIUM_TOOL\PCB_FOOTPRINTS\Altium_Footprint_Lib.PcbLib; Height: 1.40MM; MECHANICAL 3D STEP FILE: NA; Mfr_name: NA; Mistral Part No: 141323040001; Package: BGA324; Part_type: ICS\DIGITAL\FPGA; Project: AM263P_CC; RoHS: RoHS; Temperature: NA; Tolerance: NA; Voltage: NA; Wattage: NA; Weight: NA; Datasheet: Y:\MIS_DATABASE\DATASHEETS\ICS\INTERFACE\ZCZ0324A.PDF
C280 C285 C288 C349 = CAP: CAP CERAMIC 4.7uF 10V 20% X5R 0402; Chkd/date: MANIRAJA/110718; Crtd /date: ALVY/110718; Custom_Duty: 15%; Customs_HS_Code: 85322990; Distributor_name: DIGIKEY; Distributor_part_number: 490-14306-1-ND; Footprint Path: Y:\MIS_DATABASE\Library\ALTIUM_TOOL\PCB_FOOTPRINTS\Altium_Footprint_Lib.PcbLib; Height: 0.65MM; Library Path: Y:\MIS_DATABASE\Library\ALTIUM_TOOL\SCHEMATICS_PARTS\MS_DISCRETE_Library.schlib; Mfr_name: MURATA; Mfr_part_number: GRM155R61A475MEAAD; Mistral Part No: 120012060002-R; Package: 0402; Part_type: CAPACITORS\CERAMIC; Project: TI_J7SVB_PCIE_ADD-ON-CARD; RoHS: RoHS; Temperature: -55°C+85°C; Tolerance: 20%; Voltage: 10V; Wattage: NA; Weight: 14mg; Datasheet: Y:\MIS_DATABASE\DATASHEETS\CAPACITORS\GRM155R61A475MEAAD.PDF
C286 C287 C289 C350 = CAP: CAP CERAMIC 0.1uF 10V 10% X5R 0201; Chkd/date: VASANTHA/061216; Crtd /date: MUDDU/190810; Custom_Duty: 15%; Customs_HS_Code: 85322990; Distributor_name: DIGIKEY; Distributor_part_number: 490-5881-1-ND; Footprint Path: Y:\MIS_DATABASE\Library\ALTIUM_TOOL\PCB_FOOTPRINTS\Altium_Footprint_Lib.PcbLib; Height: 0.33MM; Library Path: Y:\MIS_DATABASE\Library\ALTIUM_TOOL\SCHEMATICS_PARTS\MS_DISCRETE_Library.schlib; Mfr_name: MURATA; Mfr_part_number: GRM033R61A104KE15D; Mistral Part No: 120009050017-R; Package: 0201; Part_type: CAPACITORS\CERAMIC; Project: PB_BUGBASE; RoHS: RoHS; Temperature: -55°C+85°C; Tolerance: 10%; Voltage: 10V; Wattage: NA; Weight: 0.33mg; Datasheet: Y:\MIS_DATABASE\DATASHEETS\CAPACITORS\MURATA-GXX-SER_NOV17.PDF
C290-C309 = CAP: CAP CERAMIC 330pF 50V 5% C0G(NP0) 0402; Chkd/date: MANIRAJA/130617; Crtd /date: MAZHAR/221206; Custom_Duty: 15%; Customs_HS_Code: 85322990; Distributor_name: DIGIKEY; Distributor_part_number: 490-1295-1-ND; Footprint Path: Y:\MIS_DATABASE\Library\ALTIUM_TOOL\PCB_FOOTPRINTS\Altium_Footprint_Lib.PcbLib; Height: 0.55MM; Library Path: Y:\MIS_DATABASE\Library\ALTIUM_TOOL\SCHEMATICS_PARTS\MS_DISCRETE_Library.schlib; Mfr_name: MURATA; Mfr_part_number: GRM1555C1H331JA01D; Mistral Part No: 120009030375-R; Package: 0402; Part_type: CAPACITORS\CERAMIC; Project: ADR1B; RoHS: RoHS; Temperature: -55°C+125°C; Tolerance: 5%; Voltage: 50V; Wattage: NA; Weight: 6mg; Datasheet: Y:\MIS_DATABASE\DATASHEETS\CAPACITORS\MURATA-GXX-SER_NOV17.PDF
J14 = HEADER_2X2: CON HDR 2X2 2.54MM PITCH ST TH; Chkd/date: MANIRAJA/091117; Crtd /date: MANIRAJA/091117; Custom_Duty: 24%; Customs_HS_Code: 85369090; Distributor_name: DIGIKEY; Distributor_part_number: A121466-ND; Height: 8.21MM; Mfr_name: TE CONNECTIVITY; Mfr_part_number: 5-146256-2; Mistral Part No: 150017110014-R; Package: THRU-HOLE; Part_type: CONNECTOR\HEADERS; Project: TI_SVB_MAXWELL_DUT; RoHS: RoHS; Temperature: -65°C+105°C; Tolerance: NA; Voltage: NA; Wattage: NA; Weight: 299mg; Datasheet: Y:\MIS_DATABASE\DATASHEETS\CONNECTORS\146256-SERIES.PDF
R396-R400 = RESISTOR: RES 1K 1/10W 1% 0402; Chkd/date: VASANTHA/281216; Crtd /date: MAZHAR/150506; Custom_Duty: 15%; Customs_HS_Code: 85332119; Distributor_name: DIGIKEY; Distributor_part_number: P1.00KLCT-ND; Footprint Path: Y:\MIS_DATABASE\Library\ALTIUM_TOOL\PCB_FOOTPRINTS\Altium_Footprint_Lib.PcbLib; Height: 0.40MM; Library Path: Y:\MIS_DATABASE\Library\ALTIUM_TOOL\SCHEMATICS_PARTS\MS_DISCRETE_Library.schlib; Mfr_name: PANASONIC-ECG; Mfr_part_number: ERJ-2RKF1001X; Mistral Part No: 110009030411-R; Package: 0402; Part_type: RESISTORS\FIXED; Project: VOCERA; RoHS: RoHS; Temperature: -55°C+155°C; Tolerance: 1%; Voltage: NA; Wattage: 1/10W; Weight: 0.8mg; Datasheet: Y:\MIS_DATABASE\DATASHEETS\RESISTORS\PAN-ERJSER_NOV17.PDF
SW7 SW8 SW13 = SWTACT_CAS-120TA: SWITCH TACT SPST SMD; Chkd/date: MAZHAR/221108; Crtd /date: USMAN/171008; Custom_Duty: 24%; Customs_HS_Code: 85369090; Distributor_name: DIGIKEY; Distributor_part_number: CAS120JCT-ND; Height: 2.50MM; Mfr_name: COPAL ELECTRONICS; Mistral Part No: 130009030342; Package: SMD; Part_type: ELECTRO-MECHANICAL\SWITCH; Project: SMART VIEW_IP CAMERA; Datasheet: Y:\MIS_DATABASE\DATASHEETS\MISC\SWITCHES\CAS-XX.PDF
SW9 = SWTACT_CAS-D20TA: SWITCH TACT SPDT SMD; Chkd/date: VASANTHA/281215; Crtd /date: VASANTHA/281215; Custom_Duty: 24%; Customs_HS_Code: 85369090; Distributor_name: DIGIKEY; Distributor_part_number: CASD20JCT-ND; Height: 2.50MM; Mfr_name: COPAL ELECTRONICS; Mistral Part No: 130015120021-R; Package: SMD; Part_type: ELECTRO-MECHANICAL\SWITCH; Project: TI_VLAN_SWITCH; RoHS: RoHS; Temperature: -40°C+85°C; Tolerance: NA; Voltage: NA; Wattage: NA; Weight: NA; Datasheet: Y:\MIS_DATABASE\DATASHEETS\MISC\SWITCHES\CAS-XX.PDF
U61-U65 = TPD4E001_SOT23-6: IC 4CH ESD-PROTECTION ARRAY SOT23-6; Chkd/date: USMAN/250112; Crtd /date: CHAITHANYA/190112; Custom_Duty: 15%; Customs_HS_Code: 85423100; Distributor_name: DIGIKEY; Distributor_part_number: 296-28203-1-ND; Height: 1.60MM; Mfr_name: TEXAS INSTRUMENTS; Mistral Part No: 141012010005-R; Part_type: ICS\INTERFACE; Project: DM385EVM_BASE-BOARD; RoHS: RoHS; Temperature: NA; Tolerance: NA; Voltage: NA; Wattage: NA; Weight: NA; Datasheet: Y:\MIS_DATABASE\DATASHEETS\ICS\INTERFACE\TPD4E001-SER.PDF
U67 = OPA4350EA_SSOP16: IC HIGH-SPEED RAIL-TO-RAIL OPERATIONAL AMPLIFIERS MICROAMPLIFIER SERIES SSOP16; Crtd /date: ALVY/190321; Custom_Duty: 15%; Customs_HS_Code: 85423100; Distributor_name: DIGIKEY; Distributor_part_number: OPA4350EACT-ND; Footprint Path: Y:\MIS_DATABASE\Library\ALTIUM_TOOL\PCB_FOOTPRINTS\Altium_Footprint_Lib.PcbLib; Height: 1.75MM; Library Path: Y:\MIS_DATABASE\Library\ALTIUM_TOOL\SCHEMATICS_PARTS\MS_OPAMP_Library.schlib; Mfr_name: TEXAS INSTRUMENTS; Mistral Part No: 140121030011-R; Package: SSOP16; Part_type: ICS\ANALOG\OPAMP; Project: TI_AM263x_CC; RoHS: RoHS; Temperature: -40°C+85°C; Tolerance: NA; Voltage: NA; Wattage: NA; Weight: 73.8mg; Datasheet: Y:\MIS_DATABASE\DATASHEETS\ICS\OPAMP\OPAX350.PDF

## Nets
DGND: C189.2 C190.2 C191.2 C192.2 C193.2 C195.2 C196.2 C197.2 C199.2 C206.2 C207.2 C208.2 C209.2 C210.2 C211.2 C212.2 C213.2 C214.2 C216.2 C217.2 C219.2 C279.2 C280.2 C281.2 C282.2 C283.2 C284.2 C290.2 C291.2 C292.2 C293.2 C294.2 C295.2 C296.2 C297.2 C298.2 C299.2 C300.2 C301.2 C302.2 C303.2 C304.2 C305.2 C306.2 C307.2 C308.2 C309.2 C356.2 J7.1(CH-GND) J14.3 J14.4 Q6.2(S) Q7.2(S) Q8.2(S) R215.2 R220.1 R237.2 R238.2 R239.2 R240.2 R241.2 R242.2 R243.1 R244.1 R245.2 R396.2 R397.2 R398.2 R399.2 R400.2 R403.1 R404.1 R475.1 R1649.1 U35.49(GND) U36.3(GND) U61.2(GND) U62.2(GND) U63.2(GND) U64.2(GND) U65.2(GND) U67.13(-V) U81.5(GND) ; also on sheet 1 2 3 4 6 7 8 9 10 11 12 13 14 17 24 25 26 27 28 29 30 32 33
VCC_1V1: FL4.1 ; also on sheet 14
VCC_1V8_LDO4: SW7.1 ; also on sheet 30
VDD1V1A: C190.1 C191.1 C192.1 C193.1 C195.1 C196.1 C197.1 C199.1 FL4.2 U35.6(VDDA1P1) U35.31(VDD1P1) U35.39(VDD1P1)
VDD2V5A: C206.1 C207.1 C208.1 C209.1 C210.1 C211.1 FL5.2 U35.3(VDDA2P5) U35.9(VDDA2P5)
VDD_2V5: FL5.1 ; also on sheet 7 14
VDDA_IO_1V8: SW8.1 ; also on sheet 8
VDDA_IO_3V3: C281.1 C282.1 C283.1 C284.1 FL7.2 U61.5(VCC) U62.5(VCC) U63.5(VCC) U64.5(VCC) U65.5(VCC) U67.4(+V) ; also on sheet 2 6
VDDIO: C212.1 C213.1 C214.1 C216.1 C217.1 C219.1 FL3.1 R216.2 R218.1 R219.1 R225.1 R226.1 R227.1 R228.1 R229.1 R230.2 R231.2 R232.2 R233.2 U35.18(VDDIO) U35.30(VDDIO) ; also on sheet 7 14
ADC4_AIN0/ADC_CAL0/ADC_R0_AIN0: C306.1 U61.4(IO3) ; also on sheet 6
ADC4_AIN1/ADC_CAL1/ADC_R0_AIN1: C307.1 U61.6(IO4) ; also on sheet 6
ADC_CAL0: U1.U16(ADC_CAL0) ; also on sheet 2
ADC_CAL1: U1.T15(ADC_CAL1) ; also on sheet 2
ADC_CAL2: J14.1 U1.U17(ADC_CAL2) U65.4(IO3)
ADC_CAL3: J14.2 U1.N17(ADC_CAL3) U65.6(IO4)
ADC_DAC-VREF: SW7.2(COM) U67.3(+INA) U67.5(+INB) U67.12(+INC) U67.14(+IND)
ADC_R0_AIN0: U1.T18(ADC_R0_AIN0) ; also on sheet 2
ADC_R0_AIN1: U1.T16(ADC_R0_AIN1) ; also on sheet 2
ADC_R0_AIN2: U1.U18(ADC_R0_AIN2) ; also on sheet 2
ADC_R0_AIN3: U1.T17(ADC_R0_AIN3) ; also on sheet 2
ADC_R1_AIN0: U1.R16(ADC_R1_AIN0) ; also on sheet 2
ADC_R1_AIN1: U1.R18(ADC_R1_AIN1) ; also on sheet 2
ADC_R1_AIN2: U1.P18(ADC_R1_AIN2) ; also on sheet 2
ADC_R1_AIN3: U1.P17(ADC_R1_AIN3) ; also on sheet 2
ADC_VREF1: SW9.3 U67.1(OUTA) U67.2(-INA)
ADC_VREF2: SW9.6 U67.6(-INB) U67.7(OUTB)
ADC_VREF3: SW13.3 U67.15(-IND) U67.16(OUTD)
ADC_VREFHI_G0_G1: R401.2 SW9.2
ADC_VREFHI_G0_G1_R: C285.1 C286.1 C287.1 R401.1 U1.V10(ADC_VREFHI_G1) U1.V14(ADC_VREFHI_G0)
ADC_VREFHI_G2: R402.2 SW9.5
ADC_VREFHI_G2_R: C288.1 C289.1 R402.1 U1.V6(ADC_VREFHI_G2)
ADC_VREFHI_G3: R1648.1 SW13.2(COM)
ADC_VREFHI_G3_R: C349.1 C350.1 R1648.2 U1.V17(ADC_VREFHI_G3)
AM263_ADC_VREFLO_1: C285.2 C286.2 C287.2 R404.2 U1.V11(ADC_VREFLO_G1) U1.V13(ADC_VREFLO_G0)
AM263_ADC_VREFLO_2: C288.2 C289.2 R403.2 U1.V7(ADC_VREFLO_G2)
AM263_ADC_VREFLO_3: C349.2 C350.2 R1649.2 U1.V16(ADC_VREFLO_G3)
AM263_DAC_VREF: SW8.3 U67.10(OUTC) U67.11(-INC)
AM263_DAC_VREF0: C279.1 C280.1 SW8.2(COM) U1.T6(DAC_VREF1) U1.T13(DAC_VREF0)
CLK_OUT2: TP62.1(TP) U35.40(CLK_OUT)
ETH_EARTH: J7.15(SH1) J7.16(SH2)
GPIO_ICSSM1_RST: R217.1 U36.1(A) ; also on sheet 12
HSEC_ADC0_AIN0: U1.V15(ADC0_AIN0) ; also on sheet 6
HSEC_ADC0_AIN0/DAC_OUT: C290.1 U61.1(IO1) ; also on sheet 6
HSEC_ADC0_AIN1: U1.U15(ADC0_AIN1) ; also on sheet 6
HSEC_ADC0_AIN1/DAC_OUT: C291.1 U61.3(IO2) ; also on sheet 6
HSEC_ADC0_AIN2: C292.1 U1.T14(ADC0_AIN2) U62.6(IO4) ; also on sheet 6
HSEC_ADC0_AIN3: C293.1 U1.U14(ADC0_AIN3) U62.4(IO3) ; also on sheet 6
HSEC_ADC0_AIN4: C294.1 U1.U13(ADC0_AIN4) U63.6(IO4) ; also on sheet 6
HSEC_ADC0_AIN5: C295.1 U1.R14(ADC0_AIN5) U63.4(IO3) ; also on sheet 6
HSEC_ADC1_AIN0: C296.1 U1.T11(ADC1_AIN0) U62.1(IO1) ; also on sheet 6
HSEC_ADC1_AIN1: C297.1 U1.U11(ADC1_AIN1) U62.3(IO2) ; also on sheet 6
HSEC_ADC1_AIN2: C298.1 U1.T12(ADC1_AIN2) U63.1(IO1) ; also on sheet 6
HSEC_ADC1_AIN3: C299.1 U1.V12(ADC1_AIN3) U63.3(IO2) ; also on sheet 6
HSEC_ADC1_AIN4: C302.1 U1.U12(ADC1_AIN4) U64.1(IO1) ; also on sheet 6
HSEC_ADC1_AIN5: C303.1 U1.R12(ADC1_AIN5) U64.3(IO2) ; also on sheet 6
HSEC_ADC2_AIN0: U1.R10(ADC2_AIN0) ; also on sheet 2
HSEC_ADC2_AIN1: U1.T10(ADC2_AIN1) ; also on sheet 2
HSEC_ADC2_AIN2: C304.1 C308.1 U1.U10(ADC2_AIN2) U65.1(IO1) ; also on sheet 6
HSEC_ADC2_AIN3: C305.1 C309.1 U1.T9(ADC2_AIN3) U65.3(IO2) ; also on sheet 6
HSEC_ADC3_AIN0: U1.U7(ADC3_AIN0) ; also on sheet 2
HSEC_ADC3_AIN1: U1.U8(ADC3_AIN1) ; also on sheet 2
HSEC_ADC3_AIN2: U1.T7(ADC3_AIN2) ; also on sheet 2
HSEC_ADC3_AIN3: U1.R7(ADC3_AIN3) ; also on sheet 2
HSEC_ADC3_AIN4: C300.1 U1.V8(ADC3_AIN4) U64.6(IO4) ; also on sheet 6
HSEC_ADC3_AIN5: C301.1 U1.U9(ADC3_AIN5) U64.4(IO3) ; also on sheet 6
HSEC_ADC4_AIN0: U1.U6(ADC4_AIN0) ; also on sheet 6
HSEC_ADC4_AIN1: U1.V5(ADC4_AIN1) ; also on sheet 6
HSEC_ADC-VREFHI: SW7.3 ; also on sheet 6
HSEC_DAC_OUT: U1.T5(DAC_OUT) ; also on sheet 6
HSEC_EPWM21_A: R209.2 ; also on sheet 6
HSEC_EPWM21_B: R207.2 ; also on sheet 6
ICSSM1_ETH_LED2: J7.12 Q6.3(D)
ICSSM1_INTn: R214.2 U35.44(INT_N/PWDN_N) ; also on sheet 27
ICSSM1_LED_GREEN: J7.13 Q7.3(D) R218.2
ICSSM1_LED_YELLOW: J7.14 Q8.3(D) R219.2
ICSSM1_RESETn: R220.2 U35.43(RESET_N) U36.4(Y)
ICSSM_MII0/MII1_RXCLK_ON: R212.1 ; also on sheet 33
ICSSM_MII0/MII1_RXD0_ON: R225.2 R237.1 U35.33(RX_D0) ; also on sheet 33
ICSSM_MII0/MII1_RXD1_ON: R226.2 R238.1 U35.34(RX_D1) ; also on sheet 33
ICSSM_MII0/MII1_RXD2_ON: R231.1 R243.2 U35.35(RX_D2) ; also on sheet 33
ICSSM_MII0/MII1_RXD3_ON: R232.1 R244.2 U35.36(RX_D3) ; also on sheet 33
ICSSM_MII0/MII1_RXDV_ON: R230.1 R242.1 U35.38(RX_CTRL/RX_DV) ; also on sheet 33
ICSSM_MII0/MII1_RXER_ON: R213.2 R223.1 R228.2 R240.1 ; also on sheet 33
ICSSM_MII0/MII1_RXLINK_ON: R222.1 R227.2 R239.1 U35.47(LED_0) ; also on sheet 33
ICSSM_MII0/MII1_TXCLK_ON: R210.1 ; also on sheet 33
ICSSM_MII0/MII1_TXD0_ON: U35.28(TX_D0) ; also on sheet 33
ICSSM_MII0/MII1_TXD1_ON: U35.27(TX_D1) ; also on sheet 33
ICSSM_MII0/MII1_TXD2_ON: U35.26(TX_D2) ; also on sheet 33
ICSSM_MII0/MII1_TXD3_ON: U35.25(TX_D3) ; also on sheet 33
ICSSM_MII0/MII1_TXEN_ON: U35.37(TX_CTRL/TX_EN) ; also on sheet 33
JTAG_TDO2/GPIO_1: R233.1 R245.1 U35.22(JTAG_TDO/GPIO_1)
LED2_2: R221.1 R229.2 R241.1 U35.45(LED_2/GPIO_0)
MDIO0_MDC: U81.3(A1) ; also on sheet 7 12
MDIO0_MDIO: U81.7(B1) ; also on sheet 7 12
MDIO/MDC_MUX_SEL1: R474.1 U81.1(SEL) ; also on sheet 12
PMIC_DIAG_OUT: U1.V4(ADC4_AIN2) ; also on sheet 30
PORZ: U36.2(B) ; also on sheet 6 7 10 11 24 27
PR0_MDIO0_MDC: R211.2 R470.2 U81.2(A0) ; also on sheet 7
PR0_MDIO0_MDC_ON: R472.2 U35.42(MDC) U81.4(A)
PR0_MDIO0_MDIO: R208.2 R471.2 U81.8(B0) ; also on sheet 7
PR0_MDIO0_MDIO_ON: R473.2 U35.41(MDIO) U81.6(B)
PR0_PRU0_GPIO0: U1.K17(PR0_PRU0_GPIO0) ; also on sheet 32
PR0_PRU0_GPIO1: U1.K18(PR0_PRU0_GPIO1) ; also on sheet 32
PR0_PRU0_GPIO2: U1.J18(PR0_PRU0_GPIO2) ; also on sheet 32
PR0_PRU0_GPIO3: U1.J17(PR0_PRU0_GPIO3) ; also on sheet 32
PR0_PRU0_GPIO4: U1.K16(PR0_PRU0_GPIO4) ; also on sheet 32
PR0_PRU0_GPIO5: U1.G17(PR0_PRU0_GPIO5) ; also on sheet 32
PR0_PRU0_GPIO6: U1.K15(PR0_PRU0_GPIO6) ; also on sheet 32
PR0_PRU0_GPIO8: U1.G15(PR0_PRU0_GPIO8) ; also on sheet 32
PR0_PRU0_GPIO9: U1.F17(PR0_PRU0_GPIO9) ; also on sheet 32
PR0_PRU0_GPIO10: U1.G18(PR0_PRU0_GPIO10) ; also on sheet 32
PR0_PRU0_GPIO11: U1.M16(PR0_PRU0_GPIO11) ; also on sheet 32
PR0_PRU0_GPIO12: U1.M15(PR0_PRU0_GPIO12) ; also on sheet 32
PR0_PRU0_GPIO13: U1.H17(PR0_PRU0_GPIO13) ; also on sheet 32
PR0_PRU0_GPIO14: U1.H16(PR0_PRU0_GPIO14) ; also on sheet 32
PR0_PRU0_GPIO15: U1.L16(PR0_PRU0_GPIO15) ; also on sheet 32
PR0_PRU0_GPIO16: U1.H18(PR0_PRU0_GPIO16) ; also on sheet 32
PR0_PRU0_REF_CLK: U35.20(XI) ; also on sheet 9
R_LED2_0: J7.11 R216.1
RBIAS2: R215.1 TP63.1(TP) U35.12(RBIAS)
RJ45_ETH0_D0_N: J7.10(MX0-) U35.2(TD_M_A)
RJ45_ETH0_D0_P: J7.9(MX0+) U35.1(TD_P_A)
RJ45_ETH0_D1_N: J7.8(MX1-) U35.5(TD_M_B)
RJ45_ETH0_D1_P: J7.7(MX1+) U35.4(TD_P_B)
RJ45_ETH0_D2_N: J7.6(MX2-) U35.8(TD_M_C)
RJ45_ETH0_D2_P: J7.5(MX2+) U35.7(TD_P_C)
RJ45_ETH0_D3_N: J7.4(MX3-) U35.11(TD_M_D)
RJ45_ETH0_D3_P: J7.3(MX3+) U35.10(TD_P_D)
VSYS_3V3_LDO1: C189.1 C356.1 FL7.1 R214.1 R217.2 R470.1 R471.1 R472.1 R473.1 R474.2 U36.5(VCC) U81.10(VCC) ; also on sheet 1 6 7 9 10 11 12 13 14 17 24 26 27 28 29 30 32 33
N32845712: R396.1 U1.V9(ADC2_AIN4)
N32845714: R397.1 U1.T8(ADC2_AIN5)
N33221101: R400.1 U1.U4(ADC4_AIN5)
N33221125: R398.1 U1.U5(ADC4_AIN3)
N33221128: R399.1 U1.V3(ADC4_AIN4)
N34778760: TP61.1(TP) U35.13(VDDA1P8_1) U35.48(VDDA1P8_2)
N34779936: Q7.1(G) R222.2
N34780102: R207.1 R211.1 U1.L18(PR0_MDIO0_MDC)
N34780104: R208.1 R209.1 U1.L17(PR0_MDIO0_MDIO)
N34780660: FL3.2 J7.2(VCC)
N34780919: Q8.1(G) R223.2
N34780978: R210.2 U35.29(GTX_CLK/TX_CLK)
N34780980: R213.1 U35.46(LED_1/RX_ER)
N34780998: R212.2 U35.32(RX_CLK)
N34781014: Q6.1(G) R221.2
N35824901: R475.2 U81.9(~{EN})

Not connected (* = marked no-connect by the designer): SW9 1* 4*; SW13 1*; U1 P15(NC); U35 14(SON)* 15(SOP)* 16(SIP)* 17(SIN)* 19(XO)* 21(JTAG_CLK/TX_ER)* 23(JTAG_TMS)* 24(JTAG_TDI/SD)*; U67 8(NC1)* 9(NC2)*

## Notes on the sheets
sheet 15
- RJ45
- PRU0 ICSS MII0, CPSW RGMII/MII Ethernet
- Phy ID: 0000
- RESET
- From IO Exp
- LED Driver MOSFETS
- Place Near power pins of 10/100/1000 Ethernet PHY
- MDIO/MDC MUX FOR ON-BOARD PHY
- Strapping Resistors
- PHY ADDRESS = 00000
  Auto-negotiation, 10/100/1000 advertised, Auto-MDI-X
  RGMII to Copper (1000BaseT/100Base-TX/10Base-Te)
sheet 16
- SOC- ADC & DAC Interface
- CAD NOTE: Place the ESDs close to connector
- SOC- DAC Interface
- SILK "VREF"
- REF VOLTAGE SELECTION
- SW POSITION
- SUPPLY SELECTION
- ON BOARD REF IS
  SELECTED
- PIN 1-2
- HSEC SUPPLY IS SELECTED
- PIN 2-3
- SILK "DAC VREF"
- DAC REF VOLTAGE SELECTION
- SW POSITION
- SUPPLY SELECTION
- Allows AM263P on-die
  LDO reference (Routed n PCB)
- DIAG_OUT - PMIC Analog/Digital
  Diagnostic Output to MCU
- PIN 1-2
- selects output of VREF switch
- PIN 2-3
- SILK
  "ADC VREF"
- CAD NOTE: Place the CAPs close to each other
- CAD NOTE: - Place decoupling at BGA between
  VREF and GND
  Place GND short as close as possible
  to BGA and decoupling
- ADC REF VOLTAGE SELECTION
- CAD NOTE: Place the 2x2 header close to VSSA plane
- SW POSITION
- SUPPLY SELECTION
- OPEN - Allows AM263P on-die
  LDO reference (routed on-die)
- PIN 1-2
- CAD NOTE: Place the CAPs close to the connector
- PIN 2-3
- selects output of VREF switch
- PIN 4-5
- OPEN - Allows AM263P on-die
  LDO reference (routed on-die)
- PIN 5-6
- selects output of VREF switch
- ADC REF VOLTAGE SELECTION
- SW POSITION
- SUPPLY SELECTION
- PIN 1-2
- OPEN - Allows AM263P on-die
  LDO reference (routed on-die)
- PIN 2-3
- selects output of VREF switch
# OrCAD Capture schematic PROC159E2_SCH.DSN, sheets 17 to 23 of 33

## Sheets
17 26. XDS110 DEBUGGER: size C; title: XDS110 DEBUGGER
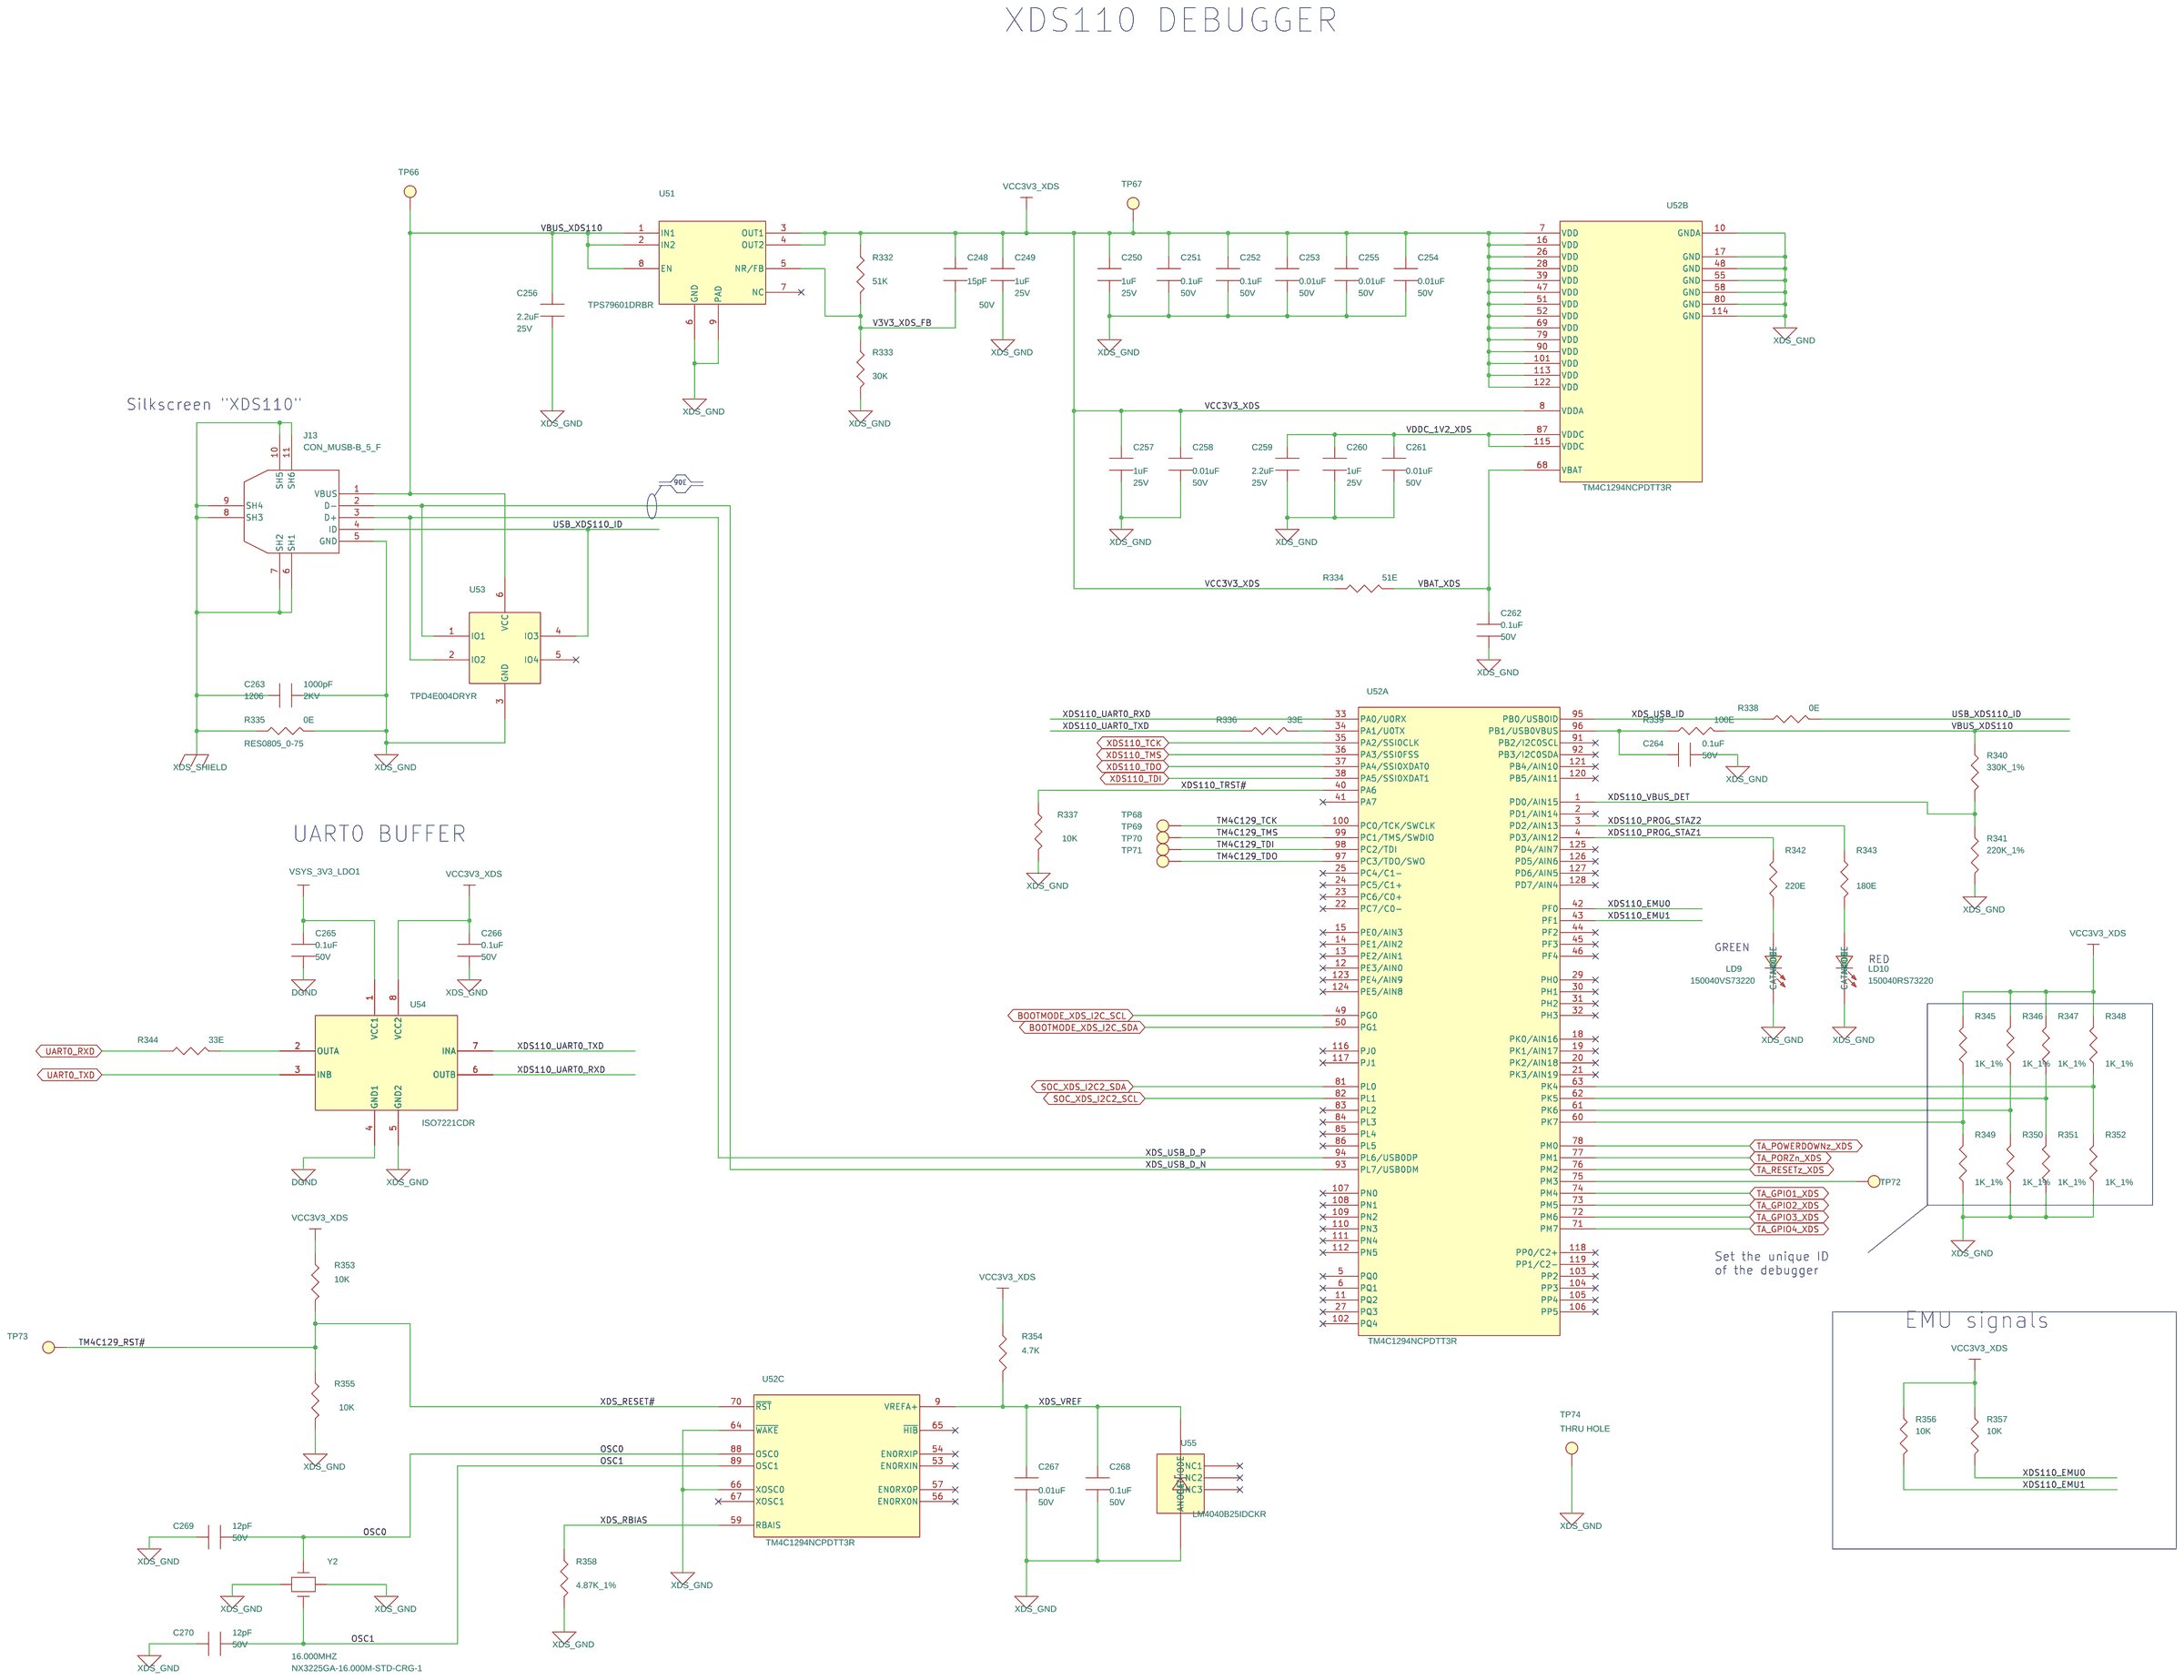
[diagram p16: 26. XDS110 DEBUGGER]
18 01. TABLE OF CONTENTS: title: TABLE OF CONTENTS
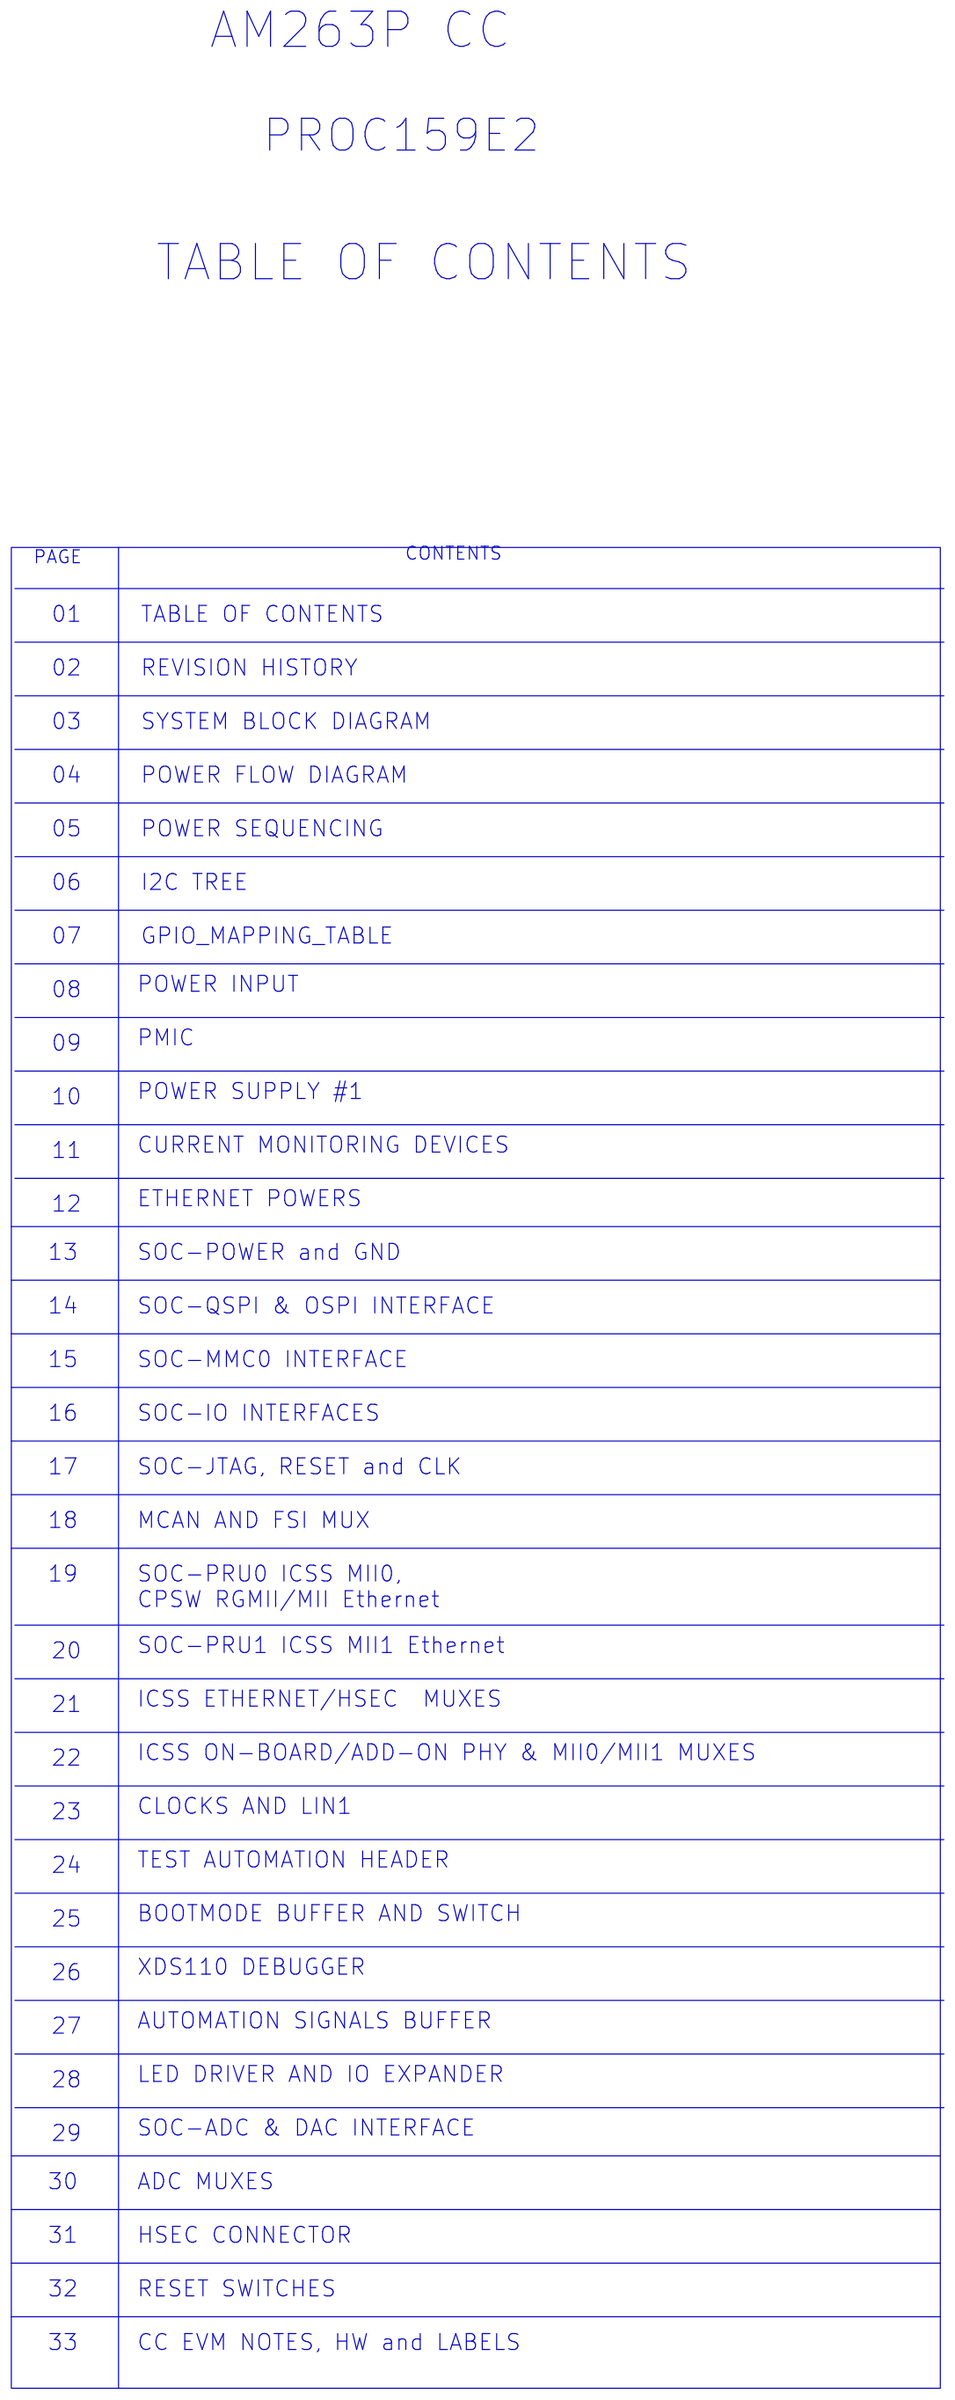
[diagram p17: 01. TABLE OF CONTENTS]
19 02. REVISION HISTORY: title: REVISION HISTORY
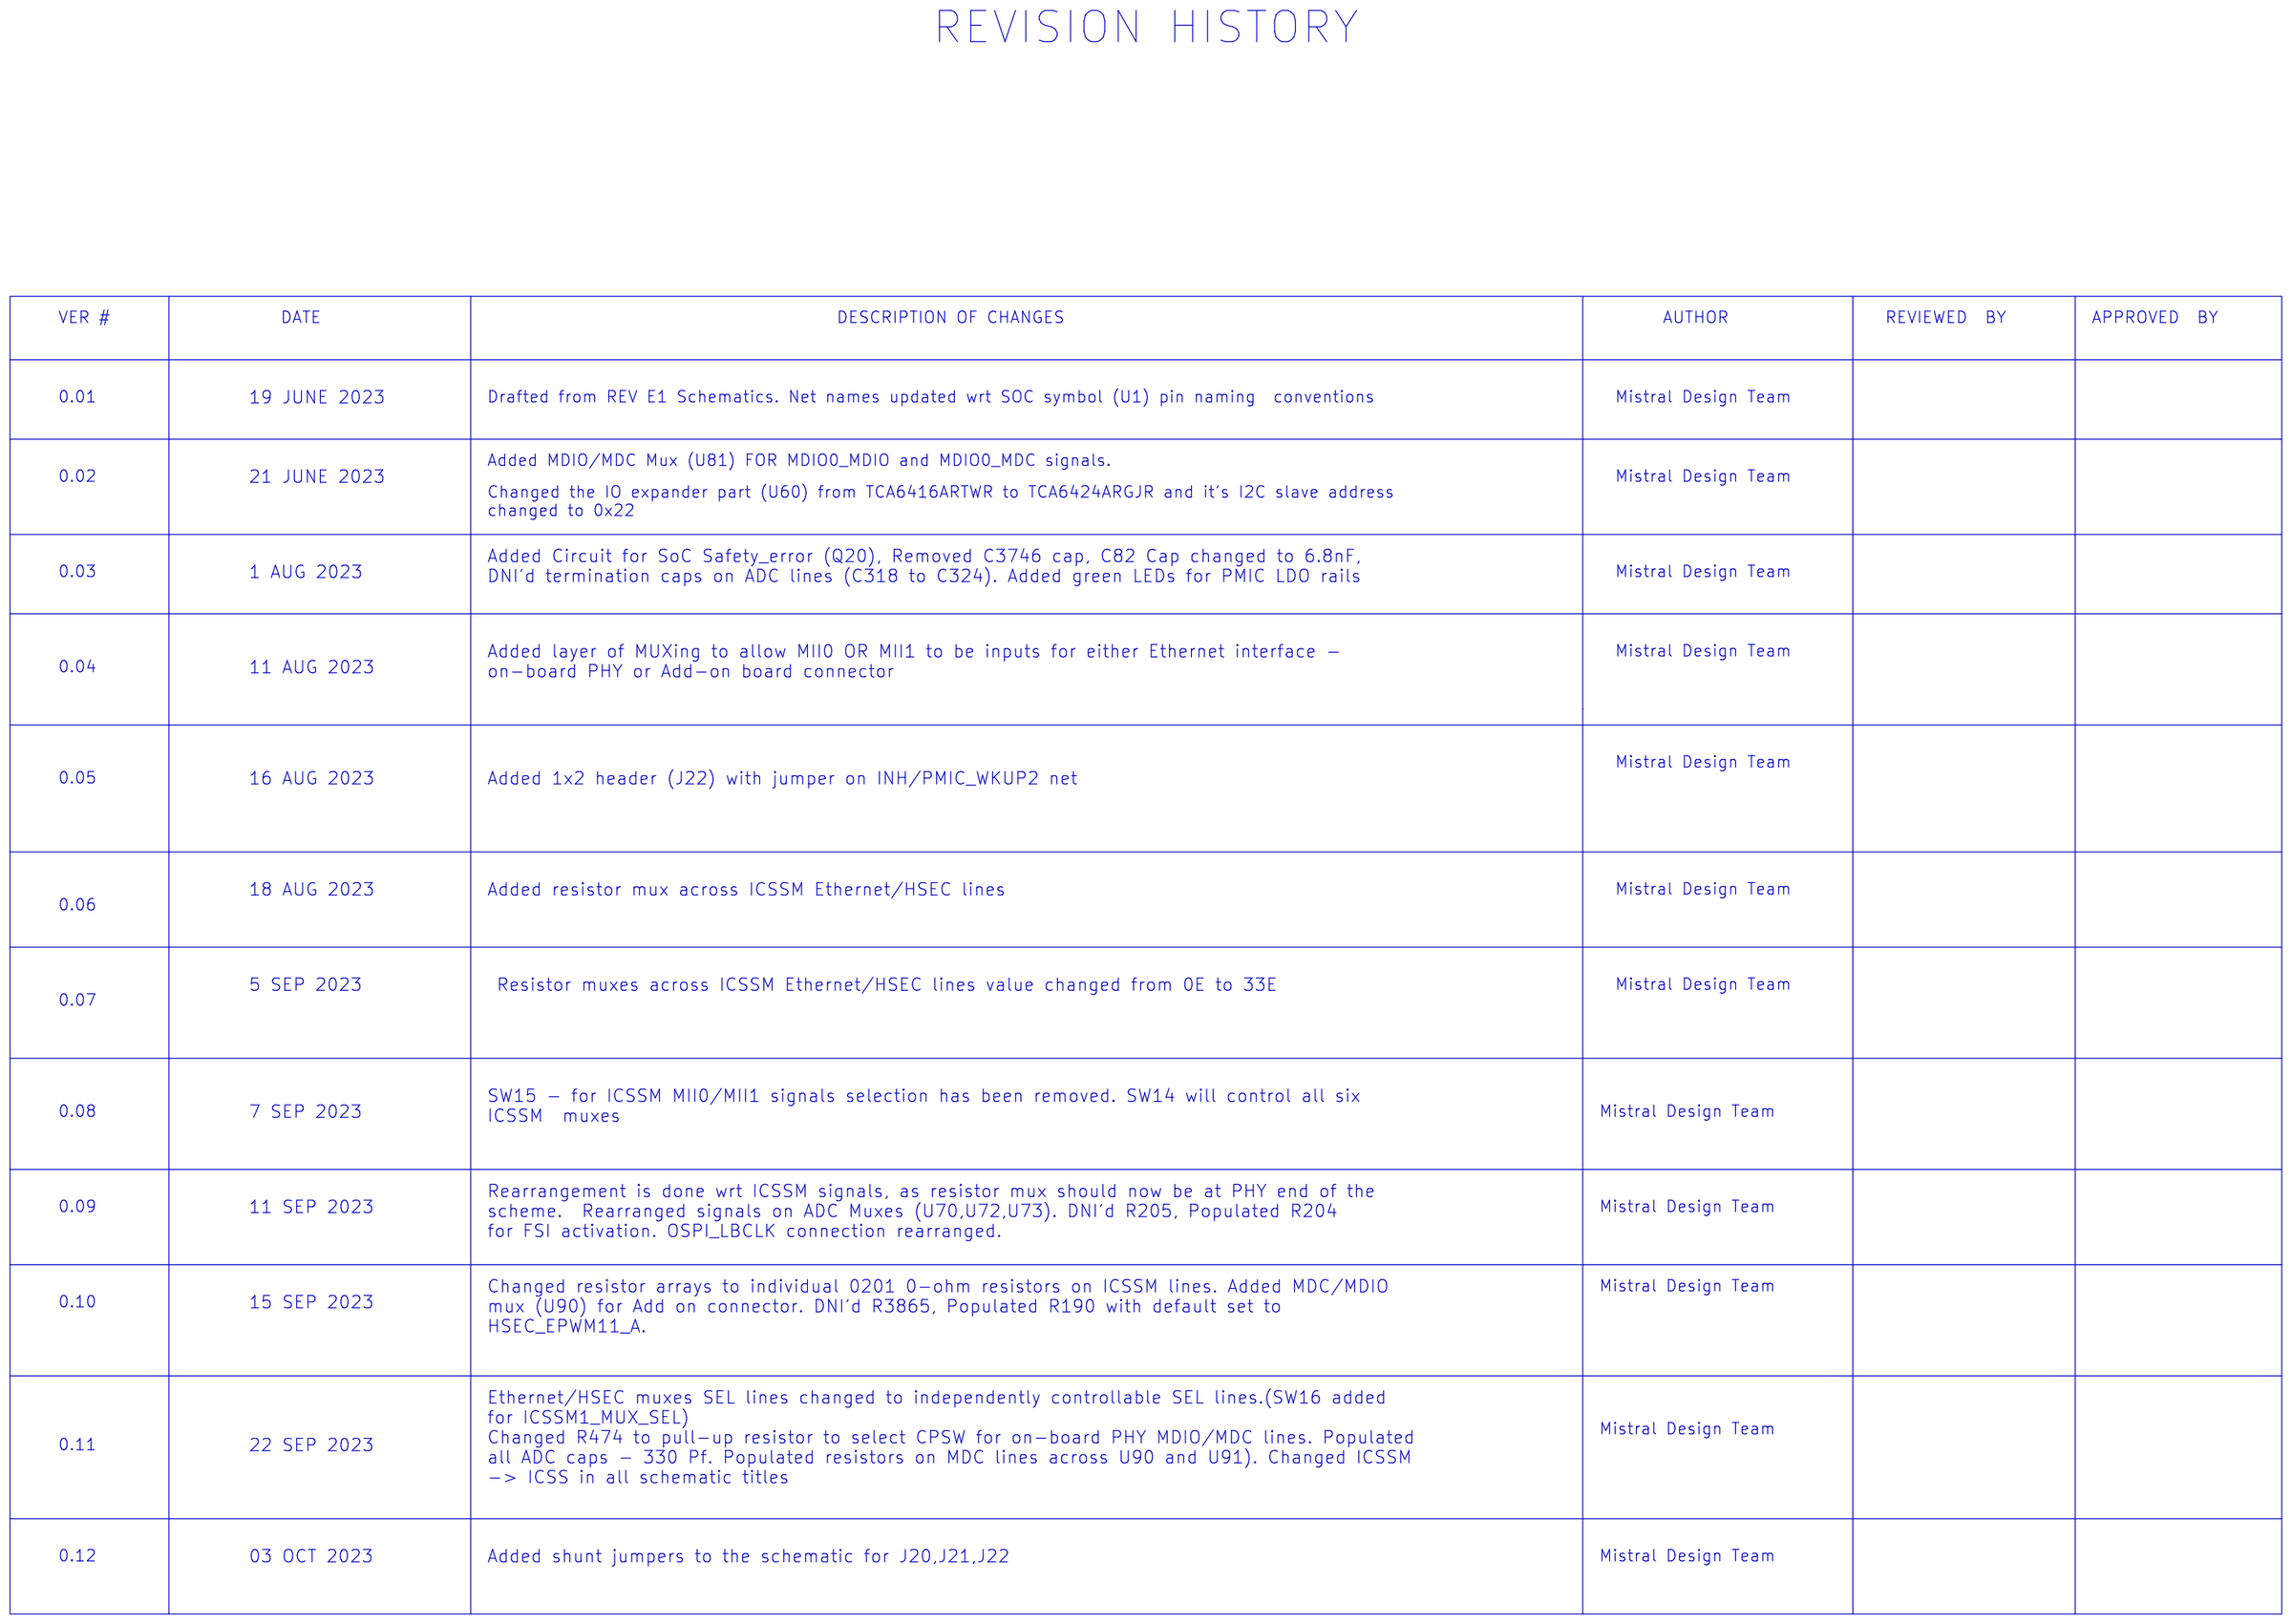
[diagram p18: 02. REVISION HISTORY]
20 03. SYSTEM BLOCK DGM: title: SYSTEM BLOCK DGM
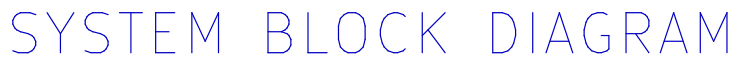
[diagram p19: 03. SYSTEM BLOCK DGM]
21 05. POWER FLOW DIAGRAM: title: POWER FLOW DIAGRAM
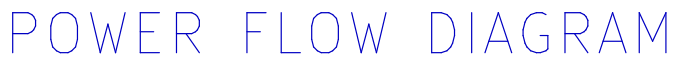
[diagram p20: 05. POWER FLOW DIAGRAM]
22 06. I2C TREE: title: I2C TREE DIAGRAM
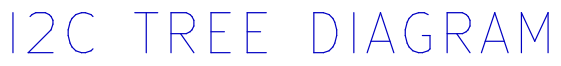
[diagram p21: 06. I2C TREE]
23 07. GPIO_MAPPING_TABLE: title: GPIO MAPPING TABLE

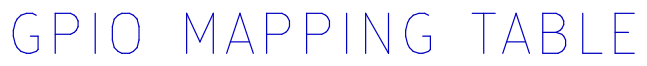
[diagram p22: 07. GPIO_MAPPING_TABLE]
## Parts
C248  15pF  [CAP0402_0-75]
C249  1uF  [CAP0402_0-75]
C250  1uF  [CAP0402_0-75]
C251  0.1uF  [CAP0402_0-75]
C252  0.1uF  [CAP0402_0-75]
C253  0.01uF  [CAP0402_0-75]
C254  0.01uF  [CAP0402_0-75]
C255  0.01uF  [CAP0402_0-75]
C256  2.2uF  [CAP0402_0-75]
C257  1uF  [CAP0402_0-75]
C258  0.01uF  [CAP0402_0-75]
C259  2.2uF  [CAP0402_0-75]
C260  1uF  [CAP0402_0-75]
C261  0.01uF  [CAP0402_0-75]
C262  0.1uF  [CAP0402_0-75]
C263  1000pF  [CAP1206_1-75]
C264  0.1uF  [CAP0402_0-75]
C265  0.1uF  [CAP0402_0-75]
C266  0.1uF  [CAP0402_0-75]
C267  0.01uF  [CAP0402_0-75]
C268  0.1uF  [CAP0402_0-75]
C269  12pF  [CAP0402_0-75]
C270  12pF  [CAP0402_0-75]
J13  CON_MUSB-B_5_F  [CON_USBB5_2013499-1_S_R_S_3]
LD9  150040VS73220  [LED_150040GS73220_40X20_SMD_0-4]
LD10  150040RS73220  [LED_150040GS73220_40X20_SMD_0-4]
R332  51K  [RES0402_0-5]
R333  30K  [RES0402_0-5]
R334  51E  [RES0402_0-5]
R335  0E  [RES0805_0-75]
R336  33E  [RES0402_0-5]
R337  10K  [RES0402_0-5]
R338  0E  [RES0402_0-5]
R339  100E  [RES0402_0-5]
R340  330K_1%  [RES0402_0-5]
R341  220K_1%  [RES0402_0-5]
R342  220E  [RES0402_0-5]
R343  180E  [RES0402_0-5]
R344  33E  [RES0402_0-5]
R345  1K_1%  [RES0402_0-5]
R346  1K_1%  [RES0402_0-5]
R347  1K_1%  [RES0402_0-5]
R348  1K_1%  [RES0402_0-5]
R349  1K_1%  [RES0402_0-5]
R350  1K_1%  [RES0402_0-5]
R351  1K_1%  [RES0402_0-5]
R352  1K_1%  [RES0402_0-5]
R353  10K  [RES0402_0-5]
R354  4.7K  [RES0402_0-5]
R355  10K  [RES0402_0-5]
R356  10K  [RES0402_0-5]
R357  10K  [RES0402_0-5]
R358  4.87K_1%  [RES0402_0-5]
TP66  TP40_SMD  [TP40_SMD]
TP67  TP40_SMD  [TP40_SMD]
TP68  TP40_SMD  [TP40_SMD]
TP69  TP40_SMD  [TP40_SMD]
TP70  TP40_SMD  [TP40_SMD]
TP71  TP40_SMD  [TP40_SMD]
TP72  TP40_SMD  [TP40_SMD]
TP73  TP40_SMD  [TP40_SMD]
TP74  THRU HOLE  [TP_40X65]
U51  TPS79601DRBR  [SON8_25-59_130X130_1]
U52  TM4C1294NCPDTT3R  [TQFP128_15-74_550X550_1-2]  (sections A,B,C)
U53  TPD4E004DRYR  [SON6_19-68_40X60_PB_0-6]
U54  ISO7221CDR  [SOIC8_1-8]
U55  LM4040B25IDCKR  [SC70-5_1-1]
Y2  16.000MHZ  [XTAL4_NX3225GA_130X100_SMD_0-9]

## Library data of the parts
C248 = CAP: CAP CERAMIC 15pF 50V 1% HI-Q C0G(NP0) 0402; Automotive Alternate_mfr_name: TDK; Automotive Alternate_mfr_part_number: CGA2B2C0G1H150J050BA; Chkd/date: USMAN/120313; Crtd /date: USMAN/250213; Custom_Duty: 15%; Customs_HS_Code: 85322990; Direct Alternate_mfr_name: TDK; Direct Alternate_mfr_part_number: C1005NP01H150J050BA; Distributor_name: MOUSER; Distributor_part_number: 81-GJM1555C1H150FB1D; Footprint Path: Y:\MIS_DATABASE\Library\ALTIUM_TOOL\PCB_FOOTPRINTS\Altium_Footprint_Lib.PcbLib; Height: 0.55MM; Library Path: Y:\MIS_DATABASE\Library\ALTIUM_TOOL\SCHEMATICS_PARTS\MS_DISCRETE_Library.schlib; Mfr_name: MURATA; Mfr_part_number: GJM1555C1H150FB01D; Mistral Part No: 120013020008-R; Package: 0402; Part_type: CAPACITORS\CERAMIC; Project: TM2; RoHS: RoHS; Temperature: -55°C+125°C; Tolerance: 1%; Voltage: 50V; Wattage: NA; Weight: 6mg; Datasheet: Y:\MIS_DATABASE\DATASHEETS\CAPACITORS\MURATA-GXX-SER_NOV17.PDF
C249 C250 C257 C260 = CAP: CAP CERAMIC 1uF 25V 10% X6S 0402; Automotive Alternate_mfr_name: TAIYO YUDEN; Automotive Alternate_mfr_part_number: EMK105BJ105KVHF; Chkd/date: MANIRAJA/140518; Crtd /date: ALVY/140518; Custom_Duty: 15%; Customs_HS_Code: 85322990; Direct Alternate_mfr_name: YAGEO AMERICA; Direct Alternate_mfr_part_number: CC0402KRX5R7BB105; Distributor_name: DIGIKEY; Distributor_part_number: 490-10014-1-ND; Footprint Path: Y:\MIS_DATABASE\Library\ALTIUM_TOOL\PCB_FOOTPRINTS\Altium_Footprint_Lib.PcbLib; Height: 0.60MM; Library Path: Y:\MIS_DATABASE\Library\ALTIUM_TOOL\SCHEMATICS_PARTS\MS_DISCRETE_Library.schlib; Mfr_name: MURATA; Mfr_part_number: GRM155C81E105KE11D; Mistral Part No: 120018050004-R; Package: 0402; Part_type: CAPACITORS\CERAMIC; Project: TI_SVB_MAXWELL_DUT; RoHS: RoHS; Temperature: -55°C+105°C; Tolerance: 10%; Voltage: 25V; Wattage: NA; Weight: 6mg; Datasheet: Y:\MIS_DATABASE\DATASHEETS\CAPACITORS\GRM155C81E105KE11X.PDF
C251 C252 C262 C264-C266 C268 = CAP: CAP CERAMIC 0.1uF 50V 10% X7R 0402; Automotive Alternate_mfr_name: TDK; Automotive Alternate_mfr_part_number: CGA2B3X7R1H104K050BB; Chkd/date: MANIRAJA/261020; Crtd /date: ALVY/211020; Custom_Duty: 15%; Customs_HS_Code: 85322990; Direct Alternate_mfr_name: TDK; Direct Alternate_mfr_part_number: C1005X7R1H104K050BE; Distributor_name: DIGIKEY; Distributor_part_number: 490-10700-1-ND; Footprint Path: Y:\MIS_DATABASE\Library\ALTIUM_TOOL\PCB_FOOTPRINTS\Altium_Footprint_Lib.PcbLib; Height: 0.55MM; Library Path: Y:\MIS_DATABASE\Library\ALTIUM_TOOL\SCHEMATICS_PARTS\MS_DISCRETE_Library.schlib; Mfr_name: MURATA; Mfr_part_number: GRM155R71H104KE14D; Mistral Part No: 120011100014-R; Package: 0402; Part_type: CAPACITORS\CERAMIC; Project: J7_CP; RoHS: RoHS; Temperature: -55°C+125°C; Tolerance: 10%; Voltage: 50V; Wattage: NA; Weight: 3.1mg; Datasheet: Y:\MIS_DATABASE\DATASHEETS\CAPACITORS\GRM155R71H104KE14.PDF
C253-C255 C258 C261 C267 = CAP: CAP CERAMIC 0.01uF 50V 10% X7R 0402; Automotive Alternate_mfr_name: TDK; Automotive Alternate_mfr_part_number: CGA2B2X7R1E103K050BA; Chkd/date: MANIRAJA/280319; Crtd /date: MANIRAJA/280319; Custom_Duty: 15%; Customs_HS_Code: 85322990; Direct Alternate_mfr_name: YAGEO AMERICA; Direct Alternate_mfr_part_number: CC0402KRX7R8BB103; Distributor_name: DIGIKEY; Distributor_part_number: 490-4516-1-ND; Footprint Path: Y:\MIS_DATABASE\Library\ALTIUM_TOOL\PCB_FOOTPRINTS\Altium_Footprint_Lib.PcbLib; Height: 0.55MM; Library Path: Y:\MIS_DATABASE\Library\ALTIUM_TOOL\SCHEMATICS_PARTS\MS_DISCRETE_Library.schlib; Mfr_name: MURATA; Mfr_part_number: GRM155R71H103KA88D; Mistral Part No: 120009030025-R; Package: 0402; Part_type: CAPACITORS\CERAMIC; Project: G4_SVGA; RoHS: RoHS; Temperature: -55°C+125°C; Tolerance: 10%; Voltage: 50V; Wattage: NA; Weight: 0.65mg; Datasheet: Y:\MIS_DATABASE\DATASHEETS\CAPACITORS\GRM155R71H103KA88D.PDF
C256 C259 = CAP: CAP CERAMIC 2.2uF 25V 10% X5R 0402; Automotive Alternate_mfr_name: TAIYO YUDEN; Automotive Alternate_mfr_part_number: LMK105ABJ225MVHF; Chkd/date: ALVY/010721; Crtd /date: MANIRAJA/010721; Custom_Duty: 15%; Customs_HS_Code: 85322990; Direct Alternate_mfr_name: TDK; Direct Alternate_mfr_part_number: C1005X5R1A225K050BC; Distributor_name: DIGIKEY; Distributor_part_number: 490-12703-1-ND; Footprint Path: Y:\MIS_DATABASE\Library\ALTIUM_TOOL\PCB_FOOTPRINTS\Altium_Footprint_Lib.PcbLib; Height: 0.70MM; Library Path: Y:\MIS_DATABASE\Library\ALTIUM_TOOL\SCHEMATICS_PARTS\MS_DISCRETE_Library.schlib; Mfr_name: MURATA; Mfr_part_number: GRM155R61E225KE11D; Mistral Part No: 120015120001-R; Package: 0402; Part_type: CAPACITORS\CERAMIC; Project: TI_AM263X_CC; RoHS: RoHS; Temperature: -55°C+85°C; Tolerance: 10%; Voltage: 25V; Wattage: NA; Weight: 1.5mg; Datasheet: Y:\MIS_DATABASE\DATASHEETS\CAPACITORS\GRM155R61E225KE11.PDF
C263 = CAP: CAP CERAMIC 1000pF 2KV 10% X7R 1206; Chkd/date: SHREESHAIL/291106; Crtd /date: MAZHAR/281106; Custom_Duty: 15%; Customs_HS_Code: 85322990; Distributor_name: DIGIKEY; Distributor_part_number: 478-2956-1-ND; Footprint Path: Y:\MIS_DATABASE\Library\ALTIUM_TOOL\PCB_FOOTPRINTS\Altium_Footprint_Lib.PcbLib; Height: 1.52MM; Library Path: Y:\MIS_DATABASE\Library\ALTIUM_TOOL\SCHEMATICS_PARTS\MS_DISCRETE_Library.schlib; Mfr_name: AVX CORPORATION; Mfr_part_number: 1206GC102KAT1A; Mistral Part No: 120015080006-R; Package: 1206; Part_type: CAPACITORS\CERAMIC; Project: ADR1B; RoHS: RoHS; Temperature: -55°C+125°C; Tolerance: 10%; Voltage: 2KV; Wattage: NA; Weight: 16.2mg; Datasheet: Y:\MIS_DATABASE\DATASHEETS\CAPACITORS\AVX_HV-MLC.PDF
C269 C270 = CAP: CAP CERAMIC 12pF 50V 5% HI-Q C0G(NP0) 0402; Automotive Alternate_mfr_name: TDK; Automotive Alternate_mfr_part_number: CGA2B2C0G1H120J050BA; Chkd/date: MANIRAJA/020419; Crtd /date: MANIRAJA/020419; Custom_Duty: 15%; Customs_HS_Code: 85322990; Direct Alternate_mfr_name: SAMSUNG; Direct Alternate_mfr_part_number: CL05C120JB5NNNC; Distributor_name: DIGIKEY; Distributor_part_number: 490-3115-1-ND; Footprint Path: Y:\MIS_DATABASE\Library\ALTIUM_TOOL\PCB_FOOTPRINTS\Altium_Footprint_Lib.PcbLib; Height: 0.55MM; Library Path: Y:\MIS_DATABASE\Library\ALTIUM_TOOL\SCHEMATICS_PARTS\MS_DISCRETE_Library.schlib; Mfr_name: MURATA; Mfr_part_number: GJM1555C1H120JB01D; Mistral Part No: 120019040031-R; Package: 0402; Part_type: CAPACITORS\CERAMIC; Project: EPDA_CORE; RoHS: RoHS; Temperature: -55°C+125°C; Tolerance: 5%; Voltage: 50V; Wattage: NA; Weight: 0.65mg; Datasheet: Y:\MIS_DATABASE\DATASHEETS\CAPACITORS\GJM1555C1H120JB01.PDF
J13 = CON_USB_MINI-B11: CON MICRO USB-B TYPE 5POS FEMALE RT SMD; Chkd/date: MANIRAJA/021220; Crtd /date: ALVY/021220; Custom_Duty: 24%; Customs_HS_Code: 85369090; Distributor_name: DIGIKEY; Distributor_part_number: A107962CT-ND; Footprint Path: Y:\MIS_DATABASE\Library\ALTIUM_TOOL\PCB_FOOTPRINTS\Altium_Footprint_Lib.PcbLib; Height: 3.00MM; Library Path: Y:\MIS_DATABASE\Library\ALTIUM_TOOL\SCHEMATICS_PARTS\MS_CONNECTOR_Library.schlib; Mfr_name: TE CONNECTIVITY; Mfr_part_number: 2013499-1; Mistral Part No: 150020120001-R; Package: SMD; Part_type: CONNECTOR\USB; Project: VEETECH_SENSOR_BADGE; RoHS: RoHS; Temperature: -30°C+85°C; Tolerance: NA; Voltage: NA; Wattage: NA; Weight: 624mg; Datasheet: Y:\MIS_DATABASE\DATASHEETS\CONNECTORS\2013499.PDF
LD9 = DIODE_LED: DIODE LED BRIGHT GREEN SMD; Chkd/date: MANIRAJA/261120; Crtd /date: ALVY/261120; Custom_Duty: 24%; Customs_HS_Code: 85439000; Distributor_name: DIGIKEY; Distributor_part_number: 732-13425-1-ND; Footprint Path: Y:\MIS_DATABASE\Library\ALTIUM_TOOL\PCB_FOOTPRINTS\Altium_Footprint_Lib.PcbLib; Height: 0.35MM; Library Path: Y:\MIS_DATABASE\Library\ALTIUM_TOOL\SCHEMATICS_PARTS\MS_OPTO_Library.schlib; Mfr_name: WURTH ELECTRONIK; Mistral Part No: 130020110071-R; Package: SMD; Part_type: OPTO\LED; Project: AM64X_SKEVM; RoHS: RoHS; Temperature: -40°C+85°C; Tolerance: NA; Voltage: NA; Wattage: NA; Weight: 29.3mg; Datasheet: Y:\MIS_DATABASE\DATASHEETS\DISCRETES\LEDS\150040VS73220.PDF
LD10 = DIODE_LED: DIODE LED RED SMD; Chkd/date: MANIRAJA/100920; Crtd /date: ALVY/100920; Custom_Duty: 24%; Customs_HS_Code: 85439000; Distributor_name: DIGIKEY; Distributor_part_number: 732-13422-1-ND; Footprint Path: Y:\MIS_DATABASE\Library\ALTIUM_TOOL\PCB_FOOTPRINTS\Altium_Footprint_Lib.PcbLib; Height: 0.35MM; Library Path: Y:\MIS_DATABASE\Library\ALTIUM_TOOL\SCHEMATICS_PARTS\MS_OPTO_Library.schlib; Mfr_name: WURTH ELECTRONICS; Mistral Part No: 130020090020-R; Package: SMD; Part_type: OPTO\LED; Project: AM64X_SKEVM; RoHS: RoHS; Temperature: -40°C+85°C; Tolerance: NA; Voltage: NA; Wattage: NA; Weight: 29.3mg; Datasheet: Y:\MIS_DATABASE\DATASHEETS\DISCRETES\LEDS\150040RS73220.PDF
R332 = RESISTOR: RES 51K 1/16W 5% 0402; Chkd/date: MANIRAJA/230817; Crtd /date: MANIRAJA/230817; Custom_Duty: 15%; Customs_HS_Code: 85332119; Distributor_name: DIGIKEY; Distributor_part_number: 541-51KJCT-ND; Footprint Path: Y:\MIS_DATABASE\Library\ALTIUM_TOOL\PCB_FOOTPRINTS\Altium_Footprint_Lib.PcbLib; Height: 0.40MM; Library Path: Y:\MIS_DATABASE\Library\ALTIUM_TOOL\SCHEMATICS_PARTS\MS_DISCRETE_Library.schlib; Mfr_name: VISHAY; Mfr_part_number: CRCW040251K0JNED; Mistral Part No: 110009030966-R; Package: 0402; Part_type: RESISTORS\FIXED; Project: TI_MAXIE_CPB; RoHS: RoHS; Temperature: -55°C+155°C; Tolerance: 5%; Voltage: NA; Wattage: 1/16W; Weight: 0.65mg; Datasheet: Y:\MIS_DATABASE\DATASHEETS\RESISTORS\CRCW0603.PDF
R333 = RESISTOR: RES 30K 1/16W 5% 0402; Chkd/date: MANIRAJA/230817; Crtd /date: MANIRAJA/230817; Custom_Duty: 15%; Customs_HS_Code: 85332119; Distributor_name: DIGIKEY; Distributor_part_number: 541-30KJCT-ND; Footprint Path: Y:\MIS_DATABASE\Library\ALTIUM_TOOL\PCB_FOOTPRINTS\Altium_Footprint_Lib.PcbLib; Height: 0.40MM; Library Path: Y:\MIS_DATABASE\Library\ALTIUM_TOOL\SCHEMATICS_PARTS\MS_DISCRETE_Library.schlib; Mfr_name: VISHAY; Mfr_part_number: CRCW040230K0JNED; Mistral Part No: 110017080023-R; Package: 0402; Part_type: RESISTORS\FIXED; Project: TI_MAXIE_CPB; RoHS: RoHS; Temperature: -55°C+155°C; Tolerance: 5%; Voltage: NA; Wattage: 1/16W; Weight: 0.65mg; Datasheet: Y:\MIS_DATABASE\DATASHEETS\RESISTORS\CRCW0603.PDF
R334 = RESISTOR: RES 51E 1/10W 5% 0402; Chkd/date: VASANTHA/291216; Crtd /date: MAZHAR/120505; Custom_Duty: 15%; Customs_HS_Code: 85332119; Distributor_name: DIGIKEY; Distributor_part_number: P51JCT-ND; Footprint Path: Y:\MIS_DATABASE\Library\ALTIUM_TOOL\PCB_FOOTPRINTS\Altium_Footprint_Lib.PcbLib; Height: 0.40MM; Library Path: Y:\MIS_DATABASE\Library\ALTIUM_TOOL\SCHEMATICS_PARTS\MS_DISCRETE_Library.schlib; Mfr_name: PANASONIC-ECG; Mfr_part_number: ERJ-2GEJ510X; Mistral Part No: 110009030962-R; Package: 0402; Part_type: RESISTORS\FIXED; Project: CTP02_REVA_BASE; RoHS: RoHS; Temperature: -55°C+155°C; Tolerance: 5%; Voltage: NA; Wattage: 1/10W; Weight: 0.8mg; Datasheet: Y:\MIS_DATABASE\DATASHEETS\RESISTORS\PAN-ERJSER_NOV17.PDF
R335 = RESISTOR: RES 0E 1/8W 5% 0805; Chkd/date: VASANTHA/130416; Crtd /date: JEBRAN/020316; Custom_Duty: 15%; Customs_HS_Code: 85332119; Distributor_name: DIGIKEY; Distributor_part_number: 311-0.0ARCT-ND; Footprint Path: Y:\MIS_DATABASE\Library\ALTIUM_TOOL\PCB_FOOTPRINTS\Altium_Footprint_Lib.PcbLib; Height: 0.60MM; Library Path: Y:\MIS_DATABASE\Library\ALTIUM_TOOL\SCHEMATICS_PARTS\MS_DISCRETE_Library.schlib; Mfr_name: YAGEO AMERICA; Mfr_part_number: RC0805JR-070RL; Mistral Part No: 110009030074-R; Package: 0805; Part_type: RESISTORS\FIXED; Project: ZK_BIOMETRIC; RoHS: RoHS; Temperature: -55°C+155°C; Tolerance: 5%; Voltage: NA; Wattage: 1/8W; Weight: 5.5mg; Datasheet: Y:\MIS_DATABASE\DATASHEETS\RESISTORS\RCXXXXL-SER_MAR18.PDF
R336 R344 = RESISTOR: RES 33E 1/10W 5% 0402; Chkd/date: VASANTHA/201216; Crtd /date: GEETHA/190406; Custom_Duty: 15%; Customs_HS_Code: 85332119; Distributor_name: DIGIKEY; Distributor_part_number: P33JCT-ND; Footprint Path: Y:\MIS_DATABASE\Library\ALTIUM_TOOL\PCB_FOOTPRINTS\Altium_Footprint_Lib.PcbLib; Height: 0.40MM; Library Path: Y:\MIS_DATABASE\Library\ALTIUM_TOOL\SCHEMATICS_PARTS\MS_DISCRETE_Library.schlib; Mfr_name: PANASONIC-ECG; Mfr_part_number: ERJ-2GEJ330X; Mistral Part No: 110009030699-R; Package: 0402; Part_type: RESISTORS\FIXED; Project: RED EYE; RoHS: RoHS; Temperature: -55°C+155°C; Tolerance: 5%; Voltage: NA; Wattage: 1/10W; Weight: 0.8mg; Datasheet: Y:\MIS_DATABASE\DATASHEETS\RESISTORS\PAN-ERJSER_NOV17.PDF
R337 R355-R357 = RESISTOR: RES 10K 1/16W 5% 0402; Assembly_Instruction: DNI; Chkd/date: VASANTHA/061216; Crtd /date: MAZHAR/230805; Custom_Duty: 15%; Customs_HS_Code: 85332119; Distributor_name: DIGIKEY; Distributor_part_number: 311-10KJRCT-ND; Footprint Path: Y:\MIS_DATABASE\Library\ALTIUM_TOOL\PCB_FOOTPRINTS\Altium_Footprint_Lib.PcbLib; Height: 0.40MM; Library Path: Y:\MIS_DATABASE\Library\ALTIUM_TOOL\SCHEMATICS_PARTS\MS_DISCRETE_Library.schlib; Mfr_name: YAGEO AMERICA; Mfr_part_number: RC0402JR-0710KL; Mistral Part No: 110011060021-R; Package: 0402; Part_type: RESISTORS\FIXED; Project: HSE; RoHS: RoHS; Temperature: -55°C+155°C; Tolerance: 5%; Voltage: NA; Wattage: 1/16W; Weight: 0.65mg; Datasheet: Y:\MIS_DATABASE\DATASHEETS\RESISTORS\RCXXXXL-SER_MAR18.PDF
R338 = RESISTOR: RES 0E 1/10W JUMPER 0402; Assembly_Instruction: DNI; Chkd/date: VASANTHA/061216; Crtd /date: NAVEED/201014; Custom_Duty: 15%; Customs_HS_Code: 85332119; Distributor_name: DIGIKEY; Distributor_part_number: P0.0JCT-ND; Footprint Path: Y:\MIS_DATABASE\Library\ALTIUM_TOOL\PCB_FOOTPRINTS\Altium_Footprint_Lib.PcbLib; Height: 0.40MM; IBISSP_MODLES: VALUE REPEATING 2 TIME; Library Path: Y:\MIS_DATABASE\Library\ALTIUM_TOOL\SCHEMATICS_PARTS\MS_DISCRETE_Library.schlib; Mfr_name: PANASONIC-ECG; Mfr_part_number: ERJ-2GE0R00X; Mistral Part No: 110018030052-R; Package: 0402; Part_type: RESISTORS\FIXED; Project: AEGIS POM; RoHS: RoHS; Temperature: -55°C+155°C; Tolerance: NA; Voltage: NA; Wattage: 1/10W; Weight: 0.8mg; Datasheet: Y:\MIS_DATABASE\DATASHEETS\RESISTORS\PAN-ERJSER_NOV17.PDF
R339 = RESISTOR: RES 100E 1/10W 1% 0402; Chkd/date: ALVY/230621; Crtd /date: ALVY/230621; Custom_Duty: 15%; Customs_HS_Code: 85332119; Distributor_name: DIGIKEY; Distributor_part_number: 10-ERJ-U02F1000XCT-ND; Footprint Path: Y:\MIS_DATABASE\Library\ALTIUM_TOOL\PCB_FOOTPRINTS\Altium_Footprint_Lib.PcbLib; Height: 0.40MM; Library Path: Y:\MIS_DATABASE\Library\ALTIUM_TOOL\SCHEMATICS_PARTS\MS_DISCRETE_Library.schlib; Mfr_name: PANASONIC-ECG; Mfr_part_number: ERJ-U02F1000X; Mistral Part No: 110018020036-R; Package: 0402; Part_type: RESISTORS\FIXED; Project: AM263x_CC; RoHS: RoHS; Temperature: -55°C+155°C; Tolerance: 1%; Voltage: NA; Wattage: 1/10W; Weight: 0.8mg; Datasheet: Y:\MIS_DATABASE\DATASHEETS\RESISTORS\ERJ-U0_S0.PDF
R340 = RESISTOR: RES 330K 1/16W 1% 0402; Chkd/date: MANIRAJA/230817; Crtd /date: MANIRAJA/230817; Custom_Duty: 15%; Customs_HS_Code: 85332119; Distributor_name: DIGIKEY; Distributor_part_number: 541-330KLCT-ND; Footprint Path: Y:\MIS_DATABASE\Library\ALTIUM_TOOL\PCB_FOOTPRINTS\Altium_Footprint_Lib.PcbLib; Height: 0.40MM; Library Path: Y:\MIS_DATABASE\Library\ALTIUM_TOOL\SCHEMATICS_PARTS\MS_DISCRETE_Library.schlib; Mfr_name: VISHAY; Mfr_part_number: CRCW0402330KFKED; Mistral Part No: 110017080024-R; Package: 0402; Part_type: RESISTORS\FIXED; Project: TI_MAXIE_CPB; RoHS: RoHS; Temperature: -55°C+155°C; Tolerance: 1%; Voltage: NA; Wattage: 1/16W; Weight: 0.65mg; Datasheet: Y:\MIS_DATABASE\DATASHEETS\RESISTORS\CRCW0603.PDF
R341 = RESISTOR: RES 220K 1/16W 1% 0402; Chkd/date: MANIRAJA/230817; Crtd /date: MANIRAJA/230817; Custom_Duty: 15%; Customs_HS_Code: 85332119; Distributor_name: DIGIKEY; Distributor_part_number: 541-220KLCT-ND; Footprint Path: Y:\MIS_DATABASE\Library\ALTIUM_TOOL\PCB_FOOTPRINTS\Altium_Footprint_Lib.PcbLib; Height: 0.40MM; Library Path: Y:\MIS_DATABASE\Library\ALTIUM_TOOL\SCHEMATICS_PARTS\MS_DISCRETE_Library.schlib; Mfr_name: VISHAY; Mfr_part_number: CRCW0402220KFKED; Mistral Part No: 110017080025-R; Package: 0402; Part_type: RESISTORS\FIXED; Project: TI_MAXIE_CPB; RoHS: RoHS; Temperature: -55°C+155°C; Tolerance: 1%; Voltage: NA; Wattage: 1/16W; Weight: 0.65mg; Datasheet: Y:\MIS_DATABASE\DATASHEETS\RESISTORS\CRCW0603.PDF
R342 = RESISTOR: RES 220E 1/10W 5% 0402; Chkd/date: VASANTHA/291216; Crtd /date: GEETHA/260406; Custom_Duty: 15%; Customs_HS_Code: 85332119; Distributor_name: DIGIKEY; Distributor_part_number: P220JCT-ND; Footprint Path: Y:\MIS_DATABASE\Library\ALTIUM_TOOL\PCB_FOOTPRINTS\Altium_Footprint_Lib.PcbLib; Height: 0.40MM; Library Path: Y:\MIS_DATABASE\Library\ALTIUM_TOOL\SCHEMATICS_PARTS\MS_DISCRETE_Library.schlib; Mfr_name: PANASONIC-ECG; Mfr_part_number: ERJ-2GEJ221X; Mistral Part No: 110009030506-R; Package: 0402; Part_type: RESISTORS\FIXED; Project: RED EYE; RoHS: RoHS; Temperature: -55°C+155°C; Tolerance: 5%; Voltage: NA; Wattage: 1/10W; Weight: 0.8mg; Datasheet: Y:\MIS_DATABASE\DATASHEETS\RESISTORS\PAN-ERJSER_NOV17.PDF
R343 = RESISTOR: RES 180E 1/10W 5% 0402; Chkd/date: MAZHAR/150709; Crtd /date: GEETHA/280406; Custom_Duty: 15%; Customs_HS_Code: 85332119; Distributor_name: DIGIKEY; Distributor_part_number: P180JCT-ND; Footprint Path: Y:\MIS_DATABASE\Library\ALTIUM_TOOL\PCB_FOOTPRINTS\Altium_Footprint_Lib.PcbLib; Height: 0.40MM; Library Path: Y:\MIS_DATABASE\Library\ALTIUM_TOOL\SCHEMATICS_PARTS\MS_DISCRETE_Library.schlib; Mfr_name: PANASONIC-ECG; Mfr_part_number: ERJ-2GEJ181X; Mistral Part No: 110009030371-R; Package: 0402; Part_type: RESISTORS\FIXED; Project: RED EYE; RoHS: RoHS; Temperature: -55°C+155°C; Tolerance: 5%; Voltage: NA; Wattage: 1/10W; Weight: 0.8mg; Datasheet: Y:\MIS_DATABASE\DATASHEETS\RESISTORS\PAN-ERJSER_NOV17.PDF
R345-R348 = RESISTOR: RES 1K 1/10W 1% 0402; Chkd/date: VASANTHA/281216; Crtd /date: MAZHAR/150506; Custom_Duty: 15%; Customs_HS_Code: 85332119; Distributor_name: DIGIKEY; Distributor_part_number: P1.00KLCT-ND; Footprint Path: Y:\MIS_DATABASE\Library\ALTIUM_TOOL\PCB_FOOTPRINTS\Altium_Footprint_Lib.PcbLib; Height: 0.40MM; Library Path: Y:\MIS_DATABASE\Library\ALTIUM_TOOL\SCHEMATICS_PARTS\MS_DISCRETE_Library.schlib; Mfr_name: PANASONIC-ECG; Mfr_part_number: ERJ-2RKF1001X; Mistral Part No: 110009030411-R; Package: 0402; Part_type: RESISTORS\FIXED; Project: VOCERA; RoHS: RoHS; Temperature: -55°C+155°C; Tolerance: 1%; Voltage: NA; Wattage: 1/10W; Weight: 0.8mg; Datasheet: Y:\MIS_DATABASE\DATASHEETS\RESISTORS\PAN-ERJSER_NOV17.PDF
R349-R352 = RESISTOR: RES 1K 1/10W 1% 0402; Assembly_Instruction: DNI; Chkd/date: VASANTHA/281216; Crtd /date: MAZHAR/150506; Custom_Duty: 15%; Customs_HS_Code: 85332119; Distributor_name: DIGIKEY; Distributor_part_number: P1.00KLCT-ND; Footprint Path: Y:\MIS_DATABASE\Library\ALTIUM_TOOL\PCB_FOOTPRINTS\Altium_Footprint_Lib.PcbLib; Height: 0.40MM; Library Path: Y:\MIS_DATABASE\Library\ALTIUM_TOOL\SCHEMATICS_PARTS\MS_DISCRETE_Library.schlib; Mfr_name: PANASONIC-ECG; Mfr_part_number: ERJ-2RKF1001X; Mistral Part No: 110009030411-R; Package: 0402; Part_type: RESISTORS\FIXED; Project: VOCERA; RoHS: RoHS; Temperature: -55°C+155°C; Tolerance: 1%; Voltage: NA; Wattage: 1/10W; Weight: 0.8mg; Datasheet: Y:\MIS_DATABASE\DATASHEETS\RESISTORS\PAN-ERJSER_NOV17.PDF
R353 = RESISTOR: RES 10K 1/16W 5% 0402; Chkd/date: VASANTHA/061216; Crtd /date: MAZHAR/230805; Custom_Duty: 15%; Customs_HS_Code: 85332119; Distributor_name: DIGIKEY; Distributor_part_number: 311-10KJRCT-ND; Footprint Path: Y:\MIS_DATABASE\Library\ALTIUM_TOOL\PCB_FOOTPRINTS\Altium_Footprint_Lib.PcbLib; Height: 0.40MM; Library Path: Y:\MIS_DATABASE\Library\ALTIUM_TOOL\SCHEMATICS_PARTS\MS_DISCRETE_Library.schlib; Mfr_name: YAGEO AMERICA; Mfr_part_number: RC0402JR-0710KL; Mistral Part No: 110011060021-R; Package: 0402; Part_type: RESISTORS\FIXED; Project: HSE; RoHS: RoHS; Temperature: -55°C+155°C; Tolerance: 5%; Voltage: NA; Wattage: 1/16W; Weight: 0.65mg; Datasheet: Y:\MIS_DATABASE\DATASHEETS\RESISTORS\RCXXXXL-SER_MAR18.PDF
R354 = RESISTOR: RES 4.7K 1/16W 5% 0402; Chkd/date: VASANTHA/130516; Crtd /date: VASANTHA/130516; Custom_Duty: 15%; Customs_HS_Code: 85332119; Distributor_name: DIGIKEY; Distributor_part_number: 311-4.7KJRCT-ND; Footprint Path: Y:\MIS_DATABASE\Library\ALTIUM_TOOL\PCB_FOOTPRINTS\Altium_Footprint_Lib.PcbLib; Height: 0.40MM; Library Path: Y:\MIS_DATABASE\Library\ALTIUM_TOOL\SCHEMATICS_PARTS\MS_DISCRETE_Library.schlib; Mfr_name: YAGEO AMERICA; Mfr_part_number: RC0402JR-074K7L; Mistral Part No: 110011060001-R; Package: 0402; Part_type: RESISTORS\FIXED; Project: TMDXCSK368; RoHS: RoHS; Temperature: -55°C+155°C; Tolerance: 5%; Voltage: NA; Wattage: 1/16W; Weight: 0.65mg; Datasheet: Y:\MIS_DATABASE\DATASHEETS\RESISTORS\RCXXXXL-SER_MAR18.PDF
R358 = RESISTOR: RES 4.87K 1/10W 1% 0402; Chkd/date: MAZHAR/150709; Crtd /date: USMAN/150109; Custom_Duty: 15%; Customs_HS_Code: 85332119; Distributor_name: DIGIKEY; Distributor_part_number: P4.87KLCT-ND; Footprint Path: Y:\MIS_DATABASE\Library\ALTIUM_TOOL\PCB_FOOTPRINTS\Altium_Footprint_Lib.PcbLib; Height: 0.40MM; Library Path: Y:\MIS_DATABASE\Library\ALTIUM_TOOL\SCHEMATICS_PARTS\MS_DISCRETE_Library.schlib; Mfr_name: PANASONIC-ECG; Mfr_part_number: ERJ-2RKF4871X; Mistral Part No: 110009030803-R; Package: 0402; Part_type: RESISTORS\FIXED; Project: BSN-II; RoHS: RoHS; Temperature: -55°C+155°C; Tolerance: 1%; Voltage: NA; Wattage: 1/10W; Weight: 0.8mg; Datasheet: Y:\MIS_DATABASE\DATASHEETS\RESISTORS\PAN-ERJSER_NOV17.PDF
TP66-TP73 = TESTPOINT: TESTPOINT CIR 40 SMD; Chkd/date: MAZHAR/190505; Crtd /date: MAZHAR/190505; Distributor_name: NA; Distributor_part_number: NA; Footprint Path: Y:\MIS_DATABASE\Library\ALTIUM_TOOL\PCB_FOOTPRINTS\Altium_Footprint_Lib.PcbLib; Height: NA; Library Path: Y:\MIS_DATABASE\Library\ALTIUM_TOOL\SCHEMATICS_PARTS\MS_DISCRETE_Library.schlib; MECHANICAL 3D STEP FILE: NA; Mfr_name: LOCAL; Mistral Part No: 130009030933; Package: SMD; Project: RAINIER-3; RoHS: NA; Temperature: NA; Tolerance: NA; Voltage: NA; Wattage: NA; Weight: NA; Datasheet: NA
TP74 = TESTPOINT: TESTPOINT 1.0MM DRILL PTH; Chkd/date: MAZHAR/271211; Crtd /date: SHREESHAIL/041005; Distributor_name: NA; Distributor_part_number: NA; Height: NA; Mfr_name: LOCAL; Mistral Part No: 130009030938; Package: THRU-HOLE; Project: HSE; Datasheet: NA
U51 = TPS79601DRBR_SON8: IC 1A HIGH PSRR RF ADJ LDO LINEAR REGULATOR SON8; Chkd/date: MANIRAJA/030518; Crtd /date: MAZHAR/280809; Custom_Duty: 15%; Customs_HS_Code: 85423100; Distributor_name: DIGIKEY; Distributor_part_number: 296-23107-1-ND; Footprint Path: Y:\MIS_DATABASE\Library\ALTIUM_TOOL\PCB_FOOTPRINTS\Altium_Footprint_Lib.PcbLib; Height: 1.00MM; Library Path: Y:\MIS_DATABASE\Library\ALTIUM_TOOL\SCHEMATICS_PARTS\MS_MISCPOWER_Library.schlib; Mfr_name: TEXAS INSTRUMENTS; Mistral Part No: 142009080012-R; Package: SON8; Part_type: ICS\POWER\VOLTAGE REGULATOR; Project: DIO_TXRX; RoHS: RoHS; Temperature: -40°C+125°C; Tolerance: NA; Voltage: NA; Wattage: NA; Weight: 24mg; Datasheet: Y:\MIS_DATABASE\DATASHEETS\MISC\REGULATORS\TPS796XX.PDF
U52 = TM4C1294NCPDTT3R_TQFP128: IC 32-BIT MICROCONTROLLER WITH 1MB FLASH TQFP128; Chkd/date: MANIRAJA/220817; Crtd /date: MANIRAJA/220817; Custom_Duty: 15%; Customs_HS_Code: 85423100; Distributor_name: DIGIKEY; Distributor_part_number: TM4C1294NCPDTT3R-ND; Height: 1.20MM; Mfr_name: TEXAS INSTRUMENTS; Mistral Part No: 141217080002-R; Package: TQF9128; Part_type: ICS\DIGITAL\MICROCONTROLLER; Project: TI_MAXIE_CPB; RoHS: RoHS; Temperature: -40°C+105°C; Tolerance: NA; Voltage: NA; Wattage: NA; Weight: 503.5mg; Datasheet: Y:\MIS_DATABASE\DATASHEETS\ICS\DIGITAL\MICROCONTROLLER\TM4C1294NCPD.PDF
U53 = TPD4E004_SON6_0: IC 4-CH ESD PROTECTION ARRAY FOR HIGH SPEED DATA INTERFACE SON6; Chkd/date: MANIRAJA/100320; Crtd /date: MUDDU/010310; Custom_Duty: 15%; Customs_HS_Code: 85423100; Distributor_name: DIGIKEY; Distributor_part_number: 296-23618-1-ND; Footprint Path: Y:\MIS_DATABASE\Library\ALTIUM_TOOL\PCB_FOOTPRINTS\Altium_Footprint_Lib.PcbLib; Height: 0.60MM; Library Path: Y:\MIS_DATABASE\Library\ALTIUM_TOOL\SCHEMATICS_PARTS\MS_MISCINTERFACE_Library.schlib; Library Ref: TPD4E004_SON6; Mfr_name: TEXAS INSTRUMENTS; Mistral Part No: 141010020012-R; Package: SON6; Part_type: ICS\INTERFACE; Project: BUG_BASE-II; RoHS: RoHS; Temperature: -40°C+85°C; Tolerance: NA; Voltage: NA; Wattage: NA; Weight: 3.2mg; Datasheet: Y:\MIS_DATABASE\DATASHEETS\ICS\INTERFACE\TPD4E004-SER.PDF
U54 = ISO7221XD_SOIC8: IC DUAL-CHANNEL DIGITAL ISOLATOR SOIC8; Chkd/date: MANIRAJA/141021; Crtd /date: ALVY/131021; Custom_Duty: 15%; Customs_HS_Code: 85423100; Distributor_name: DIGIKEY; Distributor_part_number: 296-21956-1-ND; Footprint Path: Y:\MIS_DATABASE\Library\ALTIUM_TOOL\PCB_FOOTPRINTS\Altium_Footprint_Lib.PcbLib; Height: 1.75MM; Library Path: Y:\MIS_DATABASE\Library\ALTIUM_TOOL\SCHEMATICS_PARTS\MS_MISC_Library.schlib; Mfr_name: TEXAS INSTRUMENTS; Mistral Part No: 141021100003-R; Package: SOIC8; Part_type: ICS\DIGITAL\ISOLATOR; Project: ENEKOM_SMART SENSOR SYSTEM; RoHS: RoHS; Temperature: -40°C+125°C; Tolerance: NA; Voltage: NA; Wattage: NA; Weight: 540mg; Datasheet: Y:\MIS_DATABASE\DATASHEETS\ICS\MISC\ISO722XXD.PDF
U55 = LM4040B25IDCKR_SC70-5: IC PRECISION MICROPOWER SHUNT VOLTAGE REFERENCE SC70-5; Automotive Alternate_mfr_name: TEXAS INSTRUMENTS; Automotive Alternate_mfr_part_number: TL4050B25QDCKRQ1; Chkd/date: MANIRAJA/230817; Crtd /date: MANIRAJA/230817; Custom_Duty: 15%; Customs_HS_Code: 85423100; Distributor_name: DIGIKEY; Distributor_part_number: 296-20873-1-ND; Height: 1.10MM; Mfr_name: TEXAS INSTRUMENTS; Mistral Part No: 142017080015-R; Package: SC70-5; Part_type: ICS\POWER\VOLTAGE REGULATOR; Project: TI_MAXIE_CPB; RoHS: RoHS; Temperature: -40°C+85°C; Tolerance: NA; Voltage: NA; Wattage: NA; Weight: 30mg; Datasheet: Y:\MIS_DATABASE\DATASHEETS\ICS\POWER\LM4040B25I.PDF
Y2 = CRY4_13: CRY 16.000MHz SMD; Chkd/date: MANIRAJA/230817; Crtd /date: MANIRAJA/230817; Custom_Duty: 24%; Customs_HS_Code: 85439000; Distributor_name: DIGIKEY; Distributor_part_number: 644-1157-1-ND; Height: 0.90MM; Mfr_name: NDK; Mfr_part_number: NX3225GA-16.000M-STD-CRG-1; Mistral Part No: 130017080024-R; Package: SMD; Part_type: CRYSTAL; Project: TI_MAXIE_CPB; RoHS: RoHS; Temperature: -40°C+85°C; Tolerance: NA; Voltage: NA; Wattage: NA; Weight: NA; Datasheet: Y:\MIS_DATABASE\DATASHEETS\MISC\CRY_OSC\NX3225GA.PDF

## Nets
DGND: C265.2 U54.4(GND1) ; also on sheet 1 2 3 4 6 7 8 9 10 11 12 13 14 15 16 24 25 26 27 28 29 30 32 33
V3V3_XDS_FB: C248.2 R332.2 R333.1 U51.5(NR/FB)
VBAT_XDS: C262.1 R334.2 U52.68(VBAT)
VBUS_XDS110: C256.1 J13.1(VBUS) R339.2 R340.1 TP66.1(TP) U51.1(IN1) U51.2(IN2) U51.8(EN) U53.6(VCC)
VCC3V3_XDS: C248.1 C249.1 C250.1 C251.1 C252.1 C253.1 C254.1 C255.1 C257.1 C258.1 C266.1 R332.1 R334.1 R345.2 R346.2 R347.2 R348.2 R353.1 R354.1 R356.1 R357.1 TP67.1(TP) U51.3(OUT1) U51.4(OUT2) U52.7(VDD) U52.8(VDDA) U52.16(VDD) U52.26(VDD) U52.28(VDD) U52.39(VDD) U52.47(VDD) U52.51(VDD) U52.52(VDD) U52.69(VDD) U52.79(VDD) U52.90(VDD) U52.101(VDD) U52.113(VDD) U52.122(VDD) U54.8(VCC2) ; also on sheet 3 27 28
VDDC_1V2_XDS: C259.1 C260.1 C261.1 U52.87(VDDC) U52.115(VDDC)
BOOTMODE_XDS_I2C_SCL: U52.49(PG0) ; also on sheet 3
BOOTMODE_XDS_I2C_SDA: U52.50(PG1) ; also on sheet 3
OSC0: C269.2 U52.88(OSC0) Y2.1
OSC1: C270.2 U52.89(OSC1) Y2.3
SOC_XDS_I2C2_SCL: U52.82(PL1) ; also on sheet 28
SOC_XDS_I2C2_SDA: U52.81(PL0) ; also on sheet 28
TA_GPIO1_XDS: U52.74(PM4) ; also on sheet 3
TA_GPIO2_XDS: U52.73(PM5) ; also on sheet 3
TA_GPIO3_XDS: U52.72(PM6) ; also on sheet 3
TA_GPIO4_XDS: U52.71(PM7) ; also on sheet 3
TA_PORZn_XDS: U52.77(PM1) ; also on sheet 3
TA_POWERDOWNz_XDS: U52.78(PM0) ; also on sheet 3
TA_RESETz_XDS: U52.76(PM2) ; also on sheet 3
TM4C129_RST#: R353.2 R355.1 TP73.1(TP) U52.70(~{RST})
TM4C129_TCK: TP68.1(TP) U52.100(PC0/TCK/SWCLK)
TM4C129_TDI: TP70.1(TP) U52.98(PC2/TDI)
TM4C129_TDO: TP71.1(TP) U52.97(PC3/TDO/SWO)
TM4C129_TMS: TP69.1(TP) U52.99(PC1/TMS/SWDIO)
UART0_RXD: R344.1 ; also on sheet 26
UART0_TXD: U54.3(INB) ; also on sheet 26
USB_XDS110_ID: J13.4(ID) R338.2 U53.4(IO3)
VSYS_3V3_LDO1: C265.1 U54.1(VCC1) ; also on sheet 1 6 7 9 10 11 12 13 14 15 16 24 26 27 28 29 30 32 33
XDS110_EMU0: R357.2 U52.42(PF0)
XDS110_EMU1: R356.2 U52.43(PF1)
XDS110_PROG_STAZ1: R342.2 U52.4(PD3/AIN12)
XDS110_PROG_STAZ2: R343.1 U52.3(PD2/AIN13)
XDS110_TCK: U52.35(PA2/SSI0CLK) ; also on sheet 27
XDS110_TDI: U52.38(PA5/SSI0XDAT1) ; also on sheet 27
XDS110_TDO: U52.37(PA4/SSI0XDAT0) ; also on sheet 27
XDS110_TMS: U52.36(PA3/SSI0FSS) ; also on sheet 27
XDS110_TRST#: R337.1 U52.40(PA6)
XDS110_UART0_RXD: U52.33(PA0/U0RX) U54.6(OUTB)
XDS110_UART0_TXD: R336.1 U54.7(INA)
XDS110_VBUS_DET: R340.2 R341.1 U52.1(PD0/AIN15)
XDS_GND: C249.2 C250.2 C251.2 C252.2 C253.2 C254.2 C255.2 C256.2 C257.2 C258.2 C259.2 C260.2 C261.2 C262.2 C263.2 C264.2 C266.2 C267.2 C268.2 C269.1 C270.1 J13.5(GND) LD9.1(CATHODE) LD10.1(CATHODE) R333.2 R335.2 R337.2 R341.2 R349.1 R350.1 R351.1 R352.1 R355.2 R358.2 TP74.1(TP) U51.6(GND) U51.9(PAD) U52.10(GNDA) U52.17(GND) U52.48(GND) U52.55(GND) U52.58(GND) U52.64(~{WAKE}) U52.66(XOSC0) U52.80(GND) U52.114(GND) U53.3(GND) U54.5(GND2) U55.1(ANODE) Y2.2 Y2.4 ; also on sheet 3 27 28
XDS_RBIAS: R358.1 U52.59(RBAIS)
XDS_SHIELD: C263.1 J13.6(SH1) J13.7(SH2) J13.8(SH3) J13.9(SH4) J13.10(SH5) J13.11(SH6) R335.1
XDS_USB_D_N: J13.2(D-) U52.93(PL7/USB0DM) U53.1(IO1)
XDS_USB_D_P: J13.3(D+) U52.94(PL6/USB0DP) U53.2(IO2)
XDS_USB_ID: R338.1 U52.95(PB0/USB0ID)
XDS_VREF: C267.1 C268.1 R354.2 U52.9(VREFA+) U55.3(CATHODE)
N23200398: C264.1 R339.1 U52.96(PB1/USB0VBUS)
N23200423: R345.1 R349.2 U52.60(PK7)
N23200491: LD10.2(ANODE) R343.2
N23200507: R348.1 R352.2 U52.63(PK4)
N23200509: R346.1 R350.2 U52.61(PK6)
N23200516: R347.1 R351.2 U52.62(PK5)
N23200616: LD9.2(ANODE) R342.1
N32914108: R336.2 U52.34(PA1/U0TX)
N33884757: R344.2 U54.2(OUTA)
N34660939: TP72.1(TP) U52.75(PM3)

Not connected (* = marked no-connect by the designer): U51 7(NC)*; U52 2(PD1/AIN14)* 5(PQ0)* 6(PQ1)* 11(PQ2)* 12(PE3/AIN0)* 13(PE2/AIN1)* 14(PE1/AIN2)* 15(PE0/AIN3)* 18(PK0/AIN16)* 19(PK1/AIN17)* 20(PK2/AIN18)* 21(PK3/AIN19)* 22(PC7/C0-)* 23(PC6/C0+)* 24(PC5/C1+)* 25(PC4/C1-)* 27(PQ3)* 29(PH0)* 30(PH1)* 31(PH2)* 32(PH3)* 41(PA7)* 44(PF2)* 45(PF3)* 46(PF4)* 53(EN0RXIN)* 54(EN0RXIP)* 56(EN0RX0N)* 57(EN0RX0P)* 65(~{HIB})* 67(XOSC1)* 83(PL2)* 84(PL3)* 85(PL4)* 86(PL5)* 91(PB2/I2C0SCL)* 92(PB3/I2C0SDA)* 102(PQ4)* 103(PP2)* 104(PP3)* 105(PP4)* 106(PP5)* 107(PN0)* 108(PN1)* 109(PN2)* 110(PN3)* 111(PN4)* 112(PN5)* 116(PJ0)* 117(PJ1)* 118(PP0/C2+)* 119(PP1/C2-)* 120(PB5/AIN11)* 121(PB4/AIN10)* 123(PE4/AIN9)* 124(PE5/AIN8)* 125(PD4/AIN7)* 126(PD5/AIN6)* 127(PD6/AIN5)* 128(PD7/AIN4)*; U53 5(IO4)*; U55 2(NC1)* 4(NC2)* 5(NC3)*

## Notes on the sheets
sheet 17
- XDS110 DEBUGGER
- Silkscreen "XDS110"
- 90E
- UART0 BUFFER
- GREEN
- RED
- Set the unique ID
  of the debugger
- EMU signals
sheet 18
- AM263P CC
- PROC159E2
- TABLE OF CONTENTS
- CONTENTS
- PAGE
- 01
- TABLE OF CONTENTS
- 02
- REVISION HISTORY
- 03
- SYSTEM BLOCK DIAGRAM
- 04
- POWER FLOW DIAGRAM
- 05
- POWER SEQUENCING
- 06
- I2C TREE
- 07
- GPIO_MAPPING_TABLE
- 08
- POWER INPUT
- PMIC
- 09
- 10
- POWER SUPPLY #1
- CURRENT MONITORING DEVICES
- 11
- 12
- ETHERNET POWERS
- 13
- SOC-POWER and GND
- 14
- SOC-QSPI & OSPI INTERFACE
- 15
- SOC-MMC0 INTERFACE
- 16
- SOC-IO INTERFACES
- 17
- SOC-JTAG, RESET and CLK
- 18
- MCAN AND FSI MUX
- 19
- SOC-PRU0 ICSS MII0,
  CPSW RGMII/MII Ethernet
- 20
- SOC-PRU1 ICSS MII1 Ethernet
- 21
- ICSS ETHERNET/HSEC  MUXES
- 22
- ICSS ON-BOARD/ADD-ON PHY & MII0/MII1 MUXES
- 23
- CLOCKS AND LIN1
- TEST AUTOMATION HEADER
- 24
- 25
- BOOTMODE BUFFER AND SWITCH
- XDS110 DEBUGGER
- 26
- 27
- AUTOMATION SIGNALS BUFFER
- LED DRIVER AND IO EXPANDER
- 28
- 29
- SOC-ADC & DAC INTERFACE
- 30
- ADC MUXES
- 31
- HSEC CONNECTOR
- 32
- RESET SWITCHES
- 33
- CC EVM NOTES, HW and LABELS
sheet 19
- REVISION HISTORY
- VER #
- DATE
- DESCRIPTION OF CHANGES
- AUTHOR
- REVIEWED  BY
- APPROVED  BY
- 0.01
- 19 JUNE 2023
- Drafted from REV E1 Schematics. Net names updated wrt SOC symbol (U1) pin naming  conventions
- Mistral Design Team
- Added MDIO/MDC Mux (U81) FOR MDIO0_MDIO and MDIO0_MDC signals.
- 0.02
- 21 JUNE 2023
- Mistral Design Team
- Changed the IO expander part (U60) from TCA6416ARTWR to TCA6424ARGJR and it's I2C slave address
  changed to 0x22
- 0.03
- 1 AUG 2023
- Added Circuit for SoC Safety_error (Q20), Removed C3746 cap, C82 Cap changed to 6.8nF,
  DNI'd termination caps on ADC lines (C318 to C324). Added green LEDs for PMIC LDO rails
- Mistral Design Team
- 0.04
- 11 AUG 2023
- Added layer of MUXing to allow MII0 OR MII1 to be inputs for either Ethernet interface -
  on-board PHY or Add-on board connector
- Mistral Design Team
- 0.05
- 16 AUG 2023
- Added 1x2 header (J22) with jumper on INH/PMIC_WKUP2 net
- Mistral Design Team
- 18 AUG 2023
- Added resistor mux across ICSSM Ethernet/HSEC lines
- Mistral Design Team
- 0.06
- 5 SEP 2023
- Resistor muxes across ICSSM Ethernet/HSEC lines value changed from 0E to 33E
- Mistral Design Team
- 0.07
- SW15 - for ICSSM MII0/MII1 signals selection has been removed. SW14 will control all six
  ICSSM  muxes
- 0.08
- 7 SEP 2023
- Mistral Design Team
- Rearrangement is done wrt ICSSM signals, as resistor mux should now be at PHY end of the
  scheme.  Rearranged signals on ADC Muxes (U70,U72,U73). DNI'd R205, Populated R204
  for FSI activation. OSPI_LBCLK connection rearranged.
- 0.09
- 11 SEP 2023
- Mistral Design Team
- 0.10
- 15 SEP 2023
- Changed resistor arrays to individual 0201 0-ohm resistors on ICSSM lines. Added MDC/MDIO
  mux (U90) for Add on connector. DNI'd R3865, Populated R190 with default set to
  HSEC_EPWM11_A.
- Mistral Design Team
- Ethernet/HSEC muxes SEL lines changed to independently controllable SEL lines.(SW16 added
  for ICSSM1_MUX_SEL)
  Changed R474 to pull-up resistor to select CPSW for on-board PHY MDIO/MDC lines. Populated
  all ADC caps - 330 Pf. Populated resistors on MDC lines across U90 and U91). Changed ICSSM
  -> ICSS in all schematic titles
- Mistral Design Team
- 0.11
- 22 SEP 2023
- 0.12
- 03 OCT 2023
- Added shunt jumpers to the schematic for J20,J21,J22
- Mistral Design Team
sheet 20
- SYSTEM BLOCK DIAGRAM
sheet 21
- POWER FLOW DIAGRAM
sheet 22
- I2C TREE DIAGRAM
sheet 23
- GPIO MAPPING TABLE
